# Gemmini ng45 integration model; not a signoff SRAM model
VERSION 5.7 ;
BUSBITCHARS "[]" ;
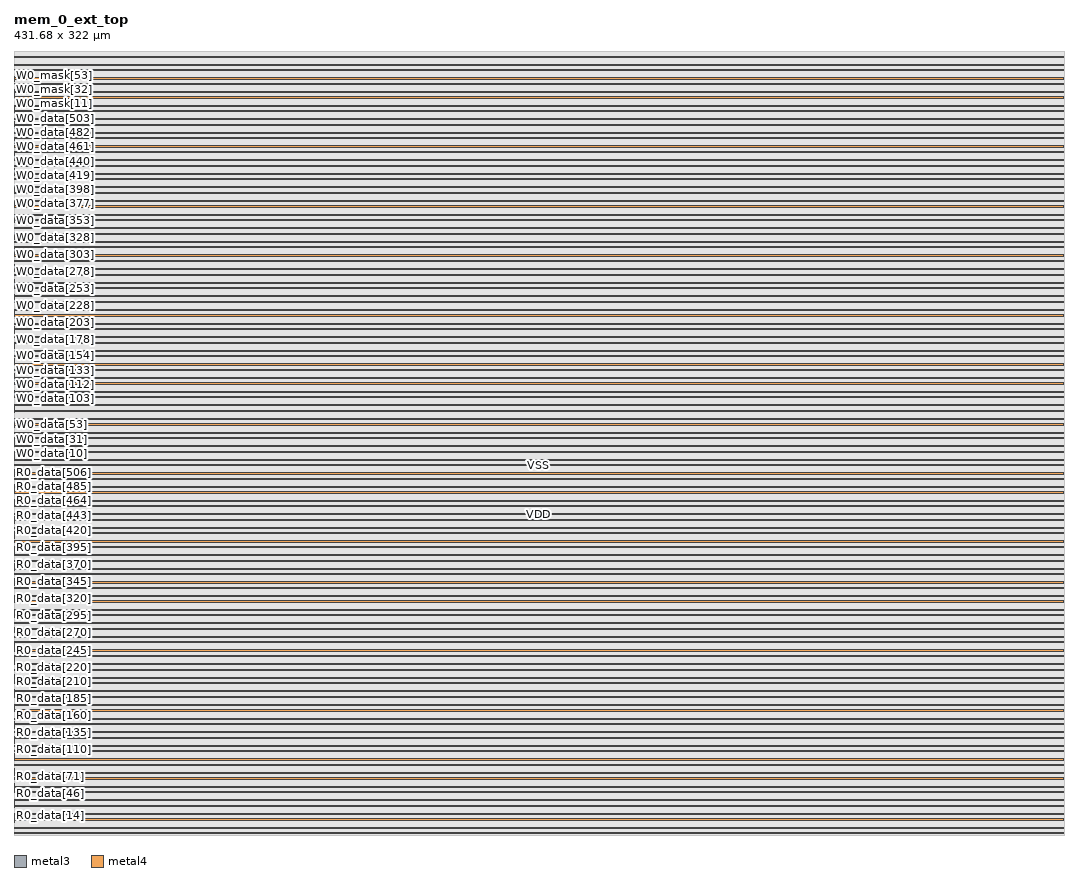
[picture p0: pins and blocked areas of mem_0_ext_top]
MACRO mem_0_ext_top
  FOREIGN mem_0_ext_top 0 0 ;
  SYMMETRY X Y R90 ;
  SIZE 431.680 BY 322.000 ;
  CLASS BLOCK ;
  PIN R0_addr[0]
    DIRECTION INPUT ;
    USE SIGNAL ;
    SHAPE ABUTMENT ;
    PORT
      LAYER metal3 ;
      RECT 0.000 1.365 0.070 1.435 ;
    END
  END R0_addr[0]
  PIN R0_addr[1]
    DIRECTION INPUT ;
    USE SIGNAL ;
    SHAPE ABUTMENT ;
    PORT
      LAYER metal3 ;
      RECT 0.000 1.645 0.070 1.715 ;
    END
  END R0_addr[1]
  PIN R0_addr[2]
    DIRECTION INPUT ;
    USE SIGNAL ;
    SHAPE ABUTMENT ;
    PORT
      LAYER metal3 ;
      RECT 0.000 1.925 0.070 1.995 ;
    END
  END R0_addr[2]
  PIN R0_addr[3]
    DIRECTION INPUT ;
    USE SIGNAL ;
    SHAPE ABUTMENT ;
    PORT
      LAYER metal3 ;
      RECT 0.000 2.205 0.070 2.275 ;
    END
  END R0_addr[3]
  PIN R0_addr[4]
    DIRECTION INPUT ;
    USE SIGNAL ;
    SHAPE ABUTMENT ;
    PORT
      LAYER metal3 ;
      RECT 0.000 2.485 0.070 2.555 ;
    END
  END R0_addr[4]
  PIN R0_addr[5]
    DIRECTION INPUT ;
    USE SIGNAL ;
    SHAPE ABUTMENT ;
    PORT
      LAYER metal3 ;
      RECT 0.000 2.765 0.070 2.835 ;
    END
  END R0_addr[5]
  PIN R0_addr[6]
    DIRECTION INPUT ;
    USE SIGNAL ;
    SHAPE ABUTMENT ;
    PORT
      LAYER metal3 ;
      RECT 0.000 3.045 0.070 3.115 ;
    END
  END R0_addr[6]
  PIN R0_addr[7]
    DIRECTION INPUT ;
    USE SIGNAL ;
    SHAPE ABUTMENT ;
    PORT
      LAYER metal3 ;
      RECT 0.000 3.325 0.070 3.395 ;
    END
  END R0_addr[7]
  PIN R0_addr[8]
    DIRECTION INPUT ;
    USE SIGNAL ;
    SHAPE ABUTMENT ;
    PORT
      LAYER metal3 ;
      RECT 0.000 3.605 0.070 3.675 ;
    END
  END R0_addr[8]
  PIN R0_clk
    DIRECTION INPUT ;
    USE SIGNAL ;
    SHAPE ABUTMENT ;
    PORT
      LAYER metal3 ;
      RECT 0.000 3.885 0.070 3.955 ;
    END
  END R0_clk
  PIN R0_data[0]
    DIRECTION OUTPUT ;
    USE SIGNAL ;
    SHAPE ABUTMENT ;
    PORT
      LAYER metal3 ;
      RECT 0.000 4.165 0.070 4.235 ;
    END
  END R0_data[0]
  PIN R0_data[1]
    DIRECTION OUTPUT ;
    USE SIGNAL ;
    SHAPE ABUTMENT ;
    PORT
      LAYER metal3 ;
      RECT 0.000 4.445 0.070 4.515 ;
    END
  END R0_data[1]
  PIN R0_data[2]
    DIRECTION OUTPUT ;
    USE SIGNAL ;
    SHAPE ABUTMENT ;
    PORT
      LAYER metal3 ;
      RECT 0.000 4.725 0.070 4.795 ;
    END
  END R0_data[2]
  PIN R0_data[3]
    DIRECTION OUTPUT ;
    USE SIGNAL ;
    SHAPE ABUTMENT ;
    PORT
      LAYER metal3 ;
      RECT 0.000 5.005 0.070 5.075 ;
    END
  END R0_data[3]
  PIN R0_data[4]
    DIRECTION OUTPUT ;
    USE SIGNAL ;
    SHAPE ABUTMENT ;
    PORT
      LAYER metal3 ;
      RECT 0.000 5.285 0.070 5.355 ;
    END
  END R0_data[4]
  PIN R0_data[5]
    DIRECTION OUTPUT ;
    USE SIGNAL ;
    SHAPE ABUTMENT ;
    PORT
      LAYER metal3 ;
      RECT 0.000 5.565 0.070 5.635 ;
    END
  END R0_data[5]
  PIN R0_data[6]
    DIRECTION OUTPUT ;
    USE SIGNAL ;
    SHAPE ABUTMENT ;
    PORT
      LAYER metal3 ;
      RECT 0.000 5.845 0.070 5.915 ;
    END
  END R0_data[6]
  PIN R0_data[7]
    DIRECTION OUTPUT ;
    USE SIGNAL ;
    SHAPE ABUTMENT ;
    PORT
      LAYER metal3 ;
      RECT 0.000 6.125 0.070 6.195 ;
    END
  END R0_data[7]
  PIN R0_data[8]
    DIRECTION OUTPUT ;
    USE SIGNAL ;
    SHAPE ABUTMENT ;
    PORT
      LAYER metal3 ;
      RECT 0.000 6.405 0.070 6.475 ;
    END
  END R0_data[8]
  PIN R0_data[9]
    DIRECTION OUTPUT ;
    USE SIGNAL ;
    SHAPE ABUTMENT ;
    PORT
      LAYER metal3 ;
      RECT 0.000 6.685 0.070 6.755 ;
    END
  END R0_data[9]
  PIN R0_data[10]
    DIRECTION OUTPUT ;
    USE SIGNAL ;
    SHAPE ABUTMENT ;
    PORT
      LAYER metal3 ;
      RECT 0.000 6.965 0.070 7.035 ;
    END
  END R0_data[10]
  PIN R0_data[11]
    DIRECTION OUTPUT ;
    USE SIGNAL ;
    SHAPE ABUTMENT ;
    PORT
      LAYER metal3 ;
      RECT 0.000 7.245 0.070 7.315 ;
    END
  END R0_data[11]
  PIN R0_data[12]
    DIRECTION OUTPUT ;
    USE SIGNAL ;
    SHAPE ABUTMENT ;
    PORT
      LAYER metal3 ;
      RECT 0.000 7.525 0.070 7.595 ;
    END
  END R0_data[12]
  PIN R0_data[13]
    DIRECTION OUTPUT ;
    USE SIGNAL ;
    SHAPE ABUTMENT ;
    PORT
      LAYER metal3 ;
      RECT 0.000 7.805 0.070 7.875 ;
    END
  END R0_data[13]
  PIN R0_data[14]
    DIRECTION OUTPUT ;
    USE SIGNAL ;
    SHAPE ABUTMENT ;
    PORT
      LAYER metal3 ;
      RECT 0.000 8.085 0.070 8.155 ;
    END
  END R0_data[14]
  PIN R0_data[15]
    DIRECTION OUTPUT ;
    USE SIGNAL ;
    SHAPE ABUTMENT ;
    PORT
      LAYER metal3 ;
      RECT 0.000 8.365 0.070 8.435 ;
    END
  END R0_data[15]
  PIN R0_data[16]
    DIRECTION OUTPUT ;
    USE SIGNAL ;
    SHAPE ABUTMENT ;
    PORT
      LAYER metal3 ;
      RECT 0.000 8.645 0.070 8.715 ;
    END
  END R0_data[16]
  PIN R0_data[17]
    DIRECTION OUTPUT ;
    USE SIGNAL ;
    SHAPE ABUTMENT ;
    PORT
      LAYER metal3 ;
      RECT 0.000 8.925 0.070 8.995 ;
    END
  END R0_data[17]
  PIN R0_data[18]
    DIRECTION OUTPUT ;
    USE SIGNAL ;
    SHAPE ABUTMENT ;
    PORT
      LAYER metal3 ;
      RECT 0.000 9.205 0.070 9.275 ;
    END
  END R0_data[18]
  PIN R0_data[19]
    DIRECTION OUTPUT ;
    USE SIGNAL ;
    SHAPE ABUTMENT ;
    PORT
      LAYER metal3 ;
      RECT 0.000 9.485 0.070 9.555 ;
    END
  END R0_data[19]
  PIN R0_data[20]
    DIRECTION OUTPUT ;
    USE SIGNAL ;
    SHAPE ABUTMENT ;
    PORT
      LAYER metal3 ;
      RECT 0.000 9.765 0.070 9.835 ;
    END
  END R0_data[20]
  PIN R0_data[21]
    DIRECTION OUTPUT ;
    USE SIGNAL ;
    SHAPE ABUTMENT ;
    PORT
      LAYER metal3 ;
      RECT 0.000 10.045 0.070 10.115 ;
    END
  END R0_data[21]
  PIN R0_data[22]
    DIRECTION OUTPUT ;
    USE SIGNAL ;
    SHAPE ABUTMENT ;
    PORT
      LAYER metal3 ;
      RECT 0.000 10.325 0.070 10.395 ;
    END
  END R0_data[22]
  PIN R0_data[23]
    DIRECTION OUTPUT ;
    USE SIGNAL ;
    SHAPE ABUTMENT ;
    PORT
      LAYER metal3 ;
      RECT 0.000 10.605 0.070 10.675 ;
    END
  END R0_data[23]
  PIN R0_data[24]
    DIRECTION OUTPUT ;
    USE SIGNAL ;
    SHAPE ABUTMENT ;
    PORT
      LAYER metal3 ;
      RECT 0.000 10.885 0.070 10.955 ;
    END
  END R0_data[24]
  PIN R0_data[25]
    DIRECTION OUTPUT ;
    USE SIGNAL ;
    SHAPE ABUTMENT ;
    PORT
      LAYER metal3 ;
      RECT 0.000 11.165 0.070 11.235 ;
    END
  END R0_data[25]
  PIN R0_data[26]
    DIRECTION OUTPUT ;
    USE SIGNAL ;
    SHAPE ABUTMENT ;
    PORT
      LAYER metal3 ;
      RECT 0.000 11.445 0.070 11.515 ;
    END
  END R0_data[26]
  PIN R0_data[27]
    DIRECTION OUTPUT ;
    USE SIGNAL ;
    SHAPE ABUTMENT ;
    PORT
      LAYER metal3 ;
      RECT 0.000 11.725 0.070 11.795 ;
    END
  END R0_data[27]
  PIN R0_data[28]
    DIRECTION OUTPUT ;
    USE SIGNAL ;
    SHAPE ABUTMENT ;
    PORT
      LAYER metal3 ;
      RECT 0.000 12.005 0.070 12.075 ;
    END
  END R0_data[28]
  PIN R0_data[29]
    DIRECTION OUTPUT ;
    USE SIGNAL ;
    SHAPE ABUTMENT ;
    PORT
      LAYER metal3 ;
      RECT 0.000 12.285 0.070 12.355 ;
    END
  END R0_data[29]
  PIN R0_data[30]
    DIRECTION OUTPUT ;
    USE SIGNAL ;
    SHAPE ABUTMENT ;
    PORT
      LAYER metal3 ;
      RECT 0.000 12.565 0.070 12.635 ;
    END
  END R0_data[30]
  PIN R0_data[31]
    DIRECTION OUTPUT ;
    USE SIGNAL ;
    SHAPE ABUTMENT ;
    PORT
      LAYER metal3 ;
      RECT 0.000 12.845 0.070 12.915 ;
    END
  END R0_data[31]
  PIN R0_data[32]
    DIRECTION OUTPUT ;
    USE SIGNAL ;
    SHAPE ABUTMENT ;
    PORT
      LAYER metal3 ;
      RECT 0.000 13.125 0.070 13.195 ;
    END
  END R0_data[32]
  PIN R0_data[33]
    DIRECTION OUTPUT ;
    USE SIGNAL ;
    SHAPE ABUTMENT ;
    PORT
      LAYER metal3 ;
      RECT 0.000 13.405 0.070 13.475 ;
    END
  END R0_data[33]
  PIN R0_data[34]
    DIRECTION OUTPUT ;
    USE SIGNAL ;
    SHAPE ABUTMENT ;
    PORT
      LAYER metal3 ;
      RECT 0.000 13.685 0.070 13.755 ;
    END
  END R0_data[34]
  PIN R0_data[35]
    DIRECTION OUTPUT ;
    USE SIGNAL ;
    SHAPE ABUTMENT ;
    PORT
      LAYER metal3 ;
      RECT 0.000 13.965 0.070 14.035 ;
    END
  END R0_data[35]
  PIN R0_data[36]
    DIRECTION OUTPUT ;
    USE SIGNAL ;
    SHAPE ABUTMENT ;
    PORT
      LAYER metal3 ;
      RECT 0.000 14.245 0.070 14.315 ;
    END
  END R0_data[36]
  PIN R0_data[37]
    DIRECTION OUTPUT ;
    USE SIGNAL ;
    SHAPE ABUTMENT ;
    PORT
      LAYER metal3 ;
      RECT 0.000 14.525 0.070 14.595 ;
    END
  END R0_data[37]
  PIN R0_data[38]
    DIRECTION OUTPUT ;
    USE SIGNAL ;
    SHAPE ABUTMENT ;
    PORT
      LAYER metal3 ;
      RECT 0.000 14.805 0.070 14.875 ;
    END
  END R0_data[38]
  PIN R0_data[39]
    DIRECTION OUTPUT ;
    USE SIGNAL ;
    SHAPE ABUTMENT ;
    PORT
      LAYER metal3 ;
      RECT 0.000 15.085 0.070 15.155 ;
    END
  END R0_data[39]
  PIN R0_data[40]
    DIRECTION OUTPUT ;
    USE SIGNAL ;
    SHAPE ABUTMENT ;
    PORT
      LAYER metal3 ;
      RECT 0.000 15.365 0.070 15.435 ;
    END
  END R0_data[40]
  PIN R0_data[41]
    DIRECTION OUTPUT ;
    USE SIGNAL ;
    SHAPE ABUTMENT ;
    PORT
      LAYER metal3 ;
      RECT 0.000 15.645 0.070 15.715 ;
    END
  END R0_data[41]
  PIN R0_data[42]
    DIRECTION OUTPUT ;
    USE SIGNAL ;
    SHAPE ABUTMENT ;
    PORT
      LAYER metal3 ;
      RECT 0.000 15.925 0.070 15.995 ;
    END
  END R0_data[42]
  PIN R0_data[43]
    DIRECTION OUTPUT ;
    USE SIGNAL ;
    SHAPE ABUTMENT ;
    PORT
      LAYER metal3 ;
      RECT 0.000 16.205 0.070 16.275 ;
    END
  END R0_data[43]
  PIN R0_data[44]
    DIRECTION OUTPUT ;
    USE SIGNAL ;
    SHAPE ABUTMENT ;
    PORT
      LAYER metal3 ;
      RECT 0.000 16.485 0.070 16.555 ;
    END
  END R0_data[44]
  PIN R0_data[45]
    DIRECTION OUTPUT ;
    USE SIGNAL ;
    SHAPE ABUTMENT ;
    PORT
      LAYER metal3 ;
      RECT 0.000 16.765 0.070 16.835 ;
    END
  END R0_data[45]
  PIN R0_data[46]
    DIRECTION OUTPUT ;
    USE SIGNAL ;
    SHAPE ABUTMENT ;
    PORT
      LAYER metal3 ;
      RECT 0.000 17.045 0.070 17.115 ;
    END
  END R0_data[46]
  PIN R0_data[47]
    DIRECTION OUTPUT ;
    USE SIGNAL ;
    SHAPE ABUTMENT ;
    PORT
      LAYER metal3 ;
      RECT 0.000 17.325 0.070 17.395 ;
    END
  END R0_data[47]
  PIN R0_data[48]
    DIRECTION OUTPUT ;
    USE SIGNAL ;
    SHAPE ABUTMENT ;
    PORT
      LAYER metal3 ;
      RECT 0.000 17.605 0.070 17.675 ;
    END
  END R0_data[48]
  PIN R0_data[49]
    DIRECTION OUTPUT ;
    USE SIGNAL ;
    SHAPE ABUTMENT ;
    PORT
      LAYER metal3 ;
      RECT 0.000 17.885 0.070 17.955 ;
    END
  END R0_data[49]
  PIN R0_data[50]
    DIRECTION OUTPUT ;
    USE SIGNAL ;
    SHAPE ABUTMENT ;
    PORT
      LAYER metal3 ;
      RECT 0.000 18.165 0.070 18.235 ;
    END
  END R0_data[50]
  PIN R0_data[51]
    DIRECTION OUTPUT ;
    USE SIGNAL ;
    SHAPE ABUTMENT ;
    PORT
      LAYER metal3 ;
      RECT 0.000 18.445 0.070 18.515 ;
    END
  END R0_data[51]
  PIN R0_data[52]
    DIRECTION OUTPUT ;
    USE SIGNAL ;
    SHAPE ABUTMENT ;
    PORT
      LAYER metal3 ;
      RECT 0.000 18.725 0.070 18.795 ;
    END
  END R0_data[52]
  PIN R0_data[53]
    DIRECTION OUTPUT ;
    USE SIGNAL ;
    SHAPE ABUTMENT ;
    PORT
      LAYER metal3 ;
      RECT 0.000 19.005 0.070 19.075 ;
    END
  END R0_data[53]
  PIN R0_data[54]
    DIRECTION OUTPUT ;
    USE SIGNAL ;
    SHAPE ABUTMENT ;
    PORT
      LAYER metal3 ;
      RECT 0.000 19.285 0.070 19.355 ;
    END
  END R0_data[54]
  PIN R0_data[55]
    DIRECTION OUTPUT ;
    USE SIGNAL ;
    SHAPE ABUTMENT ;
    PORT
      LAYER metal3 ;
      RECT 0.000 19.565 0.070 19.635 ;
    END
  END R0_data[55]
  PIN R0_data[56]
    DIRECTION OUTPUT ;
    USE SIGNAL ;
    SHAPE ABUTMENT ;
    PORT
      LAYER metal3 ;
      RECT 0.000 19.845 0.070 19.915 ;
    END
  END R0_data[56]
  PIN R0_data[57]
    DIRECTION OUTPUT ;
    USE SIGNAL ;
    SHAPE ABUTMENT ;
    PORT
      LAYER metal3 ;
      RECT 0.000 20.125 0.070 20.195 ;
    END
  END R0_data[57]
  PIN R0_data[58]
    DIRECTION OUTPUT ;
    USE SIGNAL ;
    SHAPE ABUTMENT ;
    PORT
      LAYER metal3 ;
      RECT 0.000 20.405 0.070 20.475 ;
    END
  END R0_data[58]
  PIN R0_data[59]
    DIRECTION OUTPUT ;
    USE SIGNAL ;
    SHAPE ABUTMENT ;
    PORT
      LAYER metal3 ;
      RECT 0.000 20.685 0.070 20.755 ;
    END
  END R0_data[59]
  PIN R0_data[60]
    DIRECTION OUTPUT ;
    USE SIGNAL ;
    SHAPE ABUTMENT ;
    PORT
      LAYER metal3 ;
      RECT 0.000 20.965 0.070 21.035 ;
    END
  END R0_data[60]
  PIN R0_data[61]
    DIRECTION OUTPUT ;
    USE SIGNAL ;
    SHAPE ABUTMENT ;
    PORT
      LAYER metal3 ;
      RECT 0.000 21.245 0.070 21.315 ;
    END
  END R0_data[61]
  PIN R0_data[62]
    DIRECTION OUTPUT ;
    USE SIGNAL ;
    SHAPE ABUTMENT ;
    PORT
      LAYER metal3 ;
      RECT 0.000 21.525 0.070 21.595 ;
    END
  END R0_data[62]
  PIN R0_data[63]
    DIRECTION OUTPUT ;
    USE SIGNAL ;
    SHAPE ABUTMENT ;
    PORT
      LAYER metal3 ;
      RECT 0.000 21.805 0.070 21.875 ;
    END
  END R0_data[63]
  PIN R0_data[64]
    DIRECTION OUTPUT ;
    USE SIGNAL ;
    SHAPE ABUTMENT ;
    PORT
      LAYER metal3 ;
      RECT 0.000 22.085 0.070 22.155 ;
    END
  END R0_data[64]
  PIN R0_data[65]
    DIRECTION OUTPUT ;
    USE SIGNAL ;
    SHAPE ABUTMENT ;
    PORT
      LAYER metal3 ;
      RECT 0.000 22.365 0.070 22.435 ;
    END
  END R0_data[65]
  PIN R0_data[66]
    DIRECTION OUTPUT ;
    USE SIGNAL ;
    SHAPE ABUTMENT ;
    PORT
      LAYER metal3 ;
      RECT 0.000 22.645 0.070 22.715 ;
    END
  END R0_data[66]
  PIN R0_data[67]
    DIRECTION OUTPUT ;
    USE SIGNAL ;
    SHAPE ABUTMENT ;
    PORT
      LAYER metal3 ;
      RECT 0.000 22.925 0.070 22.995 ;
    END
  END R0_data[67]
  PIN R0_data[68]
    DIRECTION OUTPUT ;
    USE SIGNAL ;
    SHAPE ABUTMENT ;
    PORT
      LAYER metal3 ;
      RECT 0.000 23.205 0.070 23.275 ;
    END
  END R0_data[68]
  PIN R0_data[69]
    DIRECTION OUTPUT ;
    USE SIGNAL ;
    SHAPE ABUTMENT ;
    PORT
      LAYER metal3 ;
      RECT 0.000 23.485 0.070 23.555 ;
    END
  END R0_data[69]
  PIN R0_data[70]
    DIRECTION OUTPUT ;
    USE SIGNAL ;
    SHAPE ABUTMENT ;
    PORT
      LAYER metal3 ;
      RECT 0.000 23.765 0.070 23.835 ;
    END
  END R0_data[70]
  PIN R0_data[71]
    DIRECTION OUTPUT ;
    USE SIGNAL ;
    SHAPE ABUTMENT ;
    PORT
      LAYER metal3 ;
      RECT 0.000 24.045 0.070 24.115 ;
    END
  END R0_data[71]
  PIN R0_data[72]
    DIRECTION OUTPUT ;
    USE SIGNAL ;
    SHAPE ABUTMENT ;
    PORT
      LAYER metal3 ;
      RECT 0.000 24.325 0.070 24.395 ;
    END
  END R0_data[72]
  PIN R0_data[73]
    DIRECTION OUTPUT ;
    USE SIGNAL ;
    SHAPE ABUTMENT ;
    PORT
      LAYER metal3 ;
      RECT 0.000 24.605 0.070 24.675 ;
    END
  END R0_data[73]
  PIN R0_data[74]
    DIRECTION OUTPUT ;
    USE SIGNAL ;
    SHAPE ABUTMENT ;
    PORT
      LAYER metal3 ;
      RECT 0.000 24.885 0.070 24.955 ;
    END
  END R0_data[74]
  PIN R0_data[75]
    DIRECTION OUTPUT ;
    USE SIGNAL ;
    SHAPE ABUTMENT ;
    PORT
      LAYER metal3 ;
      RECT 0.000 25.165 0.070 25.235 ;
    END
  END R0_data[75]
  PIN R0_data[76]
    DIRECTION OUTPUT ;
    USE SIGNAL ;
    SHAPE ABUTMENT ;
    PORT
      LAYER metal3 ;
      RECT 0.000 25.445 0.070 25.515 ;
    END
  END R0_data[76]
  PIN R0_data[77]
    DIRECTION OUTPUT ;
    USE SIGNAL ;
    SHAPE ABUTMENT ;
    PORT
      LAYER metal3 ;
      RECT 0.000 25.725 0.070 25.795 ;
    END
  END R0_data[77]
  PIN R0_data[78]
    DIRECTION OUTPUT ;
    USE SIGNAL ;
    SHAPE ABUTMENT ;
    PORT
      LAYER metal3 ;
      RECT 0.000 26.005 0.070 26.075 ;
    END
  END R0_data[78]
  PIN R0_data[79]
    DIRECTION OUTPUT ;
    USE SIGNAL ;
    SHAPE ABUTMENT ;
    PORT
      LAYER metal3 ;
      RECT 0.000 26.285 0.070 26.355 ;
    END
  END R0_data[79]
  PIN R0_data[80]
    DIRECTION OUTPUT ;
    USE SIGNAL ;
    SHAPE ABUTMENT ;
    PORT
      LAYER metal3 ;
      RECT 0.000 26.565 0.070 26.635 ;
    END
  END R0_data[80]
  PIN R0_data[81]
    DIRECTION OUTPUT ;
    USE SIGNAL ;
    SHAPE ABUTMENT ;
    PORT
      LAYER metal3 ;
      RECT 0.000 26.845 0.070 26.915 ;
    END
  END R0_data[81]
  PIN R0_data[82]
    DIRECTION OUTPUT ;
    USE SIGNAL ;
    SHAPE ABUTMENT ;
    PORT
      LAYER metal3 ;
      RECT 0.000 27.125 0.070 27.195 ;
    END
  END R0_data[82]
  PIN R0_data[83]
    DIRECTION OUTPUT ;
    USE SIGNAL ;
    SHAPE ABUTMENT ;
    PORT
      LAYER metal3 ;
      RECT 0.000 27.405 0.070 27.475 ;
    END
  END R0_data[83]
  PIN R0_data[84]
    DIRECTION OUTPUT ;
    USE SIGNAL ;
    SHAPE ABUTMENT ;
    PORT
      LAYER metal3 ;
      RECT 0.000 27.685 0.070 27.755 ;
    END
  END R0_data[84]
  PIN R0_data[85]
    DIRECTION OUTPUT ;
    USE SIGNAL ;
    SHAPE ABUTMENT ;
    PORT
      LAYER metal3 ;
      RECT 0.000 27.965 0.070 28.035 ;
    END
  END R0_data[85]
  PIN R0_data[86]
    DIRECTION OUTPUT ;
    USE SIGNAL ;
    SHAPE ABUTMENT ;
    PORT
      LAYER metal3 ;
      RECT 0.000 28.245 0.070 28.315 ;
    END
  END R0_data[86]
  PIN R0_data[87]
    DIRECTION OUTPUT ;
    USE SIGNAL ;
    SHAPE ABUTMENT ;
    PORT
      LAYER metal3 ;
      RECT 0.000 28.525 0.070 28.595 ;
    END
  END R0_data[87]
  PIN R0_data[88]
    DIRECTION OUTPUT ;
    USE SIGNAL ;
    SHAPE ABUTMENT ;
    PORT
      LAYER metal3 ;
      RECT 0.000 28.805 0.070 28.875 ;
    END
  END R0_data[88]
  PIN R0_data[89]
    DIRECTION OUTPUT ;
    USE SIGNAL ;
    SHAPE ABUTMENT ;
    PORT
      LAYER metal3 ;
      RECT 0.000 29.085 0.070 29.155 ;
    END
  END R0_data[89]
  PIN R0_data[90]
    DIRECTION OUTPUT ;
    USE SIGNAL ;
    SHAPE ABUTMENT ;
    PORT
      LAYER metal3 ;
      RECT 0.000 29.365 0.070 29.435 ;
    END
  END R0_data[90]
  PIN R0_data[91]
    DIRECTION OUTPUT ;
    USE SIGNAL ;
    SHAPE ABUTMENT ;
    PORT
      LAYER metal3 ;
      RECT 0.000 29.645 0.070 29.715 ;
    END
  END R0_data[91]
  PIN R0_data[92]
    DIRECTION OUTPUT ;
    USE SIGNAL ;
    SHAPE ABUTMENT ;
    PORT
      LAYER metal3 ;
      RECT 0.000 29.925 0.070 29.995 ;
    END
  END R0_data[92]
  PIN R0_data[93]
    DIRECTION OUTPUT ;
    USE SIGNAL ;
    SHAPE ABUTMENT ;
    PORT
      LAYER metal3 ;
      RECT 0.000 30.205 0.070 30.275 ;
    END
  END R0_data[93]
  PIN R0_data[94]
    DIRECTION OUTPUT ;
    USE SIGNAL ;
    SHAPE ABUTMENT ;
    PORT
      LAYER metal3 ;
      RECT 0.000 30.485 0.070 30.555 ;
    END
  END R0_data[94]
  PIN R0_data[95]
    DIRECTION OUTPUT ;
    USE SIGNAL ;
    SHAPE ABUTMENT ;
    PORT
      LAYER metal3 ;
      RECT 0.000 30.765 0.070 30.835 ;
    END
  END R0_data[95]
  PIN R0_data[96]
    DIRECTION OUTPUT ;
    USE SIGNAL ;
    SHAPE ABUTMENT ;
    PORT
      LAYER metal3 ;
      RECT 0.000 31.045 0.070 31.115 ;
    END
  END R0_data[96]
  PIN R0_data[97]
    DIRECTION OUTPUT ;
    USE SIGNAL ;
    SHAPE ABUTMENT ;
    PORT
      LAYER metal3 ;
      RECT 0.000 31.325 0.070 31.395 ;
    END
  END R0_data[97]
  PIN R0_data[98]
    DIRECTION OUTPUT ;
    USE SIGNAL ;
    SHAPE ABUTMENT ;
    PORT
      LAYER metal3 ;
      RECT 0.000 31.605 0.070 31.675 ;
    END
  END R0_data[98]
  PIN R0_data[99]
    DIRECTION OUTPUT ;
    USE SIGNAL ;
    SHAPE ABUTMENT ;
    PORT
      LAYER metal3 ;
      RECT 0.000 31.885 0.070 31.955 ;
    END
  END R0_data[99]
  PIN R0_data[100]
    DIRECTION OUTPUT ;
    USE SIGNAL ;
    SHAPE ABUTMENT ;
    PORT
      LAYER metal3 ;
      RECT 0.000 32.165 0.070 32.235 ;
    END
  END R0_data[100]
  PIN R0_data[101]
    DIRECTION OUTPUT ;
    USE SIGNAL ;
    SHAPE ABUTMENT ;
    PORT
      LAYER metal3 ;
      RECT 0.000 32.445 0.070 32.515 ;
    END
  END R0_data[101]
  PIN R0_data[102]
    DIRECTION OUTPUT ;
    USE SIGNAL ;
    SHAPE ABUTMENT ;
    PORT
      LAYER metal3 ;
      RECT 0.000 32.725 0.070 32.795 ;
    END
  END R0_data[102]
  PIN R0_data[103]
    DIRECTION OUTPUT ;
    USE SIGNAL ;
    SHAPE ABUTMENT ;
    PORT
      LAYER metal3 ;
      RECT 0.000 33.005 0.070 33.075 ;
    END
  END R0_data[103]
  PIN R0_data[104]
    DIRECTION OUTPUT ;
    USE SIGNAL ;
    SHAPE ABUTMENT ;
    PORT
      LAYER metal3 ;
      RECT 0.000 33.285 0.070 33.355 ;
    END
  END R0_data[104]
  PIN R0_data[105]
    DIRECTION OUTPUT ;
    USE SIGNAL ;
    SHAPE ABUTMENT ;
    PORT
      LAYER metal3 ;
      RECT 0.000 33.565 0.070 33.635 ;
    END
  END R0_data[105]
  PIN R0_data[106]
    DIRECTION OUTPUT ;
    USE SIGNAL ;
    SHAPE ABUTMENT ;
    PORT
      LAYER metal3 ;
      RECT 0.000 33.845 0.070 33.915 ;
    END
  END R0_data[106]
  PIN R0_data[107]
    DIRECTION OUTPUT ;
    USE SIGNAL ;
    SHAPE ABUTMENT ;
    PORT
      LAYER metal3 ;
      RECT 0.000 34.125 0.070 34.195 ;
    END
  END R0_data[107]
  PIN R0_data[108]
    DIRECTION OUTPUT ;
    USE SIGNAL ;
    SHAPE ABUTMENT ;
    PORT
      LAYER metal3 ;
      RECT 0.000 34.405 0.070 34.475 ;
    END
  END R0_data[108]
  PIN R0_data[109]
    DIRECTION OUTPUT ;
    USE SIGNAL ;
    SHAPE ABUTMENT ;
    PORT
      LAYER metal3 ;
      RECT 0.000 34.685 0.070 34.755 ;
    END
  END R0_data[109]
  PIN R0_data[110]
    DIRECTION OUTPUT ;
    USE SIGNAL ;
    SHAPE ABUTMENT ;
    PORT
      LAYER metal3 ;
      RECT 0.000 34.965 0.070 35.035 ;
    END
  END R0_data[110]
  PIN R0_data[111]
    DIRECTION OUTPUT ;
    USE SIGNAL ;
    SHAPE ABUTMENT ;
    PORT
      LAYER metal3 ;
      RECT 0.000 35.245 0.070 35.315 ;
    END
  END R0_data[111]
  PIN R0_data[112]
    DIRECTION OUTPUT ;
    USE SIGNAL ;
    SHAPE ABUTMENT ;
    PORT
      LAYER metal3 ;
      RECT 0.000 35.525 0.070 35.595 ;
    END
  END R0_data[112]
  PIN R0_data[113]
    DIRECTION OUTPUT ;
    USE SIGNAL ;
    SHAPE ABUTMENT ;
    PORT
      LAYER metal3 ;
      RECT 0.000 35.805 0.070 35.875 ;
    END
  END R0_data[113]
  PIN R0_data[114]
    DIRECTION OUTPUT ;
    USE SIGNAL ;
    SHAPE ABUTMENT ;
    PORT
      LAYER metal3 ;
      RECT 0.000 36.085 0.070 36.155 ;
    END
  END R0_data[114]
  PIN R0_data[115]
    DIRECTION OUTPUT ;
    USE SIGNAL ;
    SHAPE ABUTMENT ;
    PORT
      LAYER metal3 ;
      RECT 0.000 36.365 0.070 36.435 ;
    END
  END R0_data[115]
  PIN R0_data[116]
    DIRECTION OUTPUT ;
    USE SIGNAL ;
    SHAPE ABUTMENT ;
    PORT
      LAYER metal3 ;
      RECT 0.000 36.645 0.070 36.715 ;
    END
  END R0_data[116]
  PIN R0_data[117]
    DIRECTION OUTPUT ;
    USE SIGNAL ;
    SHAPE ABUTMENT ;
    PORT
      LAYER metal3 ;
      RECT 0.000 36.925 0.070 36.995 ;
    END
  END R0_data[117]
  PIN R0_data[118]
    DIRECTION OUTPUT ;
    USE SIGNAL ;
    SHAPE ABUTMENT ;
    PORT
      LAYER metal3 ;
      RECT 0.000 37.205 0.070 37.275 ;
    END
  END R0_data[118]
  PIN R0_data[119]
    DIRECTION OUTPUT ;
    USE SIGNAL ;
    SHAPE ABUTMENT ;
    PORT
      LAYER metal3 ;
      RECT 0.000 37.485 0.070 37.555 ;
    END
  END R0_data[119]
  PIN R0_data[120]
    DIRECTION OUTPUT ;
    USE SIGNAL ;
    SHAPE ABUTMENT ;
    PORT
      LAYER metal3 ;
      RECT 0.000 37.765 0.070 37.835 ;
    END
  END R0_data[120]
  PIN R0_data[121]
    DIRECTION OUTPUT ;
    USE SIGNAL ;
    SHAPE ABUTMENT ;
    PORT
      LAYER metal3 ;
      RECT 0.000 38.045 0.070 38.115 ;
    END
  END R0_data[121]
  PIN R0_data[122]
    DIRECTION OUTPUT ;
    USE SIGNAL ;
    SHAPE ABUTMENT ;
    PORT
      LAYER metal3 ;
      RECT 0.000 38.325 0.070 38.395 ;
    END
  END R0_data[122]
  PIN R0_data[123]
    DIRECTION OUTPUT ;
    USE SIGNAL ;
    SHAPE ABUTMENT ;
    PORT
      LAYER metal3 ;
      RECT 0.000 38.605 0.070 38.675 ;
    END
  END R0_data[123]
  PIN R0_data[124]
    DIRECTION OUTPUT ;
    USE SIGNAL ;
    SHAPE ABUTMENT ;
    PORT
      LAYER metal3 ;
      RECT 0.000 38.885 0.070 38.955 ;
    END
  END R0_data[124]
  PIN R0_data[125]
    DIRECTION OUTPUT ;
    USE SIGNAL ;
    SHAPE ABUTMENT ;
    PORT
      LAYER metal3 ;
      RECT 0.000 39.165 0.070 39.235 ;
    END
  END R0_data[125]
  PIN R0_data[126]
    DIRECTION OUTPUT ;
    USE SIGNAL ;
    SHAPE ABUTMENT ;
    PORT
      LAYER metal3 ;
      RECT 0.000 39.445 0.070 39.515 ;
    END
  END R0_data[126]
  PIN R0_data[127]
    DIRECTION OUTPUT ;
    USE SIGNAL ;
    SHAPE ABUTMENT ;
    PORT
      LAYER metal3 ;
      RECT 0.000 39.725 0.070 39.795 ;
    END
  END R0_data[127]
  PIN R0_data[128]
    DIRECTION OUTPUT ;
    USE SIGNAL ;
    SHAPE ABUTMENT ;
    PORT
      LAYER metal3 ;
      RECT 0.000 40.005 0.070 40.075 ;
    END
  END R0_data[128]
  PIN R0_data[129]
    DIRECTION OUTPUT ;
    USE SIGNAL ;
    SHAPE ABUTMENT ;
    PORT
      LAYER metal3 ;
      RECT 0.000 40.285 0.070 40.355 ;
    END
  END R0_data[129]
  PIN R0_data[130]
    DIRECTION OUTPUT ;
    USE SIGNAL ;
    SHAPE ABUTMENT ;
    PORT
      LAYER metal3 ;
      RECT 0.000 40.565 0.070 40.635 ;
    END
  END R0_data[130]
  PIN R0_data[131]
    DIRECTION OUTPUT ;
    USE SIGNAL ;
    SHAPE ABUTMENT ;
    PORT
      LAYER metal3 ;
      RECT 0.000 40.845 0.070 40.915 ;
    END
  END R0_data[131]
  PIN R0_data[132]
    DIRECTION OUTPUT ;
    USE SIGNAL ;
    SHAPE ABUTMENT ;
    PORT
      LAYER metal3 ;
      RECT 0.000 41.125 0.070 41.195 ;
    END
  END R0_data[132]
  PIN R0_data[133]
    DIRECTION OUTPUT ;
    USE SIGNAL ;
    SHAPE ABUTMENT ;
    PORT
      LAYER metal3 ;
      RECT 0.000 41.405 0.070 41.475 ;
    END
  END R0_data[133]
  PIN R0_data[134]
    DIRECTION OUTPUT ;
    USE SIGNAL ;
    SHAPE ABUTMENT ;
    PORT
      LAYER metal3 ;
      RECT 0.000 41.685 0.070 41.755 ;
    END
  END R0_data[134]
  PIN R0_data[135]
    DIRECTION OUTPUT ;
    USE SIGNAL ;
    SHAPE ABUTMENT ;
    PORT
      LAYER metal3 ;
      RECT 0.000 41.965 0.070 42.035 ;
    END
  END R0_data[135]
  PIN R0_data[136]
    DIRECTION OUTPUT ;
    USE SIGNAL ;
    SHAPE ABUTMENT ;
    PORT
      LAYER metal3 ;
      RECT 0.000 42.245 0.070 42.315 ;
    END
  END R0_data[136]
  PIN R0_data[137]
    DIRECTION OUTPUT ;
    USE SIGNAL ;
    SHAPE ABUTMENT ;
    PORT
      LAYER metal3 ;
      RECT 0.000 42.525 0.070 42.595 ;
    END
  END R0_data[137]
  PIN R0_data[138]
    DIRECTION OUTPUT ;
    USE SIGNAL ;
    SHAPE ABUTMENT ;
    PORT
      LAYER metal3 ;
      RECT 0.000 42.805 0.070 42.875 ;
    END
  END R0_data[138]
  PIN R0_data[139]
    DIRECTION OUTPUT ;
    USE SIGNAL ;
    SHAPE ABUTMENT ;
    PORT
      LAYER metal3 ;
      RECT 0.000 43.085 0.070 43.155 ;
    END
  END R0_data[139]
  PIN R0_data[140]
    DIRECTION OUTPUT ;
    USE SIGNAL ;
    SHAPE ABUTMENT ;
    PORT
      LAYER metal3 ;
      RECT 0.000 43.365 0.070 43.435 ;
    END
  END R0_data[140]
  PIN R0_data[141]
    DIRECTION OUTPUT ;
    USE SIGNAL ;
    SHAPE ABUTMENT ;
    PORT
      LAYER metal3 ;
      RECT 0.000 43.645 0.070 43.715 ;
    END
  END R0_data[141]
  PIN R0_data[142]
    DIRECTION OUTPUT ;
    USE SIGNAL ;
    SHAPE ABUTMENT ;
    PORT
      LAYER metal3 ;
      RECT 0.000 43.925 0.070 43.995 ;
    END
  END R0_data[142]
  PIN R0_data[143]
    DIRECTION OUTPUT ;
    USE SIGNAL ;
    SHAPE ABUTMENT ;
    PORT
      LAYER metal3 ;
      RECT 0.000 44.205 0.070 44.275 ;
    END
  END R0_data[143]
  PIN R0_data[144]
    DIRECTION OUTPUT ;
    USE SIGNAL ;
    SHAPE ABUTMENT ;
    PORT
      LAYER metal3 ;
      RECT 0.000 44.485 0.070 44.555 ;
    END
  END R0_data[144]
  PIN R0_data[145]
    DIRECTION OUTPUT ;
    USE SIGNAL ;
    SHAPE ABUTMENT ;
    PORT
      LAYER metal3 ;
      RECT 0.000 44.765 0.070 44.835 ;
    END
  END R0_data[145]
  PIN R0_data[146]
    DIRECTION OUTPUT ;
    USE SIGNAL ;
    SHAPE ABUTMENT ;
    PORT
      LAYER metal3 ;
      RECT 0.000 45.045 0.070 45.115 ;
    END
  END R0_data[146]
  PIN R0_data[147]
    DIRECTION OUTPUT ;
    USE SIGNAL ;
    SHAPE ABUTMENT ;
    PORT
      LAYER metal3 ;
      RECT 0.000 45.325 0.070 45.395 ;
    END
  END R0_data[147]
  PIN R0_data[148]
    DIRECTION OUTPUT ;
    USE SIGNAL ;
    SHAPE ABUTMENT ;
    PORT
      LAYER metal3 ;
      RECT 0.000 45.605 0.070 45.675 ;
    END
  END R0_data[148]
  PIN R0_data[149]
    DIRECTION OUTPUT ;
    USE SIGNAL ;
    SHAPE ABUTMENT ;
    PORT
      LAYER metal3 ;
      RECT 0.000 45.885 0.070 45.955 ;
    END
  END R0_data[149]
  PIN R0_data[150]
    DIRECTION OUTPUT ;
    USE SIGNAL ;
    SHAPE ABUTMENT ;
    PORT
      LAYER metal3 ;
      RECT 0.000 46.165 0.070 46.235 ;
    END
  END R0_data[150]
  PIN R0_data[151]
    DIRECTION OUTPUT ;
    USE SIGNAL ;
    SHAPE ABUTMENT ;
    PORT
      LAYER metal3 ;
      RECT 0.000 46.445 0.070 46.515 ;
    END
  END R0_data[151]
  PIN R0_data[152]
    DIRECTION OUTPUT ;
    USE SIGNAL ;
    SHAPE ABUTMENT ;
    PORT
      LAYER metal3 ;
      RECT 0.000 46.725 0.070 46.795 ;
    END
  END R0_data[152]
  PIN R0_data[153]
    DIRECTION OUTPUT ;
    USE SIGNAL ;
    SHAPE ABUTMENT ;
    PORT
      LAYER metal3 ;
      RECT 0.000 47.005 0.070 47.075 ;
    END
  END R0_data[153]
  PIN R0_data[154]
    DIRECTION OUTPUT ;
    USE SIGNAL ;
    SHAPE ABUTMENT ;
    PORT
      LAYER metal3 ;
      RECT 0.000 47.285 0.070 47.355 ;
    END
  END R0_data[154]
  PIN R0_data[155]
    DIRECTION OUTPUT ;
    USE SIGNAL ;
    SHAPE ABUTMENT ;
    PORT
      LAYER metal3 ;
      RECT 0.000 47.565 0.070 47.635 ;
    END
  END R0_data[155]
  PIN R0_data[156]
    DIRECTION OUTPUT ;
    USE SIGNAL ;
    SHAPE ABUTMENT ;
    PORT
      LAYER metal3 ;
      RECT 0.000 47.845 0.070 47.915 ;
    END
  END R0_data[156]
  PIN R0_data[157]
    DIRECTION OUTPUT ;
    USE SIGNAL ;
    SHAPE ABUTMENT ;
    PORT
      LAYER metal3 ;
      RECT 0.000 48.125 0.070 48.195 ;
    END
  END R0_data[157]
  PIN R0_data[158]
    DIRECTION OUTPUT ;
    USE SIGNAL ;
    SHAPE ABUTMENT ;
    PORT
      LAYER metal3 ;
      RECT 0.000 48.405 0.070 48.475 ;
    END
  END R0_data[158]
  PIN R0_data[159]
    DIRECTION OUTPUT ;
    USE SIGNAL ;
    SHAPE ABUTMENT ;
    PORT
      LAYER metal3 ;
      RECT 0.000 48.685 0.070 48.755 ;
    END
  END R0_data[159]
  PIN R0_data[160]
    DIRECTION OUTPUT ;
    USE SIGNAL ;
    SHAPE ABUTMENT ;
    PORT
      LAYER metal3 ;
      RECT 0.000 48.965 0.070 49.035 ;
    END
  END R0_data[160]
  PIN R0_data[161]
    DIRECTION OUTPUT ;
    USE SIGNAL ;
    SHAPE ABUTMENT ;
    PORT
      LAYER metal3 ;
      RECT 0.000 49.245 0.070 49.315 ;
    END
  END R0_data[161]
  PIN R0_data[162]
    DIRECTION OUTPUT ;
    USE SIGNAL ;
    SHAPE ABUTMENT ;
    PORT
      LAYER metal3 ;
      RECT 0.000 49.525 0.070 49.595 ;
    END
  END R0_data[162]
  PIN R0_data[163]
    DIRECTION OUTPUT ;
    USE SIGNAL ;
    SHAPE ABUTMENT ;
    PORT
      LAYER metal3 ;
      RECT 0.000 49.805 0.070 49.875 ;
    END
  END R0_data[163]
  PIN R0_data[164]
    DIRECTION OUTPUT ;
    USE SIGNAL ;
    SHAPE ABUTMENT ;
    PORT
      LAYER metal3 ;
      RECT 0.000 50.085 0.070 50.155 ;
    END
  END R0_data[164]
  PIN R0_data[165]
    DIRECTION OUTPUT ;
    USE SIGNAL ;
    SHAPE ABUTMENT ;
    PORT
      LAYER metal3 ;
      RECT 0.000 50.365 0.070 50.435 ;
    END
  END R0_data[165]
  PIN R0_data[166]
    DIRECTION OUTPUT ;
    USE SIGNAL ;
    SHAPE ABUTMENT ;
    PORT
      LAYER metal3 ;
      RECT 0.000 50.645 0.070 50.715 ;
    END
  END R0_data[166]
  PIN R0_data[167]
    DIRECTION OUTPUT ;
    USE SIGNAL ;
    SHAPE ABUTMENT ;
    PORT
      LAYER metal3 ;
      RECT 0.000 50.925 0.070 50.995 ;
    END
  END R0_data[167]
  PIN R0_data[168]
    DIRECTION OUTPUT ;
    USE SIGNAL ;
    SHAPE ABUTMENT ;
    PORT
      LAYER metal3 ;
      RECT 0.000 51.205 0.070 51.275 ;
    END
  END R0_data[168]
  PIN R0_data[169]
    DIRECTION OUTPUT ;
    USE SIGNAL ;
    SHAPE ABUTMENT ;
    PORT
      LAYER metal3 ;
      RECT 0.000 51.485 0.070 51.555 ;
    END
  END R0_data[169]
  PIN R0_data[170]
    DIRECTION OUTPUT ;
    USE SIGNAL ;
    SHAPE ABUTMENT ;
    PORT
      LAYER metal3 ;
      RECT 0.000 51.765 0.070 51.835 ;
    END
  END R0_data[170]
  PIN R0_data[171]
    DIRECTION OUTPUT ;
    USE SIGNAL ;
    SHAPE ABUTMENT ;
    PORT
      LAYER metal3 ;
      RECT 0.000 52.045 0.070 52.115 ;
    END
  END R0_data[171]
  PIN R0_data[172]
    DIRECTION OUTPUT ;
    USE SIGNAL ;
    SHAPE ABUTMENT ;
    PORT
      LAYER metal3 ;
      RECT 0.000 52.325 0.070 52.395 ;
    END
  END R0_data[172]
  PIN R0_data[173]
    DIRECTION OUTPUT ;
    USE SIGNAL ;
    SHAPE ABUTMENT ;
    PORT
      LAYER metal3 ;
      RECT 0.000 52.605 0.070 52.675 ;
    END
  END R0_data[173]
  PIN R0_data[174]
    DIRECTION OUTPUT ;
    USE SIGNAL ;
    SHAPE ABUTMENT ;
    PORT
      LAYER metal3 ;
      RECT 0.000 52.885 0.070 52.955 ;
    END
  END R0_data[174]
  PIN R0_data[175]
    DIRECTION OUTPUT ;
    USE SIGNAL ;
    SHAPE ABUTMENT ;
    PORT
      LAYER metal3 ;
      RECT 0.000 53.165 0.070 53.235 ;
    END
  END R0_data[175]
  PIN R0_data[176]
    DIRECTION OUTPUT ;
    USE SIGNAL ;
    SHAPE ABUTMENT ;
    PORT
      LAYER metal3 ;
      RECT 0.000 53.445 0.070 53.515 ;
    END
  END R0_data[176]
  PIN R0_data[177]
    DIRECTION OUTPUT ;
    USE SIGNAL ;
    SHAPE ABUTMENT ;
    PORT
      LAYER metal3 ;
      RECT 0.000 53.725 0.070 53.795 ;
    END
  END R0_data[177]
  PIN R0_data[178]
    DIRECTION OUTPUT ;
    USE SIGNAL ;
    SHAPE ABUTMENT ;
    PORT
      LAYER metal3 ;
      RECT 0.000 54.005 0.070 54.075 ;
    END
  END R0_data[178]
  PIN R0_data[179]
    DIRECTION OUTPUT ;
    USE SIGNAL ;
    SHAPE ABUTMENT ;
    PORT
      LAYER metal3 ;
      RECT 0.000 54.285 0.070 54.355 ;
    END
  END R0_data[179]
  PIN R0_data[180]
    DIRECTION OUTPUT ;
    USE SIGNAL ;
    SHAPE ABUTMENT ;
    PORT
      LAYER metal3 ;
      RECT 0.000 54.565 0.070 54.635 ;
    END
  END R0_data[180]
  PIN R0_data[181]
    DIRECTION OUTPUT ;
    USE SIGNAL ;
    SHAPE ABUTMENT ;
    PORT
      LAYER metal3 ;
      RECT 0.000 54.845 0.070 54.915 ;
    END
  END R0_data[181]
  PIN R0_data[182]
    DIRECTION OUTPUT ;
    USE SIGNAL ;
    SHAPE ABUTMENT ;
    PORT
      LAYER metal3 ;
      RECT 0.000 55.125 0.070 55.195 ;
    END
  END R0_data[182]
  PIN R0_data[183]
    DIRECTION OUTPUT ;
    USE SIGNAL ;
    SHAPE ABUTMENT ;
    PORT
      LAYER metal3 ;
      RECT 0.000 55.405 0.070 55.475 ;
    END
  END R0_data[183]
  PIN R0_data[184]
    DIRECTION OUTPUT ;
    USE SIGNAL ;
    SHAPE ABUTMENT ;
    PORT
      LAYER metal3 ;
      RECT 0.000 55.685 0.070 55.755 ;
    END
  END R0_data[184]
  PIN R0_data[185]
    DIRECTION OUTPUT ;
    USE SIGNAL ;
    SHAPE ABUTMENT ;
    PORT
      LAYER metal3 ;
      RECT 0.000 55.965 0.070 56.035 ;
    END
  END R0_data[185]
  PIN R0_data[186]
    DIRECTION OUTPUT ;
    USE SIGNAL ;
    SHAPE ABUTMENT ;
    PORT
      LAYER metal3 ;
      RECT 0.000 56.245 0.070 56.315 ;
    END
  END R0_data[186]
  PIN R0_data[187]
    DIRECTION OUTPUT ;
    USE SIGNAL ;
    SHAPE ABUTMENT ;
    PORT
      LAYER metal3 ;
      RECT 0.000 56.525 0.070 56.595 ;
    END
  END R0_data[187]
  PIN R0_data[188]
    DIRECTION OUTPUT ;
    USE SIGNAL ;
    SHAPE ABUTMENT ;
    PORT
      LAYER metal3 ;
      RECT 0.000 56.805 0.070 56.875 ;
    END
  END R0_data[188]
  PIN R0_data[189]
    DIRECTION OUTPUT ;
    USE SIGNAL ;
    SHAPE ABUTMENT ;
    PORT
      LAYER metal3 ;
      RECT 0.000 57.085 0.070 57.155 ;
    END
  END R0_data[189]
  PIN R0_data[190]
    DIRECTION OUTPUT ;
    USE SIGNAL ;
    SHAPE ABUTMENT ;
    PORT
      LAYER metal3 ;
      RECT 0.000 57.365 0.070 57.435 ;
    END
  END R0_data[190]
  PIN R0_data[191]
    DIRECTION OUTPUT ;
    USE SIGNAL ;
    SHAPE ABUTMENT ;
    PORT
      LAYER metal3 ;
      RECT 0.000 57.645 0.070 57.715 ;
    END
  END R0_data[191]
  PIN R0_data[192]
    DIRECTION OUTPUT ;
    USE SIGNAL ;
    SHAPE ABUTMENT ;
    PORT
      LAYER metal3 ;
      RECT 0.000 57.925 0.070 57.995 ;
    END
  END R0_data[192]
  PIN R0_data[193]
    DIRECTION OUTPUT ;
    USE SIGNAL ;
    SHAPE ABUTMENT ;
    PORT
      LAYER metal3 ;
      RECT 0.000 58.205 0.070 58.275 ;
    END
  END R0_data[193]
  PIN R0_data[194]
    DIRECTION OUTPUT ;
    USE SIGNAL ;
    SHAPE ABUTMENT ;
    PORT
      LAYER metal3 ;
      RECT 0.000 58.485 0.070 58.555 ;
    END
  END R0_data[194]
  PIN R0_data[195]
    DIRECTION OUTPUT ;
    USE SIGNAL ;
    SHAPE ABUTMENT ;
    PORT
      LAYER metal3 ;
      RECT 0.000 58.765 0.070 58.835 ;
    END
  END R0_data[195]
  PIN R0_data[196]
    DIRECTION OUTPUT ;
    USE SIGNAL ;
    SHAPE ABUTMENT ;
    PORT
      LAYER metal3 ;
      RECT 0.000 59.045 0.070 59.115 ;
    END
  END R0_data[196]
  PIN R0_data[197]
    DIRECTION OUTPUT ;
    USE SIGNAL ;
    SHAPE ABUTMENT ;
    PORT
      LAYER metal3 ;
      RECT 0.000 59.325 0.070 59.395 ;
    END
  END R0_data[197]
  PIN R0_data[198]
    DIRECTION OUTPUT ;
    USE SIGNAL ;
    SHAPE ABUTMENT ;
    PORT
      LAYER metal3 ;
      RECT 0.000 59.605 0.070 59.675 ;
    END
  END R0_data[198]
  PIN R0_data[199]
    DIRECTION OUTPUT ;
    USE SIGNAL ;
    SHAPE ABUTMENT ;
    PORT
      LAYER metal3 ;
      RECT 0.000 59.885 0.070 59.955 ;
    END
  END R0_data[199]
  PIN R0_data[200]
    DIRECTION OUTPUT ;
    USE SIGNAL ;
    SHAPE ABUTMENT ;
    PORT
      LAYER metal3 ;
      RECT 0.000 60.165 0.070 60.235 ;
    END
  END R0_data[200]
  PIN R0_data[201]
    DIRECTION OUTPUT ;
    USE SIGNAL ;
    SHAPE ABUTMENT ;
    PORT
      LAYER metal3 ;
      RECT 0.000 60.445 0.070 60.515 ;
    END
  END R0_data[201]
  PIN R0_data[202]
    DIRECTION OUTPUT ;
    USE SIGNAL ;
    SHAPE ABUTMENT ;
    PORT
      LAYER metal3 ;
      RECT 0.000 60.725 0.070 60.795 ;
    END
  END R0_data[202]
  PIN R0_data[203]
    DIRECTION OUTPUT ;
    USE SIGNAL ;
    SHAPE ABUTMENT ;
    PORT
      LAYER metal3 ;
      RECT 0.000 61.005 0.070 61.075 ;
    END
  END R0_data[203]
  PIN R0_data[204]
    DIRECTION OUTPUT ;
    USE SIGNAL ;
    SHAPE ABUTMENT ;
    PORT
      LAYER metal3 ;
      RECT 0.000 61.285 0.070 61.355 ;
    END
  END R0_data[204]
  PIN R0_data[205]
    DIRECTION OUTPUT ;
    USE SIGNAL ;
    SHAPE ABUTMENT ;
    PORT
      LAYER metal3 ;
      RECT 0.000 61.565 0.070 61.635 ;
    END
  END R0_data[205]
  PIN R0_data[206]
    DIRECTION OUTPUT ;
    USE SIGNAL ;
    SHAPE ABUTMENT ;
    PORT
      LAYER metal3 ;
      RECT 0.000 61.845 0.070 61.915 ;
    END
  END R0_data[206]
  PIN R0_data[207]
    DIRECTION OUTPUT ;
    USE SIGNAL ;
    SHAPE ABUTMENT ;
    PORT
      LAYER metal3 ;
      RECT 0.000 62.125 0.070 62.195 ;
    END
  END R0_data[207]
  PIN R0_data[208]
    DIRECTION OUTPUT ;
    USE SIGNAL ;
    SHAPE ABUTMENT ;
    PORT
      LAYER metal3 ;
      RECT 0.000 62.405 0.070 62.475 ;
    END
  END R0_data[208]
  PIN R0_data[209]
    DIRECTION OUTPUT ;
    USE SIGNAL ;
    SHAPE ABUTMENT ;
    PORT
      LAYER metal3 ;
      RECT 0.000 62.685 0.070 62.755 ;
    END
  END R0_data[209]
  PIN R0_data[210]
    DIRECTION OUTPUT ;
    USE SIGNAL ;
    SHAPE ABUTMENT ;
    PORT
      LAYER metal3 ;
      RECT 0.000 62.965 0.070 63.035 ;
    END
  END R0_data[210]
  PIN R0_data[211]
    DIRECTION OUTPUT ;
    USE SIGNAL ;
    SHAPE ABUTMENT ;
    PORT
      LAYER metal3 ;
      RECT 0.000 63.245 0.070 63.315 ;
    END
  END R0_data[211]
  PIN R0_data[212]
    DIRECTION OUTPUT ;
    USE SIGNAL ;
    SHAPE ABUTMENT ;
    PORT
      LAYER metal3 ;
      RECT 0.000 63.525 0.070 63.595 ;
    END
  END R0_data[212]
  PIN R0_data[213]
    DIRECTION OUTPUT ;
    USE SIGNAL ;
    SHAPE ABUTMENT ;
    PORT
      LAYER metal3 ;
      RECT 0.000 63.805 0.070 63.875 ;
    END
  END R0_data[213]
  PIN R0_data[214]
    DIRECTION OUTPUT ;
    USE SIGNAL ;
    SHAPE ABUTMENT ;
    PORT
      LAYER metal3 ;
      RECT 0.000 64.085 0.070 64.155 ;
    END
  END R0_data[214]
  PIN R0_data[215]
    DIRECTION OUTPUT ;
    USE SIGNAL ;
    SHAPE ABUTMENT ;
    PORT
      LAYER metal3 ;
      RECT 0.000 64.365 0.070 64.435 ;
    END
  END R0_data[215]
  PIN R0_data[216]
    DIRECTION OUTPUT ;
    USE SIGNAL ;
    SHAPE ABUTMENT ;
    PORT
      LAYER metal3 ;
      RECT 0.000 64.645 0.070 64.715 ;
    END
  END R0_data[216]
  PIN R0_data[217]
    DIRECTION OUTPUT ;
    USE SIGNAL ;
    SHAPE ABUTMENT ;
    PORT
      LAYER metal3 ;
      RECT 0.000 64.925 0.070 64.995 ;
    END
  END R0_data[217]
  PIN R0_data[218]
    DIRECTION OUTPUT ;
    USE SIGNAL ;
    SHAPE ABUTMENT ;
    PORT
      LAYER metal3 ;
      RECT 0.000 65.205 0.070 65.275 ;
    END
  END R0_data[218]
  PIN R0_data[219]
    DIRECTION OUTPUT ;
    USE SIGNAL ;
    SHAPE ABUTMENT ;
    PORT
      LAYER metal3 ;
      RECT 0.000 65.485 0.070 65.555 ;
    END
  END R0_data[219]
  PIN R0_data[220]
    DIRECTION OUTPUT ;
    USE SIGNAL ;
    SHAPE ABUTMENT ;
    PORT
      LAYER metal3 ;
      RECT 0.000 65.765 0.070 65.835 ;
    END
  END R0_data[220]
  PIN R0_data[221]
    DIRECTION OUTPUT ;
    USE SIGNAL ;
    SHAPE ABUTMENT ;
    PORT
      LAYER metal3 ;
      RECT 0.000 66.045 0.070 66.115 ;
    END
  END R0_data[221]
  PIN R0_data[222]
    DIRECTION OUTPUT ;
    USE SIGNAL ;
    SHAPE ABUTMENT ;
    PORT
      LAYER metal3 ;
      RECT 0.000 66.325 0.070 66.395 ;
    END
  END R0_data[222]
  PIN R0_data[223]
    DIRECTION OUTPUT ;
    USE SIGNAL ;
    SHAPE ABUTMENT ;
    PORT
      LAYER metal3 ;
      RECT 0.000 66.605 0.070 66.675 ;
    END
  END R0_data[223]
  PIN R0_data[224]
    DIRECTION OUTPUT ;
    USE SIGNAL ;
    SHAPE ABUTMENT ;
    PORT
      LAYER metal3 ;
      RECT 0.000 66.885 0.070 66.955 ;
    END
  END R0_data[224]
  PIN R0_data[225]
    DIRECTION OUTPUT ;
    USE SIGNAL ;
    SHAPE ABUTMENT ;
    PORT
      LAYER metal3 ;
      RECT 0.000 67.165 0.070 67.235 ;
    END
  END R0_data[225]
  PIN R0_data[226]
    DIRECTION OUTPUT ;
    USE SIGNAL ;
    SHAPE ABUTMENT ;
    PORT
      LAYER metal3 ;
      RECT 0.000 67.445 0.070 67.515 ;
    END
  END R0_data[226]
  PIN R0_data[227]
    DIRECTION OUTPUT ;
    USE SIGNAL ;
    SHAPE ABUTMENT ;
    PORT
      LAYER metal3 ;
      RECT 0.000 67.725 0.070 67.795 ;
    END
  END R0_data[227]
  PIN R0_data[228]
    DIRECTION OUTPUT ;
    USE SIGNAL ;
    SHAPE ABUTMENT ;
    PORT
      LAYER metal3 ;
      RECT 0.000 68.005 0.070 68.075 ;
    END
  END R0_data[228]
  PIN R0_data[229]
    DIRECTION OUTPUT ;
    USE SIGNAL ;
    SHAPE ABUTMENT ;
    PORT
      LAYER metal3 ;
      RECT 0.000 68.285 0.070 68.355 ;
    END
  END R0_data[229]
  PIN R0_data[230]
    DIRECTION OUTPUT ;
    USE SIGNAL ;
    SHAPE ABUTMENT ;
    PORT
      LAYER metal3 ;
      RECT 0.000 68.565 0.070 68.635 ;
    END
  END R0_data[230]
  PIN R0_data[231]
    DIRECTION OUTPUT ;
    USE SIGNAL ;
    SHAPE ABUTMENT ;
    PORT
      LAYER metal3 ;
      RECT 0.000 68.845 0.070 68.915 ;
    END
  END R0_data[231]
  PIN R0_data[232]
    DIRECTION OUTPUT ;
    USE SIGNAL ;
    SHAPE ABUTMENT ;
    PORT
      LAYER metal3 ;
      RECT 0.000 69.125 0.070 69.195 ;
    END
  END R0_data[232]
  PIN R0_data[233]
    DIRECTION OUTPUT ;
    USE SIGNAL ;
    SHAPE ABUTMENT ;
    PORT
      LAYER metal3 ;
      RECT 0.000 69.405 0.070 69.475 ;
    END
  END R0_data[233]
  PIN R0_data[234]
    DIRECTION OUTPUT ;
    USE SIGNAL ;
    SHAPE ABUTMENT ;
    PORT
      LAYER metal3 ;
      RECT 0.000 69.685 0.070 69.755 ;
    END
  END R0_data[234]
  PIN R0_data[235]
    DIRECTION OUTPUT ;
    USE SIGNAL ;
    SHAPE ABUTMENT ;
    PORT
      LAYER metal3 ;
      RECT 0.000 69.965 0.070 70.035 ;
    END
  END R0_data[235]
  PIN R0_data[236]
    DIRECTION OUTPUT ;
    USE SIGNAL ;
    SHAPE ABUTMENT ;
    PORT
      LAYER metal3 ;
      RECT 0.000 70.245 0.070 70.315 ;
    END
  END R0_data[236]
  PIN R0_data[237]
    DIRECTION OUTPUT ;
    USE SIGNAL ;
    SHAPE ABUTMENT ;
    PORT
      LAYER metal3 ;
      RECT 0.000 70.525 0.070 70.595 ;
    END
  END R0_data[237]
  PIN R0_data[238]
    DIRECTION OUTPUT ;
    USE SIGNAL ;
    SHAPE ABUTMENT ;
    PORT
      LAYER metal3 ;
      RECT 0.000 70.805 0.070 70.875 ;
    END
  END R0_data[238]
  PIN R0_data[239]
    DIRECTION OUTPUT ;
    USE SIGNAL ;
    SHAPE ABUTMENT ;
    PORT
      LAYER metal3 ;
      RECT 0.000 71.085 0.070 71.155 ;
    END
  END R0_data[239]
  PIN R0_data[240]
    DIRECTION OUTPUT ;
    USE SIGNAL ;
    SHAPE ABUTMENT ;
    PORT
      LAYER metal3 ;
      RECT 0.000 71.365 0.070 71.435 ;
    END
  END R0_data[240]
  PIN R0_data[241]
    DIRECTION OUTPUT ;
    USE SIGNAL ;
    SHAPE ABUTMENT ;
    PORT
      LAYER metal3 ;
      RECT 0.000 71.645 0.070 71.715 ;
    END
  END R0_data[241]
  PIN R0_data[242]
    DIRECTION OUTPUT ;
    USE SIGNAL ;
    SHAPE ABUTMENT ;
    PORT
      LAYER metal3 ;
      RECT 0.000 71.925 0.070 71.995 ;
    END
  END R0_data[242]
  PIN R0_data[243]
    DIRECTION OUTPUT ;
    USE SIGNAL ;
    SHAPE ABUTMENT ;
    PORT
      LAYER metal3 ;
      RECT 0.000 72.205 0.070 72.275 ;
    END
  END R0_data[243]
  PIN R0_data[244]
    DIRECTION OUTPUT ;
    USE SIGNAL ;
    SHAPE ABUTMENT ;
    PORT
      LAYER metal3 ;
      RECT 0.000 72.485 0.070 72.555 ;
    END
  END R0_data[244]
  PIN R0_data[245]
    DIRECTION OUTPUT ;
    USE SIGNAL ;
    SHAPE ABUTMENT ;
    PORT
      LAYER metal3 ;
      RECT 0.000 72.765 0.070 72.835 ;
    END
  END R0_data[245]
  PIN R0_data[246]
    DIRECTION OUTPUT ;
    USE SIGNAL ;
    SHAPE ABUTMENT ;
    PORT
      LAYER metal3 ;
      RECT 0.000 73.045 0.070 73.115 ;
    END
  END R0_data[246]
  PIN R0_data[247]
    DIRECTION OUTPUT ;
    USE SIGNAL ;
    SHAPE ABUTMENT ;
    PORT
      LAYER metal3 ;
      RECT 0.000 73.325 0.070 73.395 ;
    END
  END R0_data[247]
  PIN R0_data[248]
    DIRECTION OUTPUT ;
    USE SIGNAL ;
    SHAPE ABUTMENT ;
    PORT
      LAYER metal3 ;
      RECT 0.000 73.605 0.070 73.675 ;
    END
  END R0_data[248]
  PIN R0_data[249]
    DIRECTION OUTPUT ;
    USE SIGNAL ;
    SHAPE ABUTMENT ;
    PORT
      LAYER metal3 ;
      RECT 0.000 73.885 0.070 73.955 ;
    END
  END R0_data[249]
  PIN R0_data[250]
    DIRECTION OUTPUT ;
    USE SIGNAL ;
    SHAPE ABUTMENT ;
    PORT
      LAYER metal3 ;
      RECT 0.000 74.165 0.070 74.235 ;
    END
  END R0_data[250]
  PIN R0_data[251]
    DIRECTION OUTPUT ;
    USE SIGNAL ;
    SHAPE ABUTMENT ;
    PORT
      LAYER metal3 ;
      RECT 0.000 74.445 0.070 74.515 ;
    END
  END R0_data[251]
  PIN R0_data[252]
    DIRECTION OUTPUT ;
    USE SIGNAL ;
    SHAPE ABUTMENT ;
    PORT
      LAYER metal3 ;
      RECT 0.000 74.725 0.070 74.795 ;
    END
  END R0_data[252]
  PIN R0_data[253]
    DIRECTION OUTPUT ;
    USE SIGNAL ;
    SHAPE ABUTMENT ;
    PORT
      LAYER metal3 ;
      RECT 0.000 75.005 0.070 75.075 ;
    END
  END R0_data[253]
  PIN R0_data[254]
    DIRECTION OUTPUT ;
    USE SIGNAL ;
    SHAPE ABUTMENT ;
    PORT
      LAYER metal3 ;
      RECT 0.000 75.285 0.070 75.355 ;
    END
  END R0_data[254]
  PIN R0_data[255]
    DIRECTION OUTPUT ;
    USE SIGNAL ;
    SHAPE ABUTMENT ;
    PORT
      LAYER metal3 ;
      RECT 0.000 75.565 0.070 75.635 ;
    END
  END R0_data[255]
  PIN R0_data[256]
    DIRECTION OUTPUT ;
    USE SIGNAL ;
    SHAPE ABUTMENT ;
    PORT
      LAYER metal3 ;
      RECT 0.000 75.845 0.070 75.915 ;
    END
  END R0_data[256]
  PIN R0_data[257]
    DIRECTION OUTPUT ;
    USE SIGNAL ;
    SHAPE ABUTMENT ;
    PORT
      LAYER metal3 ;
      RECT 0.000 76.125 0.070 76.195 ;
    END
  END R0_data[257]
  PIN R0_data[258]
    DIRECTION OUTPUT ;
    USE SIGNAL ;
    SHAPE ABUTMENT ;
    PORT
      LAYER metal3 ;
      RECT 0.000 76.405 0.070 76.475 ;
    END
  END R0_data[258]
  PIN R0_data[259]
    DIRECTION OUTPUT ;
    USE SIGNAL ;
    SHAPE ABUTMENT ;
    PORT
      LAYER metal3 ;
      RECT 0.000 76.685 0.070 76.755 ;
    END
  END R0_data[259]
  PIN R0_data[260]
    DIRECTION OUTPUT ;
    USE SIGNAL ;
    SHAPE ABUTMENT ;
    PORT
      LAYER metal3 ;
      RECT 0.000 76.965 0.070 77.035 ;
    END
  END R0_data[260]
  PIN R0_data[261]
    DIRECTION OUTPUT ;
    USE SIGNAL ;
    SHAPE ABUTMENT ;
    PORT
      LAYER metal3 ;
      RECT 0.000 77.245 0.070 77.315 ;
    END
  END R0_data[261]
  PIN R0_data[262]
    DIRECTION OUTPUT ;
    USE SIGNAL ;
    SHAPE ABUTMENT ;
    PORT
      LAYER metal3 ;
      RECT 0.000 77.525 0.070 77.595 ;
    END
  END R0_data[262]
  PIN R0_data[263]
    DIRECTION OUTPUT ;
    USE SIGNAL ;
    SHAPE ABUTMENT ;
    PORT
      LAYER metal3 ;
      RECT 0.000 77.805 0.070 77.875 ;
    END
  END R0_data[263]
  PIN R0_data[264]
    DIRECTION OUTPUT ;
    USE SIGNAL ;
    SHAPE ABUTMENT ;
    PORT
      LAYER metal3 ;
      RECT 0.000 78.085 0.070 78.155 ;
    END
  END R0_data[264]
  PIN R0_data[265]
    DIRECTION OUTPUT ;
    USE SIGNAL ;
    SHAPE ABUTMENT ;
    PORT
      LAYER metal3 ;
      RECT 0.000 78.365 0.070 78.435 ;
    END
  END R0_data[265]
  PIN R0_data[266]
    DIRECTION OUTPUT ;
    USE SIGNAL ;
    SHAPE ABUTMENT ;
    PORT
      LAYER metal3 ;
      RECT 0.000 78.645 0.070 78.715 ;
    END
  END R0_data[266]
  PIN R0_data[267]
    DIRECTION OUTPUT ;
    USE SIGNAL ;
    SHAPE ABUTMENT ;
    PORT
      LAYER metal3 ;
      RECT 0.000 78.925 0.070 78.995 ;
    END
  END R0_data[267]
  PIN R0_data[268]
    DIRECTION OUTPUT ;
    USE SIGNAL ;
    SHAPE ABUTMENT ;
    PORT
      LAYER metal3 ;
      RECT 0.000 79.205 0.070 79.275 ;
    END
  END R0_data[268]
  PIN R0_data[269]
    DIRECTION OUTPUT ;
    USE SIGNAL ;
    SHAPE ABUTMENT ;
    PORT
      LAYER metal3 ;
      RECT 0.000 79.485 0.070 79.555 ;
    END
  END R0_data[269]
  PIN R0_data[270]
    DIRECTION OUTPUT ;
    USE SIGNAL ;
    SHAPE ABUTMENT ;
    PORT
      LAYER metal3 ;
      RECT 0.000 79.765 0.070 79.835 ;
    END
  END R0_data[270]
  PIN R0_data[271]
    DIRECTION OUTPUT ;
    USE SIGNAL ;
    SHAPE ABUTMENT ;
    PORT
      LAYER metal3 ;
      RECT 0.000 80.045 0.070 80.115 ;
    END
  END R0_data[271]
  PIN R0_data[272]
    DIRECTION OUTPUT ;
    USE SIGNAL ;
    SHAPE ABUTMENT ;
    PORT
      LAYER metal3 ;
      RECT 0.000 80.325 0.070 80.395 ;
    END
  END R0_data[272]
  PIN R0_data[273]
    DIRECTION OUTPUT ;
    USE SIGNAL ;
    SHAPE ABUTMENT ;
    PORT
      LAYER metal3 ;
      RECT 0.000 80.605 0.070 80.675 ;
    END
  END R0_data[273]
  PIN R0_data[274]
    DIRECTION OUTPUT ;
    USE SIGNAL ;
    SHAPE ABUTMENT ;
    PORT
      LAYER metal3 ;
      RECT 0.000 80.885 0.070 80.955 ;
    END
  END R0_data[274]
  PIN R0_data[275]
    DIRECTION OUTPUT ;
    USE SIGNAL ;
    SHAPE ABUTMENT ;
    PORT
      LAYER metal3 ;
      RECT 0.000 81.165 0.070 81.235 ;
    END
  END R0_data[275]
  PIN R0_data[276]
    DIRECTION OUTPUT ;
    USE SIGNAL ;
    SHAPE ABUTMENT ;
    PORT
      LAYER metal3 ;
      RECT 0.000 81.445 0.070 81.515 ;
    END
  END R0_data[276]
  PIN R0_data[277]
    DIRECTION OUTPUT ;
    USE SIGNAL ;
    SHAPE ABUTMENT ;
    PORT
      LAYER metal3 ;
      RECT 0.000 81.725 0.070 81.795 ;
    END
  END R0_data[277]
  PIN R0_data[278]
    DIRECTION OUTPUT ;
    USE SIGNAL ;
    SHAPE ABUTMENT ;
    PORT
      LAYER metal3 ;
      RECT 0.000 82.005 0.070 82.075 ;
    END
  END R0_data[278]
  PIN R0_data[279]
    DIRECTION OUTPUT ;
    USE SIGNAL ;
    SHAPE ABUTMENT ;
    PORT
      LAYER metal3 ;
      RECT 0.000 82.285 0.070 82.355 ;
    END
  END R0_data[279]
  PIN R0_data[280]
    DIRECTION OUTPUT ;
    USE SIGNAL ;
    SHAPE ABUTMENT ;
    PORT
      LAYER metal3 ;
      RECT 0.000 82.565 0.070 82.635 ;
    END
  END R0_data[280]
  PIN R0_data[281]
    DIRECTION OUTPUT ;
    USE SIGNAL ;
    SHAPE ABUTMENT ;
    PORT
      LAYER metal3 ;
      RECT 0.000 82.845 0.070 82.915 ;
    END
  END R0_data[281]
  PIN R0_data[282]
    DIRECTION OUTPUT ;
    USE SIGNAL ;
    SHAPE ABUTMENT ;
    PORT
      LAYER metal3 ;
      RECT 0.000 83.125 0.070 83.195 ;
    END
  END R0_data[282]
  PIN R0_data[283]
    DIRECTION OUTPUT ;
    USE SIGNAL ;
    SHAPE ABUTMENT ;
    PORT
      LAYER metal3 ;
      RECT 0.000 83.405 0.070 83.475 ;
    END
  END R0_data[283]
  PIN R0_data[284]
    DIRECTION OUTPUT ;
    USE SIGNAL ;
    SHAPE ABUTMENT ;
    PORT
      LAYER metal3 ;
      RECT 0.000 83.685 0.070 83.755 ;
    END
  END R0_data[284]
  PIN R0_data[285]
    DIRECTION OUTPUT ;
    USE SIGNAL ;
    SHAPE ABUTMENT ;
    PORT
      LAYER metal3 ;
      RECT 0.000 83.965 0.070 84.035 ;
    END
  END R0_data[285]
  PIN R0_data[286]
    DIRECTION OUTPUT ;
    USE SIGNAL ;
    SHAPE ABUTMENT ;
    PORT
      LAYER metal3 ;
      RECT 0.000 84.245 0.070 84.315 ;
    END
  END R0_data[286]
  PIN R0_data[287]
    DIRECTION OUTPUT ;
    USE SIGNAL ;
    SHAPE ABUTMENT ;
    PORT
      LAYER metal3 ;
      RECT 0.000 84.525 0.070 84.595 ;
    END
  END R0_data[287]
  PIN R0_data[288]
    DIRECTION OUTPUT ;
    USE SIGNAL ;
    SHAPE ABUTMENT ;
    PORT
      LAYER metal3 ;
      RECT 0.000 84.805 0.070 84.875 ;
    END
  END R0_data[288]
  PIN R0_data[289]
    DIRECTION OUTPUT ;
    USE SIGNAL ;
    SHAPE ABUTMENT ;
    PORT
      LAYER metal3 ;
      RECT 0.000 85.085 0.070 85.155 ;
    END
  END R0_data[289]
  PIN R0_data[290]
    DIRECTION OUTPUT ;
    USE SIGNAL ;
    SHAPE ABUTMENT ;
    PORT
      LAYER metal3 ;
      RECT 0.000 85.365 0.070 85.435 ;
    END
  END R0_data[290]
  PIN R0_data[291]
    DIRECTION OUTPUT ;
    USE SIGNAL ;
    SHAPE ABUTMENT ;
    PORT
      LAYER metal3 ;
      RECT 0.000 85.645 0.070 85.715 ;
    END
  END R0_data[291]
  PIN R0_data[292]
    DIRECTION OUTPUT ;
    USE SIGNAL ;
    SHAPE ABUTMENT ;
    PORT
      LAYER metal3 ;
      RECT 0.000 85.925 0.070 85.995 ;
    END
  END R0_data[292]
  PIN R0_data[293]
    DIRECTION OUTPUT ;
    USE SIGNAL ;
    SHAPE ABUTMENT ;
    PORT
      LAYER metal3 ;
      RECT 0.000 86.205 0.070 86.275 ;
    END
  END R0_data[293]
  PIN R0_data[294]
    DIRECTION OUTPUT ;
    USE SIGNAL ;
    SHAPE ABUTMENT ;
    PORT
      LAYER metal3 ;
      RECT 0.000 86.485 0.070 86.555 ;
    END
  END R0_data[294]
  PIN R0_data[295]
    DIRECTION OUTPUT ;
    USE SIGNAL ;
    SHAPE ABUTMENT ;
    PORT
      LAYER metal3 ;
      RECT 0.000 86.765 0.070 86.835 ;
    END
  END R0_data[295]
  PIN R0_data[296]
    DIRECTION OUTPUT ;
    USE SIGNAL ;
    SHAPE ABUTMENT ;
    PORT
      LAYER metal3 ;
      RECT 0.000 87.045 0.070 87.115 ;
    END
  END R0_data[296]
  PIN R0_data[297]
    DIRECTION OUTPUT ;
    USE SIGNAL ;
    SHAPE ABUTMENT ;
    PORT
      LAYER metal3 ;
      RECT 0.000 87.325 0.070 87.395 ;
    END
  END R0_data[297]
  PIN R0_data[298]
    DIRECTION OUTPUT ;
    USE SIGNAL ;
    SHAPE ABUTMENT ;
    PORT
      LAYER metal3 ;
      RECT 0.000 87.605 0.070 87.675 ;
    END
  END R0_data[298]
  PIN R0_data[299]
    DIRECTION OUTPUT ;
    USE SIGNAL ;
    SHAPE ABUTMENT ;
    PORT
      LAYER metal3 ;
      RECT 0.000 87.885 0.070 87.955 ;
    END
  END R0_data[299]
  PIN R0_data[300]
    DIRECTION OUTPUT ;
    USE SIGNAL ;
    SHAPE ABUTMENT ;
    PORT
      LAYER metal3 ;
      RECT 0.000 88.165 0.070 88.235 ;
    END
  END R0_data[300]
  PIN R0_data[301]
    DIRECTION OUTPUT ;
    USE SIGNAL ;
    SHAPE ABUTMENT ;
    PORT
      LAYER metal3 ;
      RECT 0.000 88.445 0.070 88.515 ;
    END
  END R0_data[301]
  PIN R0_data[302]
    DIRECTION OUTPUT ;
    USE SIGNAL ;
    SHAPE ABUTMENT ;
    PORT
      LAYER metal3 ;
      RECT 0.000 88.725 0.070 88.795 ;
    END
  END R0_data[302]
  PIN R0_data[303]
    DIRECTION OUTPUT ;
    USE SIGNAL ;
    SHAPE ABUTMENT ;
    PORT
      LAYER metal3 ;
      RECT 0.000 89.005 0.070 89.075 ;
    END
  END R0_data[303]
  PIN R0_data[304]
    DIRECTION OUTPUT ;
    USE SIGNAL ;
    SHAPE ABUTMENT ;
    PORT
      LAYER metal3 ;
      RECT 0.000 89.285 0.070 89.355 ;
    END
  END R0_data[304]
  PIN R0_data[305]
    DIRECTION OUTPUT ;
    USE SIGNAL ;
    SHAPE ABUTMENT ;
    PORT
      LAYER metal3 ;
      RECT 0.000 89.565 0.070 89.635 ;
    END
  END R0_data[305]
  PIN R0_data[306]
    DIRECTION OUTPUT ;
    USE SIGNAL ;
    SHAPE ABUTMENT ;
    PORT
      LAYER metal3 ;
      RECT 0.000 89.845 0.070 89.915 ;
    END
  END R0_data[306]
  PIN R0_data[307]
    DIRECTION OUTPUT ;
    USE SIGNAL ;
    SHAPE ABUTMENT ;
    PORT
      LAYER metal3 ;
      RECT 0.000 90.125 0.070 90.195 ;
    END
  END R0_data[307]
  PIN R0_data[308]
    DIRECTION OUTPUT ;
    USE SIGNAL ;
    SHAPE ABUTMENT ;
    PORT
      LAYER metal3 ;
      RECT 0.000 90.405 0.070 90.475 ;
    END
  END R0_data[308]
  PIN R0_data[309]
    DIRECTION OUTPUT ;
    USE SIGNAL ;
    SHAPE ABUTMENT ;
    PORT
      LAYER metal3 ;
      RECT 0.000 90.685 0.070 90.755 ;
    END
  END R0_data[309]
  PIN R0_data[310]
    DIRECTION OUTPUT ;
    USE SIGNAL ;
    SHAPE ABUTMENT ;
    PORT
      LAYER metal3 ;
      RECT 0.000 90.965 0.070 91.035 ;
    END
  END R0_data[310]
  PIN R0_data[311]
    DIRECTION OUTPUT ;
    USE SIGNAL ;
    SHAPE ABUTMENT ;
    PORT
      LAYER metal3 ;
      RECT 0.000 91.245 0.070 91.315 ;
    END
  END R0_data[311]
  PIN R0_data[312]
    DIRECTION OUTPUT ;
    USE SIGNAL ;
    SHAPE ABUTMENT ;
    PORT
      LAYER metal3 ;
      RECT 0.000 91.525 0.070 91.595 ;
    END
  END R0_data[312]
  PIN R0_data[313]
    DIRECTION OUTPUT ;
    USE SIGNAL ;
    SHAPE ABUTMENT ;
    PORT
      LAYER metal3 ;
      RECT 0.000 91.805 0.070 91.875 ;
    END
  END R0_data[313]
  PIN R0_data[314]
    DIRECTION OUTPUT ;
    USE SIGNAL ;
    SHAPE ABUTMENT ;
    PORT
      LAYER metal3 ;
      RECT 0.000 92.085 0.070 92.155 ;
    END
  END R0_data[314]
  PIN R0_data[315]
    DIRECTION OUTPUT ;
    USE SIGNAL ;
    SHAPE ABUTMENT ;
    PORT
      LAYER metal3 ;
      RECT 0.000 92.365 0.070 92.435 ;
    END
  END R0_data[315]
  PIN R0_data[316]
    DIRECTION OUTPUT ;
    USE SIGNAL ;
    SHAPE ABUTMENT ;
    PORT
      LAYER metal3 ;
      RECT 0.000 92.645 0.070 92.715 ;
    END
  END R0_data[316]
  PIN R0_data[317]
    DIRECTION OUTPUT ;
    USE SIGNAL ;
    SHAPE ABUTMENT ;
    PORT
      LAYER metal3 ;
      RECT 0.000 92.925 0.070 92.995 ;
    END
  END R0_data[317]
  PIN R0_data[318]
    DIRECTION OUTPUT ;
    USE SIGNAL ;
    SHAPE ABUTMENT ;
    PORT
      LAYER metal3 ;
      RECT 0.000 93.205 0.070 93.275 ;
    END
  END R0_data[318]
  PIN R0_data[319]
    DIRECTION OUTPUT ;
    USE SIGNAL ;
    SHAPE ABUTMENT ;
    PORT
      LAYER metal3 ;
      RECT 0.000 93.485 0.070 93.555 ;
    END
  END R0_data[319]
  PIN R0_data[320]
    DIRECTION OUTPUT ;
    USE SIGNAL ;
    SHAPE ABUTMENT ;
    PORT
      LAYER metal3 ;
      RECT 0.000 93.765 0.070 93.835 ;
    END
  END R0_data[320]
  PIN R0_data[321]
    DIRECTION OUTPUT ;
    USE SIGNAL ;
    SHAPE ABUTMENT ;
    PORT
      LAYER metal3 ;
      RECT 0.000 94.045 0.070 94.115 ;
    END
  END R0_data[321]
  PIN R0_data[322]
    DIRECTION OUTPUT ;
    USE SIGNAL ;
    SHAPE ABUTMENT ;
    PORT
      LAYER metal3 ;
      RECT 0.000 94.325 0.070 94.395 ;
    END
  END R0_data[322]
  PIN R0_data[323]
    DIRECTION OUTPUT ;
    USE SIGNAL ;
    SHAPE ABUTMENT ;
    PORT
      LAYER metal3 ;
      RECT 0.000 94.605 0.070 94.675 ;
    END
  END R0_data[323]
  PIN R0_data[324]
    DIRECTION OUTPUT ;
    USE SIGNAL ;
    SHAPE ABUTMENT ;
    PORT
      LAYER metal3 ;
      RECT 0.000 94.885 0.070 94.955 ;
    END
  END R0_data[324]
  PIN R0_data[325]
    DIRECTION OUTPUT ;
    USE SIGNAL ;
    SHAPE ABUTMENT ;
    PORT
      LAYER metal3 ;
      RECT 0.000 95.165 0.070 95.235 ;
    END
  END R0_data[325]
  PIN R0_data[326]
    DIRECTION OUTPUT ;
    USE SIGNAL ;
    SHAPE ABUTMENT ;
    PORT
      LAYER metal3 ;
      RECT 0.000 95.445 0.070 95.515 ;
    END
  END R0_data[326]
  PIN R0_data[327]
    DIRECTION OUTPUT ;
    USE SIGNAL ;
    SHAPE ABUTMENT ;
    PORT
      LAYER metal3 ;
      RECT 0.000 95.725 0.070 95.795 ;
    END
  END R0_data[327]
  PIN R0_data[328]
    DIRECTION OUTPUT ;
    USE SIGNAL ;
    SHAPE ABUTMENT ;
    PORT
      LAYER metal3 ;
      RECT 0.000 96.005 0.070 96.075 ;
    END
  END R0_data[328]
  PIN R0_data[329]
    DIRECTION OUTPUT ;
    USE SIGNAL ;
    SHAPE ABUTMENT ;
    PORT
      LAYER metal3 ;
      RECT 0.000 96.285 0.070 96.355 ;
    END
  END R0_data[329]
  PIN R0_data[330]
    DIRECTION OUTPUT ;
    USE SIGNAL ;
    SHAPE ABUTMENT ;
    PORT
      LAYER metal3 ;
      RECT 0.000 96.565 0.070 96.635 ;
    END
  END R0_data[330]
  PIN R0_data[331]
    DIRECTION OUTPUT ;
    USE SIGNAL ;
    SHAPE ABUTMENT ;
    PORT
      LAYER metal3 ;
      RECT 0.000 96.845 0.070 96.915 ;
    END
  END R0_data[331]
  PIN R0_data[332]
    DIRECTION OUTPUT ;
    USE SIGNAL ;
    SHAPE ABUTMENT ;
    PORT
      LAYER metal3 ;
      RECT 0.000 97.125 0.070 97.195 ;
    END
  END R0_data[332]
  PIN R0_data[333]
    DIRECTION OUTPUT ;
    USE SIGNAL ;
    SHAPE ABUTMENT ;
    PORT
      LAYER metal3 ;
      RECT 0.000 97.405 0.070 97.475 ;
    END
  END R0_data[333]
  PIN R0_data[334]
    DIRECTION OUTPUT ;
    USE SIGNAL ;
    SHAPE ABUTMENT ;
    PORT
      LAYER metal3 ;
      RECT 0.000 97.685 0.070 97.755 ;
    END
  END R0_data[334]
  PIN R0_data[335]
    DIRECTION OUTPUT ;
    USE SIGNAL ;
    SHAPE ABUTMENT ;
    PORT
      LAYER metal3 ;
      RECT 0.000 97.965 0.070 98.035 ;
    END
  END R0_data[335]
  PIN R0_data[336]
    DIRECTION OUTPUT ;
    USE SIGNAL ;
    SHAPE ABUTMENT ;
    PORT
      LAYER metal3 ;
      RECT 0.000 98.245 0.070 98.315 ;
    END
  END R0_data[336]
  PIN R0_data[337]
    DIRECTION OUTPUT ;
    USE SIGNAL ;
    SHAPE ABUTMENT ;
    PORT
      LAYER metal3 ;
      RECT 0.000 98.525 0.070 98.595 ;
    END
  END R0_data[337]
  PIN R0_data[338]
    DIRECTION OUTPUT ;
    USE SIGNAL ;
    SHAPE ABUTMENT ;
    PORT
      LAYER metal3 ;
      RECT 0.000 98.805 0.070 98.875 ;
    END
  END R0_data[338]
  PIN R0_data[339]
    DIRECTION OUTPUT ;
    USE SIGNAL ;
    SHAPE ABUTMENT ;
    PORT
      LAYER metal3 ;
      RECT 0.000 99.085 0.070 99.155 ;
    END
  END R0_data[339]
  PIN R0_data[340]
    DIRECTION OUTPUT ;
    USE SIGNAL ;
    SHAPE ABUTMENT ;
    PORT
      LAYER metal3 ;
      RECT 0.000 99.365 0.070 99.435 ;
    END
  END R0_data[340]
  PIN R0_data[341]
    DIRECTION OUTPUT ;
    USE SIGNAL ;
    SHAPE ABUTMENT ;
    PORT
      LAYER metal3 ;
      RECT 0.000 99.645 0.070 99.715 ;
    END
  END R0_data[341]
  PIN R0_data[342]
    DIRECTION OUTPUT ;
    USE SIGNAL ;
    SHAPE ABUTMENT ;
    PORT
      LAYER metal3 ;
      RECT 0.000 99.925 0.070 99.995 ;
    END
  END R0_data[342]
  PIN R0_data[343]
    DIRECTION OUTPUT ;
    USE SIGNAL ;
    SHAPE ABUTMENT ;
    PORT
      LAYER metal3 ;
      RECT 0.000 100.205 0.070 100.275 ;
    END
  END R0_data[343]
  PIN R0_data[344]
    DIRECTION OUTPUT ;
    USE SIGNAL ;
    SHAPE ABUTMENT ;
    PORT
      LAYER metal3 ;
      RECT 0.000 100.485 0.070 100.555 ;
    END
  END R0_data[344]
  PIN R0_data[345]
    DIRECTION OUTPUT ;
    USE SIGNAL ;
    SHAPE ABUTMENT ;
    PORT
      LAYER metal3 ;
      RECT 0.000 100.765 0.070 100.835 ;
    END
  END R0_data[345]
  PIN R0_data[346]
    DIRECTION OUTPUT ;
    USE SIGNAL ;
    SHAPE ABUTMENT ;
    PORT
      LAYER metal3 ;
      RECT 0.000 101.045 0.070 101.115 ;
    END
  END R0_data[346]
  PIN R0_data[347]
    DIRECTION OUTPUT ;
    USE SIGNAL ;
    SHAPE ABUTMENT ;
    PORT
      LAYER metal3 ;
      RECT 0.000 101.325 0.070 101.395 ;
    END
  END R0_data[347]
  PIN R0_data[348]
    DIRECTION OUTPUT ;
    USE SIGNAL ;
    SHAPE ABUTMENT ;
    PORT
      LAYER metal3 ;
      RECT 0.000 101.605 0.070 101.675 ;
    END
  END R0_data[348]
  PIN R0_data[349]
    DIRECTION OUTPUT ;
    USE SIGNAL ;
    SHAPE ABUTMENT ;
    PORT
      LAYER metal3 ;
      RECT 0.000 101.885 0.070 101.955 ;
    END
  END R0_data[349]
  PIN R0_data[350]
    DIRECTION OUTPUT ;
    USE SIGNAL ;
    SHAPE ABUTMENT ;
    PORT
      LAYER metal3 ;
      RECT 0.000 102.165 0.070 102.235 ;
    END
  END R0_data[350]
  PIN R0_data[351]
    DIRECTION OUTPUT ;
    USE SIGNAL ;
    SHAPE ABUTMENT ;
    PORT
      LAYER metal3 ;
      RECT 0.000 102.445 0.070 102.515 ;
    END
  END R0_data[351]
  PIN R0_data[352]
    DIRECTION OUTPUT ;
    USE SIGNAL ;
    SHAPE ABUTMENT ;
    PORT
      LAYER metal3 ;
      RECT 0.000 102.725 0.070 102.795 ;
    END
  END R0_data[352]
  PIN R0_data[353]
    DIRECTION OUTPUT ;
    USE SIGNAL ;
    SHAPE ABUTMENT ;
    PORT
      LAYER metal3 ;
      RECT 0.000 103.005 0.070 103.075 ;
    END
  END R0_data[353]
  PIN R0_data[354]
    DIRECTION OUTPUT ;
    USE SIGNAL ;
    SHAPE ABUTMENT ;
    PORT
      LAYER metal3 ;
      RECT 0.000 103.285 0.070 103.355 ;
    END
  END R0_data[354]
  PIN R0_data[355]
    DIRECTION OUTPUT ;
    USE SIGNAL ;
    SHAPE ABUTMENT ;
    PORT
      LAYER metal3 ;
      RECT 0.000 103.565 0.070 103.635 ;
    END
  END R0_data[355]
  PIN R0_data[356]
    DIRECTION OUTPUT ;
    USE SIGNAL ;
    SHAPE ABUTMENT ;
    PORT
      LAYER metal3 ;
      RECT 0.000 103.845 0.070 103.915 ;
    END
  END R0_data[356]
  PIN R0_data[357]
    DIRECTION OUTPUT ;
    USE SIGNAL ;
    SHAPE ABUTMENT ;
    PORT
      LAYER metal3 ;
      RECT 0.000 104.125 0.070 104.195 ;
    END
  END R0_data[357]
  PIN R0_data[358]
    DIRECTION OUTPUT ;
    USE SIGNAL ;
    SHAPE ABUTMENT ;
    PORT
      LAYER metal3 ;
      RECT 0.000 104.405 0.070 104.475 ;
    END
  END R0_data[358]
  PIN R0_data[359]
    DIRECTION OUTPUT ;
    USE SIGNAL ;
    SHAPE ABUTMENT ;
    PORT
      LAYER metal3 ;
      RECT 0.000 104.685 0.070 104.755 ;
    END
  END R0_data[359]
  PIN R0_data[360]
    DIRECTION OUTPUT ;
    USE SIGNAL ;
    SHAPE ABUTMENT ;
    PORT
      LAYER metal3 ;
      RECT 0.000 104.965 0.070 105.035 ;
    END
  END R0_data[360]
  PIN R0_data[361]
    DIRECTION OUTPUT ;
    USE SIGNAL ;
    SHAPE ABUTMENT ;
    PORT
      LAYER metal3 ;
      RECT 0.000 105.245 0.070 105.315 ;
    END
  END R0_data[361]
  PIN R0_data[362]
    DIRECTION OUTPUT ;
    USE SIGNAL ;
    SHAPE ABUTMENT ;
    PORT
      LAYER metal3 ;
      RECT 0.000 105.525 0.070 105.595 ;
    END
  END R0_data[362]
  PIN R0_data[363]
    DIRECTION OUTPUT ;
    USE SIGNAL ;
    SHAPE ABUTMENT ;
    PORT
      LAYER metal3 ;
      RECT 0.000 105.805 0.070 105.875 ;
    END
  END R0_data[363]
  PIN R0_data[364]
    DIRECTION OUTPUT ;
    USE SIGNAL ;
    SHAPE ABUTMENT ;
    PORT
      LAYER metal3 ;
      RECT 0.000 106.085 0.070 106.155 ;
    END
  END R0_data[364]
  PIN R0_data[365]
    DIRECTION OUTPUT ;
    USE SIGNAL ;
    SHAPE ABUTMENT ;
    PORT
      LAYER metal3 ;
      RECT 0.000 106.365 0.070 106.435 ;
    END
  END R0_data[365]
  PIN R0_data[366]
    DIRECTION OUTPUT ;
    USE SIGNAL ;
    SHAPE ABUTMENT ;
    PORT
      LAYER metal3 ;
      RECT 0.000 106.645 0.070 106.715 ;
    END
  END R0_data[366]
  PIN R0_data[367]
    DIRECTION OUTPUT ;
    USE SIGNAL ;
    SHAPE ABUTMENT ;
    PORT
      LAYER metal3 ;
      RECT 0.000 106.925 0.070 106.995 ;
    END
  END R0_data[367]
  PIN R0_data[368]
    DIRECTION OUTPUT ;
    USE SIGNAL ;
    SHAPE ABUTMENT ;
    PORT
      LAYER metal3 ;
      RECT 0.000 107.205 0.070 107.275 ;
    END
  END R0_data[368]
  PIN R0_data[369]
    DIRECTION OUTPUT ;
    USE SIGNAL ;
    SHAPE ABUTMENT ;
    PORT
      LAYER metal3 ;
      RECT 0.000 107.485 0.070 107.555 ;
    END
  END R0_data[369]
  PIN R0_data[370]
    DIRECTION OUTPUT ;
    USE SIGNAL ;
    SHAPE ABUTMENT ;
    PORT
      LAYER metal3 ;
      RECT 0.000 107.765 0.070 107.835 ;
    END
  END R0_data[370]
  PIN R0_data[371]
    DIRECTION OUTPUT ;
    USE SIGNAL ;
    SHAPE ABUTMENT ;
    PORT
      LAYER metal3 ;
      RECT 0.000 108.045 0.070 108.115 ;
    END
  END R0_data[371]
  PIN R0_data[372]
    DIRECTION OUTPUT ;
    USE SIGNAL ;
    SHAPE ABUTMENT ;
    PORT
      LAYER metal3 ;
      RECT 0.000 108.325 0.070 108.395 ;
    END
  END R0_data[372]
  PIN R0_data[373]
    DIRECTION OUTPUT ;
    USE SIGNAL ;
    SHAPE ABUTMENT ;
    PORT
      LAYER metal3 ;
      RECT 0.000 108.605 0.070 108.675 ;
    END
  END R0_data[373]
  PIN R0_data[374]
    DIRECTION OUTPUT ;
    USE SIGNAL ;
    SHAPE ABUTMENT ;
    PORT
      LAYER metal3 ;
      RECT 0.000 108.885 0.070 108.955 ;
    END
  END R0_data[374]
  PIN R0_data[375]
    DIRECTION OUTPUT ;
    USE SIGNAL ;
    SHAPE ABUTMENT ;
    PORT
      LAYER metal3 ;
      RECT 0.000 109.165 0.070 109.235 ;
    END
  END R0_data[375]
  PIN R0_data[376]
    DIRECTION OUTPUT ;
    USE SIGNAL ;
    SHAPE ABUTMENT ;
    PORT
      LAYER metal3 ;
      RECT 0.000 109.445 0.070 109.515 ;
    END
  END R0_data[376]
  PIN R0_data[377]
    DIRECTION OUTPUT ;
    USE SIGNAL ;
    SHAPE ABUTMENT ;
    PORT
      LAYER metal3 ;
      RECT 0.000 109.725 0.070 109.795 ;
    END
  END R0_data[377]
  PIN R0_data[378]
    DIRECTION OUTPUT ;
    USE SIGNAL ;
    SHAPE ABUTMENT ;
    PORT
      LAYER metal3 ;
      RECT 0.000 110.005 0.070 110.075 ;
    END
  END R0_data[378]
  PIN R0_data[379]
    DIRECTION OUTPUT ;
    USE SIGNAL ;
    SHAPE ABUTMENT ;
    PORT
      LAYER metal3 ;
      RECT 0.000 110.285 0.070 110.355 ;
    END
  END R0_data[379]
  PIN R0_data[380]
    DIRECTION OUTPUT ;
    USE SIGNAL ;
    SHAPE ABUTMENT ;
    PORT
      LAYER metal3 ;
      RECT 0.000 110.565 0.070 110.635 ;
    END
  END R0_data[380]
  PIN R0_data[381]
    DIRECTION OUTPUT ;
    USE SIGNAL ;
    SHAPE ABUTMENT ;
    PORT
      LAYER metal3 ;
      RECT 0.000 110.845 0.070 110.915 ;
    END
  END R0_data[381]
  PIN R0_data[382]
    DIRECTION OUTPUT ;
    USE SIGNAL ;
    SHAPE ABUTMENT ;
    PORT
      LAYER metal3 ;
      RECT 0.000 111.125 0.070 111.195 ;
    END
  END R0_data[382]
  PIN R0_data[383]
    DIRECTION OUTPUT ;
    USE SIGNAL ;
    SHAPE ABUTMENT ;
    PORT
      LAYER metal3 ;
      RECT 0.000 111.405 0.070 111.475 ;
    END
  END R0_data[383]
  PIN R0_data[384]
    DIRECTION OUTPUT ;
    USE SIGNAL ;
    SHAPE ABUTMENT ;
    PORT
      LAYER metal3 ;
      RECT 0.000 111.685 0.070 111.755 ;
    END
  END R0_data[384]
  PIN R0_data[385]
    DIRECTION OUTPUT ;
    USE SIGNAL ;
    SHAPE ABUTMENT ;
    PORT
      LAYER metal3 ;
      RECT 0.000 111.965 0.070 112.035 ;
    END
  END R0_data[385]
  PIN R0_data[386]
    DIRECTION OUTPUT ;
    USE SIGNAL ;
    SHAPE ABUTMENT ;
    PORT
      LAYER metal3 ;
      RECT 0.000 112.245 0.070 112.315 ;
    END
  END R0_data[386]
  PIN R0_data[387]
    DIRECTION OUTPUT ;
    USE SIGNAL ;
    SHAPE ABUTMENT ;
    PORT
      LAYER metal3 ;
      RECT 0.000 112.525 0.070 112.595 ;
    END
  END R0_data[387]
  PIN R0_data[388]
    DIRECTION OUTPUT ;
    USE SIGNAL ;
    SHAPE ABUTMENT ;
    PORT
      LAYER metal3 ;
      RECT 0.000 112.805 0.070 112.875 ;
    END
  END R0_data[388]
  PIN R0_data[389]
    DIRECTION OUTPUT ;
    USE SIGNAL ;
    SHAPE ABUTMENT ;
    PORT
      LAYER metal3 ;
      RECT 0.000 113.085 0.070 113.155 ;
    END
  END R0_data[389]
  PIN R0_data[390]
    DIRECTION OUTPUT ;
    USE SIGNAL ;
    SHAPE ABUTMENT ;
    PORT
      LAYER metal3 ;
      RECT 0.000 113.365 0.070 113.435 ;
    END
  END R0_data[390]
  PIN R0_data[391]
    DIRECTION OUTPUT ;
    USE SIGNAL ;
    SHAPE ABUTMENT ;
    PORT
      LAYER metal3 ;
      RECT 0.000 113.645 0.070 113.715 ;
    END
  END R0_data[391]
  PIN R0_data[392]
    DIRECTION OUTPUT ;
    USE SIGNAL ;
    SHAPE ABUTMENT ;
    PORT
      LAYER metal3 ;
      RECT 0.000 113.925 0.070 113.995 ;
    END
  END R0_data[392]
  PIN R0_data[393]
    DIRECTION OUTPUT ;
    USE SIGNAL ;
    SHAPE ABUTMENT ;
    PORT
      LAYER metal3 ;
      RECT 0.000 114.205 0.070 114.275 ;
    END
  END R0_data[393]
  PIN R0_data[394]
    DIRECTION OUTPUT ;
    USE SIGNAL ;
    SHAPE ABUTMENT ;
    PORT
      LAYER metal3 ;
      RECT 0.000 114.485 0.070 114.555 ;
    END
  END R0_data[394]
  PIN R0_data[395]
    DIRECTION OUTPUT ;
    USE SIGNAL ;
    SHAPE ABUTMENT ;
    PORT
      LAYER metal3 ;
      RECT 0.000 114.765 0.070 114.835 ;
    END
  END R0_data[395]
  PIN R0_data[396]
    DIRECTION OUTPUT ;
    USE SIGNAL ;
    SHAPE ABUTMENT ;
    PORT
      LAYER metal3 ;
      RECT 0.000 115.045 0.070 115.115 ;
    END
  END R0_data[396]
  PIN R0_data[397]
    DIRECTION OUTPUT ;
    USE SIGNAL ;
    SHAPE ABUTMENT ;
    PORT
      LAYER metal3 ;
      RECT 0.000 115.325 0.070 115.395 ;
    END
  END R0_data[397]
  PIN R0_data[398]
    DIRECTION OUTPUT ;
    USE SIGNAL ;
    SHAPE ABUTMENT ;
    PORT
      LAYER metal3 ;
      RECT 0.000 115.605 0.070 115.675 ;
    END
  END R0_data[398]
  PIN R0_data[399]
    DIRECTION OUTPUT ;
    USE SIGNAL ;
    SHAPE ABUTMENT ;
    PORT
      LAYER metal3 ;
      RECT 0.000 115.885 0.070 115.955 ;
    END
  END R0_data[399]
  PIN R0_data[400]
    DIRECTION OUTPUT ;
    USE SIGNAL ;
    SHAPE ABUTMENT ;
    PORT
      LAYER metal3 ;
      RECT 0.000 116.165 0.070 116.235 ;
    END
  END R0_data[400]
  PIN R0_data[401]
    DIRECTION OUTPUT ;
    USE SIGNAL ;
    SHAPE ABUTMENT ;
    PORT
      LAYER metal3 ;
      RECT 0.000 116.445 0.070 116.515 ;
    END
  END R0_data[401]
  PIN R0_data[402]
    DIRECTION OUTPUT ;
    USE SIGNAL ;
    SHAPE ABUTMENT ;
    PORT
      LAYER metal3 ;
      RECT 0.000 116.725 0.070 116.795 ;
    END
  END R0_data[402]
  PIN R0_data[403]
    DIRECTION OUTPUT ;
    USE SIGNAL ;
    SHAPE ABUTMENT ;
    PORT
      LAYER metal3 ;
      RECT 0.000 117.005 0.070 117.075 ;
    END
  END R0_data[403]
  PIN R0_data[404]
    DIRECTION OUTPUT ;
    USE SIGNAL ;
    SHAPE ABUTMENT ;
    PORT
      LAYER metal3 ;
      RECT 0.000 117.285 0.070 117.355 ;
    END
  END R0_data[404]
  PIN R0_data[405]
    DIRECTION OUTPUT ;
    USE SIGNAL ;
    SHAPE ABUTMENT ;
    PORT
      LAYER metal3 ;
      RECT 0.000 117.565 0.070 117.635 ;
    END
  END R0_data[405]
  PIN R0_data[406]
    DIRECTION OUTPUT ;
    USE SIGNAL ;
    SHAPE ABUTMENT ;
    PORT
      LAYER metal3 ;
      RECT 0.000 117.845 0.070 117.915 ;
    END
  END R0_data[406]
  PIN R0_data[407]
    DIRECTION OUTPUT ;
    USE SIGNAL ;
    SHAPE ABUTMENT ;
    PORT
      LAYER metal3 ;
      RECT 0.000 118.125 0.070 118.195 ;
    END
  END R0_data[407]
  PIN R0_data[408]
    DIRECTION OUTPUT ;
    USE SIGNAL ;
    SHAPE ABUTMENT ;
    PORT
      LAYER metal3 ;
      RECT 0.000 118.405 0.070 118.475 ;
    END
  END R0_data[408]
  PIN R0_data[409]
    DIRECTION OUTPUT ;
    USE SIGNAL ;
    SHAPE ABUTMENT ;
    PORT
      LAYER metal3 ;
      RECT 0.000 118.685 0.070 118.755 ;
    END
  END R0_data[409]
  PIN R0_data[410]
    DIRECTION OUTPUT ;
    USE SIGNAL ;
    SHAPE ABUTMENT ;
    PORT
      LAYER metal3 ;
      RECT 0.000 118.965 0.070 119.035 ;
    END
  END R0_data[410]
  PIN R0_data[411]
    DIRECTION OUTPUT ;
    USE SIGNAL ;
    SHAPE ABUTMENT ;
    PORT
      LAYER metal3 ;
      RECT 0.000 119.245 0.070 119.315 ;
    END
  END R0_data[411]
  PIN R0_data[412]
    DIRECTION OUTPUT ;
    USE SIGNAL ;
    SHAPE ABUTMENT ;
    PORT
      LAYER metal3 ;
      RECT 0.000 119.525 0.070 119.595 ;
    END
  END R0_data[412]
  PIN R0_data[413]
    DIRECTION OUTPUT ;
    USE SIGNAL ;
    SHAPE ABUTMENT ;
    PORT
      LAYER metal3 ;
      RECT 0.000 119.805 0.070 119.875 ;
    END
  END R0_data[413]
  PIN R0_data[414]
    DIRECTION OUTPUT ;
    USE SIGNAL ;
    SHAPE ABUTMENT ;
    PORT
      LAYER metal3 ;
      RECT 0.000 120.085 0.070 120.155 ;
    END
  END R0_data[414]
  PIN R0_data[415]
    DIRECTION OUTPUT ;
    USE SIGNAL ;
    SHAPE ABUTMENT ;
    PORT
      LAYER metal3 ;
      RECT 0.000 120.365 0.070 120.435 ;
    END
  END R0_data[415]
  PIN R0_data[416]
    DIRECTION OUTPUT ;
    USE SIGNAL ;
    SHAPE ABUTMENT ;
    PORT
      LAYER metal3 ;
      RECT 0.000 120.645 0.070 120.715 ;
    END
  END R0_data[416]
  PIN R0_data[417]
    DIRECTION OUTPUT ;
    USE SIGNAL ;
    SHAPE ABUTMENT ;
    PORT
      LAYER metal3 ;
      RECT 0.000 120.925 0.070 120.995 ;
    END
  END R0_data[417]
  PIN R0_data[418]
    DIRECTION OUTPUT ;
    USE SIGNAL ;
    SHAPE ABUTMENT ;
    PORT
      LAYER metal3 ;
      RECT 0.000 121.205 0.070 121.275 ;
    END
  END R0_data[418]
  PIN R0_data[419]
    DIRECTION OUTPUT ;
    USE SIGNAL ;
    SHAPE ABUTMENT ;
    PORT
      LAYER metal3 ;
      RECT 0.000 121.485 0.070 121.555 ;
    END
  END R0_data[419]
  PIN R0_data[420]
    DIRECTION OUTPUT ;
    USE SIGNAL ;
    SHAPE ABUTMENT ;
    PORT
      LAYER metal3 ;
      RECT 0.000 121.765 0.070 121.835 ;
    END
  END R0_data[420]
  PIN R0_data[421]
    DIRECTION OUTPUT ;
    USE SIGNAL ;
    SHAPE ABUTMENT ;
    PORT
      LAYER metal3 ;
      RECT 0.000 122.045 0.070 122.115 ;
    END
  END R0_data[421]
  PIN R0_data[422]
    DIRECTION OUTPUT ;
    USE SIGNAL ;
    SHAPE ABUTMENT ;
    PORT
      LAYER metal3 ;
      RECT 0.000 122.325 0.070 122.395 ;
    END
  END R0_data[422]
  PIN R0_data[423]
    DIRECTION OUTPUT ;
    USE SIGNAL ;
    SHAPE ABUTMENT ;
    PORT
      LAYER metal3 ;
      RECT 0.000 122.605 0.070 122.675 ;
    END
  END R0_data[423]
  PIN R0_data[424]
    DIRECTION OUTPUT ;
    USE SIGNAL ;
    SHAPE ABUTMENT ;
    PORT
      LAYER metal3 ;
      RECT 0.000 122.885 0.070 122.955 ;
    END
  END R0_data[424]
  PIN R0_data[425]
    DIRECTION OUTPUT ;
    USE SIGNAL ;
    SHAPE ABUTMENT ;
    PORT
      LAYER metal3 ;
      RECT 0.000 123.165 0.070 123.235 ;
    END
  END R0_data[425]
  PIN R0_data[426]
    DIRECTION OUTPUT ;
    USE SIGNAL ;
    SHAPE ABUTMENT ;
    PORT
      LAYER metal3 ;
      RECT 0.000 123.445 0.070 123.515 ;
    END
  END R0_data[426]
  PIN R0_data[427]
    DIRECTION OUTPUT ;
    USE SIGNAL ;
    SHAPE ABUTMENT ;
    PORT
      LAYER metal3 ;
      RECT 0.000 123.725 0.070 123.795 ;
    END
  END R0_data[427]
  PIN R0_data[428]
    DIRECTION OUTPUT ;
    USE SIGNAL ;
    SHAPE ABUTMENT ;
    PORT
      LAYER metal3 ;
      RECT 0.000 124.005 0.070 124.075 ;
    END
  END R0_data[428]
  PIN R0_data[429]
    DIRECTION OUTPUT ;
    USE SIGNAL ;
    SHAPE ABUTMENT ;
    PORT
      LAYER metal3 ;
      RECT 0.000 124.285 0.070 124.355 ;
    END
  END R0_data[429]
  PIN R0_data[430]
    DIRECTION OUTPUT ;
    USE SIGNAL ;
    SHAPE ABUTMENT ;
    PORT
      LAYER metal3 ;
      RECT 0.000 124.565 0.070 124.635 ;
    END
  END R0_data[430]
  PIN R0_data[431]
    DIRECTION OUTPUT ;
    USE SIGNAL ;
    SHAPE ABUTMENT ;
    PORT
      LAYER metal3 ;
      RECT 0.000 124.845 0.070 124.915 ;
    END
  END R0_data[431]
  PIN R0_data[432]
    DIRECTION OUTPUT ;
    USE SIGNAL ;
    SHAPE ABUTMENT ;
    PORT
      LAYER metal3 ;
      RECT 0.000 125.125 0.070 125.195 ;
    END
  END R0_data[432]
  PIN R0_data[433]
    DIRECTION OUTPUT ;
    USE SIGNAL ;
    SHAPE ABUTMENT ;
    PORT
      LAYER metal3 ;
      RECT 0.000 125.405 0.070 125.475 ;
    END
  END R0_data[433]
  PIN R0_data[434]
    DIRECTION OUTPUT ;
    USE SIGNAL ;
    SHAPE ABUTMENT ;
    PORT
      LAYER metal3 ;
      RECT 0.000 125.685 0.070 125.755 ;
    END
  END R0_data[434]
  PIN R0_data[435]
    DIRECTION OUTPUT ;
    USE SIGNAL ;
    SHAPE ABUTMENT ;
    PORT
      LAYER metal3 ;
      RECT 0.000 125.965 0.070 126.035 ;
    END
  END R0_data[435]
  PIN R0_data[436]
    DIRECTION OUTPUT ;
    USE SIGNAL ;
    SHAPE ABUTMENT ;
    PORT
      LAYER metal3 ;
      RECT 0.000 126.245 0.070 126.315 ;
    END
  END R0_data[436]
  PIN R0_data[437]
    DIRECTION OUTPUT ;
    USE SIGNAL ;
    SHAPE ABUTMENT ;
    PORT
      LAYER metal3 ;
      RECT 0.000 126.525 0.070 126.595 ;
    END
  END R0_data[437]
  PIN R0_data[438]
    DIRECTION OUTPUT ;
    USE SIGNAL ;
    SHAPE ABUTMENT ;
    PORT
      LAYER metal3 ;
      RECT 0.000 126.805 0.070 126.875 ;
    END
  END R0_data[438]
  PIN R0_data[439]
    DIRECTION OUTPUT ;
    USE SIGNAL ;
    SHAPE ABUTMENT ;
    PORT
      LAYER metal3 ;
      RECT 0.000 127.085 0.070 127.155 ;
    END
  END R0_data[439]
  PIN R0_data[440]
    DIRECTION OUTPUT ;
    USE SIGNAL ;
    SHAPE ABUTMENT ;
    PORT
      LAYER metal3 ;
      RECT 0.000 127.365 0.070 127.435 ;
    END
  END R0_data[440]
  PIN R0_data[441]
    DIRECTION OUTPUT ;
    USE SIGNAL ;
    SHAPE ABUTMENT ;
    PORT
      LAYER metal3 ;
      RECT 0.000 127.645 0.070 127.715 ;
    END
  END R0_data[441]
  PIN R0_data[442]
    DIRECTION OUTPUT ;
    USE SIGNAL ;
    SHAPE ABUTMENT ;
    PORT
      LAYER metal3 ;
      RECT 0.000 127.925 0.070 127.995 ;
    END
  END R0_data[442]
  PIN R0_data[443]
    DIRECTION OUTPUT ;
    USE SIGNAL ;
    SHAPE ABUTMENT ;
    PORT
      LAYER metal3 ;
      RECT 0.000 128.205 0.070 128.275 ;
    END
  END R0_data[443]
  PIN R0_data[444]
    DIRECTION OUTPUT ;
    USE SIGNAL ;
    SHAPE ABUTMENT ;
    PORT
      LAYER metal3 ;
      RECT 0.000 128.485 0.070 128.555 ;
    END
  END R0_data[444]
  PIN R0_data[445]
    DIRECTION OUTPUT ;
    USE SIGNAL ;
    SHAPE ABUTMENT ;
    PORT
      LAYER metal3 ;
      RECT 0.000 128.765 0.070 128.835 ;
    END
  END R0_data[445]
  PIN R0_data[446]
    DIRECTION OUTPUT ;
    USE SIGNAL ;
    SHAPE ABUTMENT ;
    PORT
      LAYER metal3 ;
      RECT 0.000 129.045 0.070 129.115 ;
    END
  END R0_data[446]
  PIN R0_data[447]
    DIRECTION OUTPUT ;
    USE SIGNAL ;
    SHAPE ABUTMENT ;
    PORT
      LAYER metal3 ;
      RECT 0.000 129.325 0.070 129.395 ;
    END
  END R0_data[447]
  PIN R0_data[448]
    DIRECTION OUTPUT ;
    USE SIGNAL ;
    SHAPE ABUTMENT ;
    PORT
      LAYER metal3 ;
      RECT 0.000 129.605 0.070 129.675 ;
    END
  END R0_data[448]
  PIN R0_data[449]
    DIRECTION OUTPUT ;
    USE SIGNAL ;
    SHAPE ABUTMENT ;
    PORT
      LAYER metal3 ;
      RECT 0.000 129.885 0.070 129.955 ;
    END
  END R0_data[449]
  PIN R0_data[450]
    DIRECTION OUTPUT ;
    USE SIGNAL ;
    SHAPE ABUTMENT ;
    PORT
      LAYER metal3 ;
      RECT 0.000 130.165 0.070 130.235 ;
    END
  END R0_data[450]
  PIN R0_data[451]
    DIRECTION OUTPUT ;
    USE SIGNAL ;
    SHAPE ABUTMENT ;
    PORT
      LAYER metal3 ;
      RECT 0.000 130.445 0.070 130.515 ;
    END
  END R0_data[451]
  PIN R0_data[452]
    DIRECTION OUTPUT ;
    USE SIGNAL ;
    SHAPE ABUTMENT ;
    PORT
      LAYER metal3 ;
      RECT 0.000 130.725 0.070 130.795 ;
    END
  END R0_data[452]
  PIN R0_data[453]
    DIRECTION OUTPUT ;
    USE SIGNAL ;
    SHAPE ABUTMENT ;
    PORT
      LAYER metal3 ;
      RECT 0.000 131.005 0.070 131.075 ;
    END
  END R0_data[453]
  PIN R0_data[454]
    DIRECTION OUTPUT ;
    USE SIGNAL ;
    SHAPE ABUTMENT ;
    PORT
      LAYER metal3 ;
      RECT 0.000 131.285 0.070 131.355 ;
    END
  END R0_data[454]
  PIN R0_data[455]
    DIRECTION OUTPUT ;
    USE SIGNAL ;
    SHAPE ABUTMENT ;
    PORT
      LAYER metal3 ;
      RECT 0.000 131.565 0.070 131.635 ;
    END
  END R0_data[455]
  PIN R0_data[456]
    DIRECTION OUTPUT ;
    USE SIGNAL ;
    SHAPE ABUTMENT ;
    PORT
      LAYER metal3 ;
      RECT 0.000 131.845 0.070 131.915 ;
    END
  END R0_data[456]
  PIN R0_data[457]
    DIRECTION OUTPUT ;
    USE SIGNAL ;
    SHAPE ABUTMENT ;
    PORT
      LAYER metal3 ;
      RECT 0.000 132.125 0.070 132.195 ;
    END
  END R0_data[457]
  PIN R0_data[458]
    DIRECTION OUTPUT ;
    USE SIGNAL ;
    SHAPE ABUTMENT ;
    PORT
      LAYER metal3 ;
      RECT 0.000 132.405 0.070 132.475 ;
    END
  END R0_data[458]
  PIN R0_data[459]
    DIRECTION OUTPUT ;
    USE SIGNAL ;
    SHAPE ABUTMENT ;
    PORT
      LAYER metal3 ;
      RECT 0.000 132.685 0.070 132.755 ;
    END
  END R0_data[459]
  PIN R0_data[460]
    DIRECTION OUTPUT ;
    USE SIGNAL ;
    SHAPE ABUTMENT ;
    PORT
      LAYER metal3 ;
      RECT 0.000 132.965 0.070 133.035 ;
    END
  END R0_data[460]
  PIN R0_data[461]
    DIRECTION OUTPUT ;
    USE SIGNAL ;
    SHAPE ABUTMENT ;
    PORT
      LAYER metal3 ;
      RECT 0.000 133.245 0.070 133.315 ;
    END
  END R0_data[461]
  PIN R0_data[462]
    DIRECTION OUTPUT ;
    USE SIGNAL ;
    SHAPE ABUTMENT ;
    PORT
      LAYER metal3 ;
      RECT 0.000 133.525 0.070 133.595 ;
    END
  END R0_data[462]
  PIN R0_data[463]
    DIRECTION OUTPUT ;
    USE SIGNAL ;
    SHAPE ABUTMENT ;
    PORT
      LAYER metal3 ;
      RECT 0.000 133.805 0.070 133.875 ;
    END
  END R0_data[463]
  PIN R0_data[464]
    DIRECTION OUTPUT ;
    USE SIGNAL ;
    SHAPE ABUTMENT ;
    PORT
      LAYER metal3 ;
      RECT 0.000 134.085 0.070 134.155 ;
    END
  END R0_data[464]
  PIN R0_data[465]
    DIRECTION OUTPUT ;
    USE SIGNAL ;
    SHAPE ABUTMENT ;
    PORT
      LAYER metal3 ;
      RECT 0.000 134.365 0.070 134.435 ;
    END
  END R0_data[465]
  PIN R0_data[466]
    DIRECTION OUTPUT ;
    USE SIGNAL ;
    SHAPE ABUTMENT ;
    PORT
      LAYER metal3 ;
      RECT 0.000 134.645 0.070 134.715 ;
    END
  END R0_data[466]
  PIN R0_data[467]
    DIRECTION OUTPUT ;
    USE SIGNAL ;
    SHAPE ABUTMENT ;
    PORT
      LAYER metal3 ;
      RECT 0.000 134.925 0.070 134.995 ;
    END
  END R0_data[467]
  PIN R0_data[468]
    DIRECTION OUTPUT ;
    USE SIGNAL ;
    SHAPE ABUTMENT ;
    PORT
      LAYER metal3 ;
      RECT 0.000 135.205 0.070 135.275 ;
    END
  END R0_data[468]
  PIN R0_data[469]
    DIRECTION OUTPUT ;
    USE SIGNAL ;
    SHAPE ABUTMENT ;
    PORT
      LAYER metal3 ;
      RECT 0.000 135.485 0.070 135.555 ;
    END
  END R0_data[469]
  PIN R0_data[470]
    DIRECTION OUTPUT ;
    USE SIGNAL ;
    SHAPE ABUTMENT ;
    PORT
      LAYER metal3 ;
      RECT 0.000 135.765 0.070 135.835 ;
    END
  END R0_data[470]
  PIN R0_data[471]
    DIRECTION OUTPUT ;
    USE SIGNAL ;
    SHAPE ABUTMENT ;
    PORT
      LAYER metal3 ;
      RECT 0.000 136.045 0.070 136.115 ;
    END
  END R0_data[471]
  PIN R0_data[472]
    DIRECTION OUTPUT ;
    USE SIGNAL ;
    SHAPE ABUTMENT ;
    PORT
      LAYER metal3 ;
      RECT 0.000 136.325 0.070 136.395 ;
    END
  END R0_data[472]
  PIN R0_data[473]
    DIRECTION OUTPUT ;
    USE SIGNAL ;
    SHAPE ABUTMENT ;
    PORT
      LAYER metal3 ;
      RECT 0.000 136.605 0.070 136.675 ;
    END
  END R0_data[473]
  PIN R0_data[474]
    DIRECTION OUTPUT ;
    USE SIGNAL ;
    SHAPE ABUTMENT ;
    PORT
      LAYER metal3 ;
      RECT 0.000 136.885 0.070 136.955 ;
    END
  END R0_data[474]
  PIN R0_data[475]
    DIRECTION OUTPUT ;
    USE SIGNAL ;
    SHAPE ABUTMENT ;
    PORT
      LAYER metal3 ;
      RECT 0.000 137.165 0.070 137.235 ;
    END
  END R0_data[475]
  PIN R0_data[476]
    DIRECTION OUTPUT ;
    USE SIGNAL ;
    SHAPE ABUTMENT ;
    PORT
      LAYER metal3 ;
      RECT 0.000 137.445 0.070 137.515 ;
    END
  END R0_data[476]
  PIN R0_data[477]
    DIRECTION OUTPUT ;
    USE SIGNAL ;
    SHAPE ABUTMENT ;
    PORT
      LAYER metal3 ;
      RECT 0.000 137.725 0.070 137.795 ;
    END
  END R0_data[477]
  PIN R0_data[478]
    DIRECTION OUTPUT ;
    USE SIGNAL ;
    SHAPE ABUTMENT ;
    PORT
      LAYER metal3 ;
      RECT 0.000 138.005 0.070 138.075 ;
    END
  END R0_data[478]
  PIN R0_data[479]
    DIRECTION OUTPUT ;
    USE SIGNAL ;
    SHAPE ABUTMENT ;
    PORT
      LAYER metal3 ;
      RECT 0.000 138.285 0.070 138.355 ;
    END
  END R0_data[479]
  PIN R0_data[480]
    DIRECTION OUTPUT ;
    USE SIGNAL ;
    SHAPE ABUTMENT ;
    PORT
      LAYER metal3 ;
      RECT 0.000 138.565 0.070 138.635 ;
    END
  END R0_data[480]
  PIN R0_data[481]
    DIRECTION OUTPUT ;
    USE SIGNAL ;
    SHAPE ABUTMENT ;
    PORT
      LAYER metal3 ;
      RECT 0.000 138.845 0.070 138.915 ;
    END
  END R0_data[481]
  PIN R0_data[482]
    DIRECTION OUTPUT ;
    USE SIGNAL ;
    SHAPE ABUTMENT ;
    PORT
      LAYER metal3 ;
      RECT 0.000 139.125 0.070 139.195 ;
    END
  END R0_data[482]
  PIN R0_data[483]
    DIRECTION OUTPUT ;
    USE SIGNAL ;
    SHAPE ABUTMENT ;
    PORT
      LAYER metal3 ;
      RECT 0.000 139.405 0.070 139.475 ;
    END
  END R0_data[483]
  PIN R0_data[484]
    DIRECTION OUTPUT ;
    USE SIGNAL ;
    SHAPE ABUTMENT ;
    PORT
      LAYER metal3 ;
      RECT 0.000 139.685 0.070 139.755 ;
    END
  END R0_data[484]
  PIN R0_data[485]
    DIRECTION OUTPUT ;
    USE SIGNAL ;
    SHAPE ABUTMENT ;
    PORT
      LAYER metal3 ;
      RECT 0.000 139.965 0.070 140.035 ;
    END
  END R0_data[485]
  PIN R0_data[486]
    DIRECTION OUTPUT ;
    USE SIGNAL ;
    SHAPE ABUTMENT ;
    PORT
      LAYER metal3 ;
      RECT 0.000 140.245 0.070 140.315 ;
    END
  END R0_data[486]
  PIN R0_data[487]
    DIRECTION OUTPUT ;
    USE SIGNAL ;
    SHAPE ABUTMENT ;
    PORT
      LAYER metal3 ;
      RECT 0.000 140.525 0.070 140.595 ;
    END
  END R0_data[487]
  PIN R0_data[488]
    DIRECTION OUTPUT ;
    USE SIGNAL ;
    SHAPE ABUTMENT ;
    PORT
      LAYER metal3 ;
      RECT 0.000 140.805 0.070 140.875 ;
    END
  END R0_data[488]
  PIN R0_data[489]
    DIRECTION OUTPUT ;
    USE SIGNAL ;
    SHAPE ABUTMENT ;
    PORT
      LAYER metal3 ;
      RECT 0.000 141.085 0.070 141.155 ;
    END
  END R0_data[489]
  PIN R0_data[490]
    DIRECTION OUTPUT ;
    USE SIGNAL ;
    SHAPE ABUTMENT ;
    PORT
      LAYER metal3 ;
      RECT 0.000 141.365 0.070 141.435 ;
    END
  END R0_data[490]
  PIN R0_data[491]
    DIRECTION OUTPUT ;
    USE SIGNAL ;
    SHAPE ABUTMENT ;
    PORT
      LAYER metal3 ;
      RECT 0.000 141.645 0.070 141.715 ;
    END
  END R0_data[491]
  PIN R0_data[492]
    DIRECTION OUTPUT ;
    USE SIGNAL ;
    SHAPE ABUTMENT ;
    PORT
      LAYER metal3 ;
      RECT 0.000 141.925 0.070 141.995 ;
    END
  END R0_data[492]
  PIN R0_data[493]
    DIRECTION OUTPUT ;
    USE SIGNAL ;
    SHAPE ABUTMENT ;
    PORT
      LAYER metal3 ;
      RECT 0.000 142.205 0.070 142.275 ;
    END
  END R0_data[493]
  PIN R0_data[494]
    DIRECTION OUTPUT ;
    USE SIGNAL ;
    SHAPE ABUTMENT ;
    PORT
      LAYER metal3 ;
      RECT 0.000 142.485 0.070 142.555 ;
    END
  END R0_data[494]
  PIN R0_data[495]
    DIRECTION OUTPUT ;
    USE SIGNAL ;
    SHAPE ABUTMENT ;
    PORT
      LAYER metal3 ;
      RECT 0.000 142.765 0.070 142.835 ;
    END
  END R0_data[495]
  PIN R0_data[496]
    DIRECTION OUTPUT ;
    USE SIGNAL ;
    SHAPE ABUTMENT ;
    PORT
      LAYER metal3 ;
      RECT 0.000 143.045 0.070 143.115 ;
    END
  END R0_data[496]
  PIN R0_data[497]
    DIRECTION OUTPUT ;
    USE SIGNAL ;
    SHAPE ABUTMENT ;
    PORT
      LAYER metal3 ;
      RECT 0.000 143.325 0.070 143.395 ;
    END
  END R0_data[497]
  PIN R0_data[498]
    DIRECTION OUTPUT ;
    USE SIGNAL ;
    SHAPE ABUTMENT ;
    PORT
      LAYER metal3 ;
      RECT 0.000 143.605 0.070 143.675 ;
    END
  END R0_data[498]
  PIN R0_data[499]
    DIRECTION OUTPUT ;
    USE SIGNAL ;
    SHAPE ABUTMENT ;
    PORT
      LAYER metal3 ;
      RECT 0.000 143.885 0.070 143.955 ;
    END
  END R0_data[499]
  PIN R0_data[500]
    DIRECTION OUTPUT ;
    USE SIGNAL ;
    SHAPE ABUTMENT ;
    PORT
      LAYER metal3 ;
      RECT 0.000 144.165 0.070 144.235 ;
    END
  END R0_data[500]
  PIN R0_data[501]
    DIRECTION OUTPUT ;
    USE SIGNAL ;
    SHAPE ABUTMENT ;
    PORT
      LAYER metal3 ;
      RECT 0.000 144.445 0.070 144.515 ;
    END
  END R0_data[501]
  PIN R0_data[502]
    DIRECTION OUTPUT ;
    USE SIGNAL ;
    SHAPE ABUTMENT ;
    PORT
      LAYER metal3 ;
      RECT 0.000 144.725 0.070 144.795 ;
    END
  END R0_data[502]
  PIN R0_data[503]
    DIRECTION OUTPUT ;
    USE SIGNAL ;
    SHAPE ABUTMENT ;
    PORT
      LAYER metal3 ;
      RECT 0.000 145.005 0.070 145.075 ;
    END
  END R0_data[503]
  PIN R0_data[504]
    DIRECTION OUTPUT ;
    USE SIGNAL ;
    SHAPE ABUTMENT ;
    PORT
      LAYER metal3 ;
      RECT 0.000 145.285 0.070 145.355 ;
    END
  END R0_data[504]
  PIN R0_data[505]
    DIRECTION OUTPUT ;
    USE SIGNAL ;
    SHAPE ABUTMENT ;
    PORT
      LAYER metal3 ;
      RECT 0.000 145.565 0.070 145.635 ;
    END
  END R0_data[505]
  PIN R0_data[506]
    DIRECTION OUTPUT ;
    USE SIGNAL ;
    SHAPE ABUTMENT ;
    PORT
      LAYER metal3 ;
      RECT 0.000 145.845 0.070 145.915 ;
    END
  END R0_data[506]
  PIN R0_data[507]
    DIRECTION OUTPUT ;
    USE SIGNAL ;
    SHAPE ABUTMENT ;
    PORT
      LAYER metal3 ;
      RECT 0.000 146.125 0.070 146.195 ;
    END
  END R0_data[507]
  PIN R0_data[508]
    DIRECTION OUTPUT ;
    USE SIGNAL ;
    SHAPE ABUTMENT ;
    PORT
      LAYER metal3 ;
      RECT 0.000 146.405 0.070 146.475 ;
    END
  END R0_data[508]
  PIN R0_data[509]
    DIRECTION OUTPUT ;
    USE SIGNAL ;
    SHAPE ABUTMENT ;
    PORT
      LAYER metal3 ;
      RECT 0.000 146.685 0.070 146.755 ;
    END
  END R0_data[509]
  PIN R0_data[510]
    DIRECTION OUTPUT ;
    USE SIGNAL ;
    SHAPE ABUTMENT ;
    PORT
      LAYER metal3 ;
      RECT 0.000 146.965 0.070 147.035 ;
    END
  END R0_data[510]
  PIN R0_data[511]
    DIRECTION OUTPUT ;
    USE SIGNAL ;
    SHAPE ABUTMENT ;
    PORT
      LAYER metal3 ;
      RECT 0.000 147.245 0.070 147.315 ;
    END
  END R0_data[511]
  PIN R0_en
    DIRECTION INPUT ;
    USE SIGNAL ;
    SHAPE ABUTMENT ;
    PORT
      LAYER metal3 ;
      RECT 0.000 147.525 0.070 147.595 ;
    END
  END R0_en
  PIN W0_addr[0]
    DIRECTION INPUT ;
    USE SIGNAL ;
    SHAPE ABUTMENT ;
    PORT
      LAYER metal3 ;
      RECT 0.000 147.805 0.070 147.875 ;
    END
  END W0_addr[0]
  PIN W0_addr[1]
    DIRECTION INPUT ;
    USE SIGNAL ;
    SHAPE ABUTMENT ;
    PORT
      LAYER metal3 ;
      RECT 0.000 148.085 0.070 148.155 ;
    END
  END W0_addr[1]
  PIN W0_addr[2]
    DIRECTION INPUT ;
    USE SIGNAL ;
    SHAPE ABUTMENT ;
    PORT
      LAYER metal3 ;
      RECT 0.000 148.365 0.070 148.435 ;
    END
  END W0_addr[2]
  PIN W0_addr[3]
    DIRECTION INPUT ;
    USE SIGNAL ;
    SHAPE ABUTMENT ;
    PORT
      LAYER metal3 ;
      RECT 0.000 148.645 0.070 148.715 ;
    END
  END W0_addr[3]
  PIN W0_addr[4]
    DIRECTION INPUT ;
    USE SIGNAL ;
    SHAPE ABUTMENT ;
    PORT
      LAYER metal3 ;
      RECT 0.000 148.925 0.070 148.995 ;
    END
  END W0_addr[4]
  PIN W0_addr[5]
    DIRECTION INPUT ;
    USE SIGNAL ;
    SHAPE ABUTMENT ;
    PORT
      LAYER metal3 ;
      RECT 0.000 149.205 0.070 149.275 ;
    END
  END W0_addr[5]
  PIN W0_addr[6]
    DIRECTION INPUT ;
    USE SIGNAL ;
    SHAPE ABUTMENT ;
    PORT
      LAYER metal3 ;
      RECT 0.000 149.485 0.070 149.555 ;
    END
  END W0_addr[6]
  PIN W0_addr[7]
    DIRECTION INPUT ;
    USE SIGNAL ;
    SHAPE ABUTMENT ;
    PORT
      LAYER metal3 ;
      RECT 0.000 149.765 0.070 149.835 ;
    END
  END W0_addr[7]
  PIN W0_addr[8]
    DIRECTION INPUT ;
    USE SIGNAL ;
    SHAPE ABUTMENT ;
    PORT
      LAYER metal3 ;
      RECT 0.000 150.045 0.070 150.115 ;
    END
  END W0_addr[8]
  PIN W0_clk
    DIRECTION INPUT ;
    USE SIGNAL ;
    SHAPE ABUTMENT ;
    PORT
      LAYER metal3 ;
      RECT 0.000 150.325 0.070 150.395 ;
    END
  END W0_clk
  PIN W0_data[0]
    DIRECTION INPUT ;
    USE SIGNAL ;
    SHAPE ABUTMENT ;
    PORT
      LAYER metal3 ;
      RECT 0.000 150.605 0.070 150.675 ;
    END
  END W0_data[0]
  PIN W0_data[1]
    DIRECTION INPUT ;
    USE SIGNAL ;
    SHAPE ABUTMENT ;
    PORT
      LAYER metal3 ;
      RECT 0.000 150.885 0.070 150.955 ;
    END
  END W0_data[1]
  PIN W0_data[2]
    DIRECTION INPUT ;
    USE SIGNAL ;
    SHAPE ABUTMENT ;
    PORT
      LAYER metal3 ;
      RECT 0.000 151.165 0.070 151.235 ;
    END
  END W0_data[2]
  PIN W0_data[3]
    DIRECTION INPUT ;
    USE SIGNAL ;
    SHAPE ABUTMENT ;
    PORT
      LAYER metal3 ;
      RECT 0.000 151.445 0.070 151.515 ;
    END
  END W0_data[3]
  PIN W0_data[4]
    DIRECTION INPUT ;
    USE SIGNAL ;
    SHAPE ABUTMENT ;
    PORT
      LAYER metal3 ;
      RECT 0.000 151.725 0.070 151.795 ;
    END
  END W0_data[4]
  PIN W0_data[5]
    DIRECTION INPUT ;
    USE SIGNAL ;
    SHAPE ABUTMENT ;
    PORT
      LAYER metal3 ;
      RECT 0.000 152.005 0.070 152.075 ;
    END
  END W0_data[5]
  PIN W0_data[6]
    DIRECTION INPUT ;
    USE SIGNAL ;
    SHAPE ABUTMENT ;
    PORT
      LAYER metal3 ;
      RECT 0.000 152.285 0.070 152.355 ;
    END
  END W0_data[6]
  PIN W0_data[7]
    DIRECTION INPUT ;
    USE SIGNAL ;
    SHAPE ABUTMENT ;
    PORT
      LAYER metal3 ;
      RECT 0.000 152.565 0.070 152.635 ;
    END
  END W0_data[7]
  PIN W0_data[8]
    DIRECTION INPUT ;
    USE SIGNAL ;
    SHAPE ABUTMENT ;
    PORT
      LAYER metal3 ;
      RECT 0.000 152.845 0.070 152.915 ;
    END
  END W0_data[8]
  PIN W0_data[9]
    DIRECTION INPUT ;
    USE SIGNAL ;
    SHAPE ABUTMENT ;
    PORT
      LAYER metal3 ;
      RECT 0.000 153.125 0.070 153.195 ;
    END
  END W0_data[9]
  PIN W0_data[10]
    DIRECTION INPUT ;
    USE SIGNAL ;
    SHAPE ABUTMENT ;
    PORT
      LAYER metal3 ;
      RECT 0.000 153.405 0.070 153.475 ;
    END
  END W0_data[10]
  PIN W0_data[11]
    DIRECTION INPUT ;
    USE SIGNAL ;
    SHAPE ABUTMENT ;
    PORT
      LAYER metal3 ;
      RECT 0.000 153.685 0.070 153.755 ;
    END
  END W0_data[11]
  PIN W0_data[12]
    DIRECTION INPUT ;
    USE SIGNAL ;
    SHAPE ABUTMENT ;
    PORT
      LAYER metal3 ;
      RECT 0.000 153.965 0.070 154.035 ;
    END
  END W0_data[12]
  PIN W0_data[13]
    DIRECTION INPUT ;
    USE SIGNAL ;
    SHAPE ABUTMENT ;
    PORT
      LAYER metal3 ;
      RECT 0.000 154.245 0.070 154.315 ;
    END
  END W0_data[13]
  PIN W0_data[14]
    DIRECTION INPUT ;
    USE SIGNAL ;
    SHAPE ABUTMENT ;
    PORT
      LAYER metal3 ;
      RECT 0.000 154.525 0.070 154.595 ;
    END
  END W0_data[14]
  PIN W0_data[15]
    DIRECTION INPUT ;
    USE SIGNAL ;
    SHAPE ABUTMENT ;
    PORT
      LAYER metal3 ;
      RECT 0.000 154.805 0.070 154.875 ;
    END
  END W0_data[15]
  PIN W0_data[16]
    DIRECTION INPUT ;
    USE SIGNAL ;
    SHAPE ABUTMENT ;
    PORT
      LAYER metal3 ;
      RECT 0.000 155.085 0.070 155.155 ;
    END
  END W0_data[16]
  PIN W0_data[17]
    DIRECTION INPUT ;
    USE SIGNAL ;
    SHAPE ABUTMENT ;
    PORT
      LAYER metal3 ;
      RECT 0.000 155.365 0.070 155.435 ;
    END
  END W0_data[17]
  PIN W0_data[18]
    DIRECTION INPUT ;
    USE SIGNAL ;
    SHAPE ABUTMENT ;
    PORT
      LAYER metal3 ;
      RECT 0.000 155.645 0.070 155.715 ;
    END
  END W0_data[18]
  PIN W0_data[19]
    DIRECTION INPUT ;
    USE SIGNAL ;
    SHAPE ABUTMENT ;
    PORT
      LAYER metal3 ;
      RECT 0.000 155.925 0.070 155.995 ;
    END
  END W0_data[19]
  PIN W0_data[20]
    DIRECTION INPUT ;
    USE SIGNAL ;
    SHAPE ABUTMENT ;
    PORT
      LAYER metal3 ;
      RECT 0.000 156.205 0.070 156.275 ;
    END
  END W0_data[20]
  PIN W0_data[21]
    DIRECTION INPUT ;
    USE SIGNAL ;
    SHAPE ABUTMENT ;
    PORT
      LAYER metal3 ;
      RECT 0.000 156.485 0.070 156.555 ;
    END
  END W0_data[21]
  PIN W0_data[22]
    DIRECTION INPUT ;
    USE SIGNAL ;
    SHAPE ABUTMENT ;
    PORT
      LAYER metal3 ;
      RECT 0.000 156.765 0.070 156.835 ;
    END
  END W0_data[22]
  PIN W0_data[23]
    DIRECTION INPUT ;
    USE SIGNAL ;
    SHAPE ABUTMENT ;
    PORT
      LAYER metal3 ;
      RECT 0.000 157.045 0.070 157.115 ;
    END
  END W0_data[23]
  PIN W0_data[24]
    DIRECTION INPUT ;
    USE SIGNAL ;
    SHAPE ABUTMENT ;
    PORT
      LAYER metal3 ;
      RECT 0.000 157.325 0.070 157.395 ;
    END
  END W0_data[24]
  PIN W0_data[25]
    DIRECTION INPUT ;
    USE SIGNAL ;
    SHAPE ABUTMENT ;
    PORT
      LAYER metal3 ;
      RECT 0.000 157.605 0.070 157.675 ;
    END
  END W0_data[25]
  PIN W0_data[26]
    DIRECTION INPUT ;
    USE SIGNAL ;
    SHAPE ABUTMENT ;
    PORT
      LAYER metal3 ;
      RECT 0.000 157.885 0.070 157.955 ;
    END
  END W0_data[26]
  PIN W0_data[27]
    DIRECTION INPUT ;
    USE SIGNAL ;
    SHAPE ABUTMENT ;
    PORT
      LAYER metal3 ;
      RECT 0.000 158.165 0.070 158.235 ;
    END
  END W0_data[27]
  PIN W0_data[28]
    DIRECTION INPUT ;
    USE SIGNAL ;
    SHAPE ABUTMENT ;
    PORT
      LAYER metal3 ;
      RECT 0.000 158.445 0.070 158.515 ;
    END
  END W0_data[28]
  PIN W0_data[29]
    DIRECTION INPUT ;
    USE SIGNAL ;
    SHAPE ABUTMENT ;
    PORT
      LAYER metal3 ;
      RECT 0.000 158.725 0.070 158.795 ;
    END
  END W0_data[29]
  PIN W0_data[30]
    DIRECTION INPUT ;
    USE SIGNAL ;
    SHAPE ABUTMENT ;
    PORT
      LAYER metal3 ;
      RECT 0.000 159.005 0.070 159.075 ;
    END
  END W0_data[30]
  PIN W0_data[31]
    DIRECTION INPUT ;
    USE SIGNAL ;
    SHAPE ABUTMENT ;
    PORT
      LAYER metal3 ;
      RECT 0.000 159.285 0.070 159.355 ;
    END
  END W0_data[31]
  PIN W0_data[32]
    DIRECTION INPUT ;
    USE SIGNAL ;
    SHAPE ABUTMENT ;
    PORT
      LAYER metal3 ;
      RECT 0.000 159.565 0.070 159.635 ;
    END
  END W0_data[32]
  PIN W0_data[33]
    DIRECTION INPUT ;
    USE SIGNAL ;
    SHAPE ABUTMENT ;
    PORT
      LAYER metal3 ;
      RECT 0.000 159.845 0.070 159.915 ;
    END
  END W0_data[33]
  PIN W0_data[34]
    DIRECTION INPUT ;
    USE SIGNAL ;
    SHAPE ABUTMENT ;
    PORT
      LAYER metal3 ;
      RECT 0.000 160.125 0.070 160.195 ;
    END
  END W0_data[34]
  PIN W0_data[35]
    DIRECTION INPUT ;
    USE SIGNAL ;
    SHAPE ABUTMENT ;
    PORT
      LAYER metal3 ;
      RECT 0.000 160.405 0.070 160.475 ;
    END
  END W0_data[35]
  PIN W0_data[36]
    DIRECTION INPUT ;
    USE SIGNAL ;
    SHAPE ABUTMENT ;
    PORT
      LAYER metal3 ;
      RECT 0.000 160.685 0.070 160.755 ;
    END
  END W0_data[36]
  PIN W0_data[37]
    DIRECTION INPUT ;
    USE SIGNAL ;
    SHAPE ABUTMENT ;
    PORT
      LAYER metal3 ;
      RECT 0.000 160.965 0.070 161.035 ;
    END
  END W0_data[37]
  PIN W0_data[38]
    DIRECTION INPUT ;
    USE SIGNAL ;
    SHAPE ABUTMENT ;
    PORT
      LAYER metal3 ;
      RECT 0.000 161.245 0.070 161.315 ;
    END
  END W0_data[38]
  PIN W0_data[39]
    DIRECTION INPUT ;
    USE SIGNAL ;
    SHAPE ABUTMENT ;
    PORT
      LAYER metal3 ;
      RECT 0.000 161.525 0.070 161.595 ;
    END
  END W0_data[39]
  PIN W0_data[40]
    DIRECTION INPUT ;
    USE SIGNAL ;
    SHAPE ABUTMENT ;
    PORT
      LAYER metal3 ;
      RECT 0.000 161.805 0.070 161.875 ;
    END
  END W0_data[40]
  PIN W0_data[41]
    DIRECTION INPUT ;
    USE SIGNAL ;
    SHAPE ABUTMENT ;
    PORT
      LAYER metal3 ;
      RECT 0.000 162.085 0.070 162.155 ;
    END
  END W0_data[41]
  PIN W0_data[42]
    DIRECTION INPUT ;
    USE SIGNAL ;
    SHAPE ABUTMENT ;
    PORT
      LAYER metal3 ;
      RECT 0.000 162.365 0.070 162.435 ;
    END
  END W0_data[42]
  PIN W0_data[43]
    DIRECTION INPUT ;
    USE SIGNAL ;
    SHAPE ABUTMENT ;
    PORT
      LAYER metal3 ;
      RECT 0.000 162.645 0.070 162.715 ;
    END
  END W0_data[43]
  PIN W0_data[44]
    DIRECTION INPUT ;
    USE SIGNAL ;
    SHAPE ABUTMENT ;
    PORT
      LAYER metal3 ;
      RECT 0.000 162.925 0.070 162.995 ;
    END
  END W0_data[44]
  PIN W0_data[45]
    DIRECTION INPUT ;
    USE SIGNAL ;
    SHAPE ABUTMENT ;
    PORT
      LAYER metal3 ;
      RECT 0.000 163.205 0.070 163.275 ;
    END
  END W0_data[45]
  PIN W0_data[46]
    DIRECTION INPUT ;
    USE SIGNAL ;
    SHAPE ABUTMENT ;
    PORT
      LAYER metal3 ;
      RECT 0.000 163.485 0.070 163.555 ;
    END
  END W0_data[46]
  PIN W0_data[47]
    DIRECTION INPUT ;
    USE SIGNAL ;
    SHAPE ABUTMENT ;
    PORT
      LAYER metal3 ;
      RECT 0.000 163.765 0.070 163.835 ;
    END
  END W0_data[47]
  PIN W0_data[48]
    DIRECTION INPUT ;
    USE SIGNAL ;
    SHAPE ABUTMENT ;
    PORT
      LAYER metal3 ;
      RECT 0.000 164.045 0.070 164.115 ;
    END
  END W0_data[48]
  PIN W0_data[49]
    DIRECTION INPUT ;
    USE SIGNAL ;
    SHAPE ABUTMENT ;
    PORT
      LAYER metal3 ;
      RECT 0.000 164.325 0.070 164.395 ;
    END
  END W0_data[49]
  PIN W0_data[50]
    DIRECTION INPUT ;
    USE SIGNAL ;
    SHAPE ABUTMENT ;
    PORT
      LAYER metal3 ;
      RECT 0.000 164.605 0.070 164.675 ;
    END
  END W0_data[50]
  PIN W0_data[51]
    DIRECTION INPUT ;
    USE SIGNAL ;
    SHAPE ABUTMENT ;
    PORT
      LAYER metal3 ;
      RECT 0.000 164.885 0.070 164.955 ;
    END
  END W0_data[51]
  PIN W0_data[52]
    DIRECTION INPUT ;
    USE SIGNAL ;
    SHAPE ABUTMENT ;
    PORT
      LAYER metal3 ;
      RECT 0.000 165.165 0.070 165.235 ;
    END
  END W0_data[52]
  PIN W0_data[53]
    DIRECTION INPUT ;
    USE SIGNAL ;
    SHAPE ABUTMENT ;
    PORT
      LAYER metal3 ;
      RECT 0.000 165.445 0.070 165.515 ;
    END
  END W0_data[53]
  PIN W0_data[54]
    DIRECTION INPUT ;
    USE SIGNAL ;
    SHAPE ABUTMENT ;
    PORT
      LAYER metal3 ;
      RECT 0.000 165.725 0.070 165.795 ;
    END
  END W0_data[54]
  PIN W0_data[55]
    DIRECTION INPUT ;
    USE SIGNAL ;
    SHAPE ABUTMENT ;
    PORT
      LAYER metal3 ;
      RECT 0.000 166.005 0.070 166.075 ;
    END
  END W0_data[55]
  PIN W0_data[56]
    DIRECTION INPUT ;
    USE SIGNAL ;
    SHAPE ABUTMENT ;
    PORT
      LAYER metal3 ;
      RECT 0.000 166.285 0.070 166.355 ;
    END
  END W0_data[56]
  PIN W0_data[57]
    DIRECTION INPUT ;
    USE SIGNAL ;
    SHAPE ABUTMENT ;
    PORT
      LAYER metal3 ;
      RECT 0.000 166.565 0.070 166.635 ;
    END
  END W0_data[57]
  PIN W0_data[58]
    DIRECTION INPUT ;
    USE SIGNAL ;
    SHAPE ABUTMENT ;
    PORT
      LAYER metal3 ;
      RECT 0.000 166.845 0.070 166.915 ;
    END
  END W0_data[58]
  PIN W0_data[59]
    DIRECTION INPUT ;
    USE SIGNAL ;
    SHAPE ABUTMENT ;
    PORT
      LAYER metal3 ;
      RECT 0.000 167.125 0.070 167.195 ;
    END
  END W0_data[59]
  PIN W0_data[60]
    DIRECTION INPUT ;
    USE SIGNAL ;
    SHAPE ABUTMENT ;
    PORT
      LAYER metal3 ;
      RECT 0.000 167.405 0.070 167.475 ;
    END
  END W0_data[60]
  PIN W0_data[61]
    DIRECTION INPUT ;
    USE SIGNAL ;
    SHAPE ABUTMENT ;
    PORT
      LAYER metal3 ;
      RECT 0.000 167.685 0.070 167.755 ;
    END
  END W0_data[61]
  PIN W0_data[62]
    DIRECTION INPUT ;
    USE SIGNAL ;
    SHAPE ABUTMENT ;
    PORT
      LAYER metal3 ;
      RECT 0.000 167.965 0.070 168.035 ;
    END
  END W0_data[62]
  PIN W0_data[63]
    DIRECTION INPUT ;
    USE SIGNAL ;
    SHAPE ABUTMENT ;
    PORT
      LAYER metal3 ;
      RECT 0.000 168.245 0.070 168.315 ;
    END
  END W0_data[63]
  PIN W0_data[64]
    DIRECTION INPUT ;
    USE SIGNAL ;
    SHAPE ABUTMENT ;
    PORT
      LAYER metal3 ;
      RECT 0.000 168.525 0.070 168.595 ;
    END
  END W0_data[64]
  PIN W0_data[65]
    DIRECTION INPUT ;
    USE SIGNAL ;
    SHAPE ABUTMENT ;
    PORT
      LAYER metal3 ;
      RECT 0.000 168.805 0.070 168.875 ;
    END
  END W0_data[65]
  PIN W0_data[66]
    DIRECTION INPUT ;
    USE SIGNAL ;
    SHAPE ABUTMENT ;
    PORT
      LAYER metal3 ;
      RECT 0.000 169.085 0.070 169.155 ;
    END
  END W0_data[66]
  PIN W0_data[67]
    DIRECTION INPUT ;
    USE SIGNAL ;
    SHAPE ABUTMENT ;
    PORT
      LAYER metal3 ;
      RECT 0.000 169.365 0.070 169.435 ;
    END
  END W0_data[67]
  PIN W0_data[68]
    DIRECTION INPUT ;
    USE SIGNAL ;
    SHAPE ABUTMENT ;
    PORT
      LAYER metal3 ;
      RECT 0.000 169.645 0.070 169.715 ;
    END
  END W0_data[68]
  PIN W0_data[69]
    DIRECTION INPUT ;
    USE SIGNAL ;
    SHAPE ABUTMENT ;
    PORT
      LAYER metal3 ;
      RECT 0.000 169.925 0.070 169.995 ;
    END
  END W0_data[69]
  PIN W0_data[70]
    DIRECTION INPUT ;
    USE SIGNAL ;
    SHAPE ABUTMENT ;
    PORT
      LAYER metal3 ;
      RECT 0.000 170.205 0.070 170.275 ;
    END
  END W0_data[70]
  PIN W0_data[71]
    DIRECTION INPUT ;
    USE SIGNAL ;
    SHAPE ABUTMENT ;
    PORT
      LAYER metal3 ;
      RECT 0.000 170.485 0.070 170.555 ;
    END
  END W0_data[71]
  PIN W0_data[72]
    DIRECTION INPUT ;
    USE SIGNAL ;
    SHAPE ABUTMENT ;
    PORT
      LAYER metal3 ;
      RECT 0.000 170.765 0.070 170.835 ;
    END
  END W0_data[72]
  PIN W0_data[73]
    DIRECTION INPUT ;
    USE SIGNAL ;
    SHAPE ABUTMENT ;
    PORT
      LAYER metal3 ;
      RECT 0.000 171.045 0.070 171.115 ;
    END
  END W0_data[73]
  PIN W0_data[74]
    DIRECTION INPUT ;
    USE SIGNAL ;
    SHAPE ABUTMENT ;
    PORT
      LAYER metal3 ;
      RECT 0.000 171.325 0.070 171.395 ;
    END
  END W0_data[74]
  PIN W0_data[75]
    DIRECTION INPUT ;
    USE SIGNAL ;
    SHAPE ABUTMENT ;
    PORT
      LAYER metal3 ;
      RECT 0.000 171.605 0.070 171.675 ;
    END
  END W0_data[75]
  PIN W0_data[76]
    DIRECTION INPUT ;
    USE SIGNAL ;
    SHAPE ABUTMENT ;
    PORT
      LAYER metal3 ;
      RECT 0.000 171.885 0.070 171.955 ;
    END
  END W0_data[76]
  PIN W0_data[77]
    DIRECTION INPUT ;
    USE SIGNAL ;
    SHAPE ABUTMENT ;
    PORT
      LAYER metal3 ;
      RECT 0.000 172.165 0.070 172.235 ;
    END
  END W0_data[77]
  PIN W0_data[78]
    DIRECTION INPUT ;
    USE SIGNAL ;
    SHAPE ABUTMENT ;
    PORT
      LAYER metal3 ;
      RECT 0.000 172.445 0.070 172.515 ;
    END
  END W0_data[78]
  PIN W0_data[79]
    DIRECTION INPUT ;
    USE SIGNAL ;
    SHAPE ABUTMENT ;
    PORT
      LAYER metal3 ;
      RECT 0.000 172.725 0.070 172.795 ;
    END
  END W0_data[79]
  PIN W0_data[80]
    DIRECTION INPUT ;
    USE SIGNAL ;
    SHAPE ABUTMENT ;
    PORT
      LAYER metal3 ;
      RECT 0.000 173.005 0.070 173.075 ;
    END
  END W0_data[80]
  PIN W0_data[81]
    DIRECTION INPUT ;
    USE SIGNAL ;
    SHAPE ABUTMENT ;
    PORT
      LAYER metal3 ;
      RECT 0.000 173.285 0.070 173.355 ;
    END
  END W0_data[81]
  PIN W0_data[82]
    DIRECTION INPUT ;
    USE SIGNAL ;
    SHAPE ABUTMENT ;
    PORT
      LAYER metal3 ;
      RECT 0.000 173.565 0.070 173.635 ;
    END
  END W0_data[82]
  PIN W0_data[83]
    DIRECTION INPUT ;
    USE SIGNAL ;
    SHAPE ABUTMENT ;
    PORT
      LAYER metal3 ;
      RECT 0.000 173.845 0.070 173.915 ;
    END
  END W0_data[83]
  PIN W0_data[84]
    DIRECTION INPUT ;
    USE SIGNAL ;
    SHAPE ABUTMENT ;
    PORT
      LAYER metal3 ;
      RECT 0.000 174.125 0.070 174.195 ;
    END
  END W0_data[84]
  PIN W0_data[85]
    DIRECTION INPUT ;
    USE SIGNAL ;
    SHAPE ABUTMENT ;
    PORT
      LAYER metal3 ;
      RECT 0.000 174.405 0.070 174.475 ;
    END
  END W0_data[85]
  PIN W0_data[86]
    DIRECTION INPUT ;
    USE SIGNAL ;
    SHAPE ABUTMENT ;
    PORT
      LAYER metal3 ;
      RECT 0.000 174.685 0.070 174.755 ;
    END
  END W0_data[86]
  PIN W0_data[87]
    DIRECTION INPUT ;
    USE SIGNAL ;
    SHAPE ABUTMENT ;
    PORT
      LAYER metal3 ;
      RECT 0.000 174.965 0.070 175.035 ;
    END
  END W0_data[87]
  PIN W0_data[88]
    DIRECTION INPUT ;
    USE SIGNAL ;
    SHAPE ABUTMENT ;
    PORT
      LAYER metal3 ;
      RECT 0.000 175.245 0.070 175.315 ;
    END
  END W0_data[88]
  PIN W0_data[89]
    DIRECTION INPUT ;
    USE SIGNAL ;
    SHAPE ABUTMENT ;
    PORT
      LAYER metal3 ;
      RECT 0.000 175.525 0.070 175.595 ;
    END
  END W0_data[89]
  PIN W0_data[90]
    DIRECTION INPUT ;
    USE SIGNAL ;
    SHAPE ABUTMENT ;
    PORT
      LAYER metal3 ;
      RECT 0.000 175.805 0.070 175.875 ;
    END
  END W0_data[90]
  PIN W0_data[91]
    DIRECTION INPUT ;
    USE SIGNAL ;
    SHAPE ABUTMENT ;
    PORT
      LAYER metal3 ;
      RECT 0.000 176.085 0.070 176.155 ;
    END
  END W0_data[91]
  PIN W0_data[92]
    DIRECTION INPUT ;
    USE SIGNAL ;
    SHAPE ABUTMENT ;
    PORT
      LAYER metal3 ;
      RECT 0.000 176.365 0.070 176.435 ;
    END
  END W0_data[92]
  PIN W0_data[93]
    DIRECTION INPUT ;
    USE SIGNAL ;
    SHAPE ABUTMENT ;
    PORT
      LAYER metal3 ;
      RECT 0.000 176.645 0.070 176.715 ;
    END
  END W0_data[93]
  PIN W0_data[94]
    DIRECTION INPUT ;
    USE SIGNAL ;
    SHAPE ABUTMENT ;
    PORT
      LAYER metal3 ;
      RECT 0.000 176.925 0.070 176.995 ;
    END
  END W0_data[94]
  PIN W0_data[95]
    DIRECTION INPUT ;
    USE SIGNAL ;
    SHAPE ABUTMENT ;
    PORT
      LAYER metal3 ;
      RECT 0.000 177.205 0.070 177.275 ;
    END
  END W0_data[95]
  PIN W0_data[96]
    DIRECTION INPUT ;
    USE SIGNAL ;
    SHAPE ABUTMENT ;
    PORT
      LAYER metal3 ;
      RECT 0.000 177.485 0.070 177.555 ;
    END
  END W0_data[96]
  PIN W0_data[97]
    DIRECTION INPUT ;
    USE SIGNAL ;
    SHAPE ABUTMENT ;
    PORT
      LAYER metal3 ;
      RECT 0.000 177.765 0.070 177.835 ;
    END
  END W0_data[97]
  PIN W0_data[98]
    DIRECTION INPUT ;
    USE SIGNAL ;
    SHAPE ABUTMENT ;
    PORT
      LAYER metal3 ;
      RECT 0.000 178.045 0.070 178.115 ;
    END
  END W0_data[98]
  PIN W0_data[99]
    DIRECTION INPUT ;
    USE SIGNAL ;
    SHAPE ABUTMENT ;
    PORT
      LAYER metal3 ;
      RECT 0.000 178.325 0.070 178.395 ;
    END
  END W0_data[99]
  PIN W0_data[100]
    DIRECTION INPUT ;
    USE SIGNAL ;
    SHAPE ABUTMENT ;
    PORT
      LAYER metal3 ;
      RECT 0.000 178.605 0.070 178.675 ;
    END
  END W0_data[100]
  PIN W0_data[101]
    DIRECTION INPUT ;
    USE SIGNAL ;
    SHAPE ABUTMENT ;
    PORT
      LAYER metal3 ;
      RECT 0.000 178.885 0.070 178.955 ;
    END
  END W0_data[101]
  PIN W0_data[102]
    DIRECTION INPUT ;
    USE SIGNAL ;
    SHAPE ABUTMENT ;
    PORT
      LAYER metal3 ;
      RECT 0.000 179.165 0.070 179.235 ;
    END
  END W0_data[102]
  PIN W0_data[103]
    DIRECTION INPUT ;
    USE SIGNAL ;
    SHAPE ABUTMENT ;
    PORT
      LAYER metal3 ;
      RECT 0.000 179.445 0.070 179.515 ;
    END
  END W0_data[103]
  PIN W0_data[104]
    DIRECTION INPUT ;
    USE SIGNAL ;
    SHAPE ABUTMENT ;
    PORT
      LAYER metal3 ;
      RECT 0.000 179.725 0.070 179.795 ;
    END
  END W0_data[104]
  PIN W0_data[105]
    DIRECTION INPUT ;
    USE SIGNAL ;
    SHAPE ABUTMENT ;
    PORT
      LAYER metal3 ;
      RECT 0.000 180.005 0.070 180.075 ;
    END
  END W0_data[105]
  PIN W0_data[106]
    DIRECTION INPUT ;
    USE SIGNAL ;
    SHAPE ABUTMENT ;
    PORT
      LAYER metal3 ;
      RECT 0.000 180.285 0.070 180.355 ;
    END
  END W0_data[106]
  PIN W0_data[107]
    DIRECTION INPUT ;
    USE SIGNAL ;
    SHAPE ABUTMENT ;
    PORT
      LAYER metal3 ;
      RECT 0.000 180.565 0.070 180.635 ;
    END
  END W0_data[107]
  PIN W0_data[108]
    DIRECTION INPUT ;
    USE SIGNAL ;
    SHAPE ABUTMENT ;
    PORT
      LAYER metal3 ;
      RECT 0.000 180.845 0.070 180.915 ;
    END
  END W0_data[108]
  PIN W0_data[109]
    DIRECTION INPUT ;
    USE SIGNAL ;
    SHAPE ABUTMENT ;
    PORT
      LAYER metal3 ;
      RECT 0.000 181.125 0.070 181.195 ;
    END
  END W0_data[109]
  PIN W0_data[110]
    DIRECTION INPUT ;
    USE SIGNAL ;
    SHAPE ABUTMENT ;
    PORT
      LAYER metal3 ;
      RECT 0.000 181.405 0.070 181.475 ;
    END
  END W0_data[110]
  PIN W0_data[111]
    DIRECTION INPUT ;
    USE SIGNAL ;
    SHAPE ABUTMENT ;
    PORT
      LAYER metal3 ;
      RECT 0.000 181.685 0.070 181.755 ;
    END
  END W0_data[111]
  PIN W0_data[112]
    DIRECTION INPUT ;
    USE SIGNAL ;
    SHAPE ABUTMENT ;
    PORT
      LAYER metal3 ;
      RECT 0.000 181.965 0.070 182.035 ;
    END
  END W0_data[112]
  PIN W0_data[113]
    DIRECTION INPUT ;
    USE SIGNAL ;
    SHAPE ABUTMENT ;
    PORT
      LAYER metal3 ;
      RECT 0.000 182.245 0.070 182.315 ;
    END
  END W0_data[113]
  PIN W0_data[114]
    DIRECTION INPUT ;
    USE SIGNAL ;
    SHAPE ABUTMENT ;
    PORT
      LAYER metal3 ;
      RECT 0.000 182.525 0.070 182.595 ;
    END
  END W0_data[114]
  PIN W0_data[115]
    DIRECTION INPUT ;
    USE SIGNAL ;
    SHAPE ABUTMENT ;
    PORT
      LAYER metal3 ;
      RECT 0.000 182.805 0.070 182.875 ;
    END
  END W0_data[115]
  PIN W0_data[116]
    DIRECTION INPUT ;
    USE SIGNAL ;
    SHAPE ABUTMENT ;
    PORT
      LAYER metal3 ;
      RECT 0.000 183.085 0.070 183.155 ;
    END
  END W0_data[116]
  PIN W0_data[117]
    DIRECTION INPUT ;
    USE SIGNAL ;
    SHAPE ABUTMENT ;
    PORT
      LAYER metal3 ;
      RECT 0.000 183.365 0.070 183.435 ;
    END
  END W0_data[117]
  PIN W0_data[118]
    DIRECTION INPUT ;
    USE SIGNAL ;
    SHAPE ABUTMENT ;
    PORT
      LAYER metal3 ;
      RECT 0.000 183.645 0.070 183.715 ;
    END
  END W0_data[118]
  PIN W0_data[119]
    DIRECTION INPUT ;
    USE SIGNAL ;
    SHAPE ABUTMENT ;
    PORT
      LAYER metal3 ;
      RECT 0.000 183.925 0.070 183.995 ;
    END
  END W0_data[119]
  PIN W0_data[120]
    DIRECTION INPUT ;
    USE SIGNAL ;
    SHAPE ABUTMENT ;
    PORT
      LAYER metal3 ;
      RECT 0.000 184.205 0.070 184.275 ;
    END
  END W0_data[120]
  PIN W0_data[121]
    DIRECTION INPUT ;
    USE SIGNAL ;
    SHAPE ABUTMENT ;
    PORT
      LAYER metal3 ;
      RECT 0.000 184.485 0.070 184.555 ;
    END
  END W0_data[121]
  PIN W0_data[122]
    DIRECTION INPUT ;
    USE SIGNAL ;
    SHAPE ABUTMENT ;
    PORT
      LAYER metal3 ;
      RECT 0.000 184.765 0.070 184.835 ;
    END
  END W0_data[122]
  PIN W0_data[123]
    DIRECTION INPUT ;
    USE SIGNAL ;
    SHAPE ABUTMENT ;
    PORT
      LAYER metal3 ;
      RECT 0.000 185.045 0.070 185.115 ;
    END
  END W0_data[123]
  PIN W0_data[124]
    DIRECTION INPUT ;
    USE SIGNAL ;
    SHAPE ABUTMENT ;
    PORT
      LAYER metal3 ;
      RECT 0.000 185.325 0.070 185.395 ;
    END
  END W0_data[124]
  PIN W0_data[125]
    DIRECTION INPUT ;
    USE SIGNAL ;
    SHAPE ABUTMENT ;
    PORT
      LAYER metal3 ;
      RECT 0.000 185.605 0.070 185.675 ;
    END
  END W0_data[125]
  PIN W0_data[126]
    DIRECTION INPUT ;
    USE SIGNAL ;
    SHAPE ABUTMENT ;
    PORT
      LAYER metal3 ;
      RECT 0.000 185.885 0.070 185.955 ;
    END
  END W0_data[126]
  PIN W0_data[127]
    DIRECTION INPUT ;
    USE SIGNAL ;
    SHAPE ABUTMENT ;
    PORT
      LAYER metal3 ;
      RECT 0.000 186.165 0.070 186.235 ;
    END
  END W0_data[127]
  PIN W0_data[128]
    DIRECTION INPUT ;
    USE SIGNAL ;
    SHAPE ABUTMENT ;
    PORT
      LAYER metal3 ;
      RECT 0.000 186.445 0.070 186.515 ;
    END
  END W0_data[128]
  PIN W0_data[129]
    DIRECTION INPUT ;
    USE SIGNAL ;
    SHAPE ABUTMENT ;
    PORT
      LAYER metal3 ;
      RECT 0.000 186.725 0.070 186.795 ;
    END
  END W0_data[129]
  PIN W0_data[130]
    DIRECTION INPUT ;
    USE SIGNAL ;
    SHAPE ABUTMENT ;
    PORT
      LAYER metal3 ;
      RECT 0.000 187.005 0.070 187.075 ;
    END
  END W0_data[130]
  PIN W0_data[131]
    DIRECTION INPUT ;
    USE SIGNAL ;
    SHAPE ABUTMENT ;
    PORT
      LAYER metal3 ;
      RECT 0.000 187.285 0.070 187.355 ;
    END
  END W0_data[131]
  PIN W0_data[132]
    DIRECTION INPUT ;
    USE SIGNAL ;
    SHAPE ABUTMENT ;
    PORT
      LAYER metal3 ;
      RECT 0.000 187.565 0.070 187.635 ;
    END
  END W0_data[132]
  PIN W0_data[133]
    DIRECTION INPUT ;
    USE SIGNAL ;
    SHAPE ABUTMENT ;
    PORT
      LAYER metal3 ;
      RECT 0.000 187.845 0.070 187.915 ;
    END
  END W0_data[133]
  PIN W0_data[134]
    DIRECTION INPUT ;
    USE SIGNAL ;
    SHAPE ABUTMENT ;
    PORT
      LAYER metal3 ;
      RECT 0.000 188.125 0.070 188.195 ;
    END
  END W0_data[134]
  PIN W0_data[135]
    DIRECTION INPUT ;
    USE SIGNAL ;
    SHAPE ABUTMENT ;
    PORT
      LAYER metal3 ;
      RECT 0.000 188.405 0.070 188.475 ;
    END
  END W0_data[135]
  PIN W0_data[136]
    DIRECTION INPUT ;
    USE SIGNAL ;
    SHAPE ABUTMENT ;
    PORT
      LAYER metal3 ;
      RECT 0.000 188.685 0.070 188.755 ;
    END
  END W0_data[136]
  PIN W0_data[137]
    DIRECTION INPUT ;
    USE SIGNAL ;
    SHAPE ABUTMENT ;
    PORT
      LAYER metal3 ;
      RECT 0.000 188.965 0.070 189.035 ;
    END
  END W0_data[137]
  PIN W0_data[138]
    DIRECTION INPUT ;
    USE SIGNAL ;
    SHAPE ABUTMENT ;
    PORT
      LAYER metal3 ;
      RECT 0.000 189.245 0.070 189.315 ;
    END
  END W0_data[138]
  PIN W0_data[139]
    DIRECTION INPUT ;
    USE SIGNAL ;
    SHAPE ABUTMENT ;
    PORT
      LAYER metal3 ;
      RECT 0.000 189.525 0.070 189.595 ;
    END
  END W0_data[139]
  PIN W0_data[140]
    DIRECTION INPUT ;
    USE SIGNAL ;
    SHAPE ABUTMENT ;
    PORT
      LAYER metal3 ;
      RECT 0.000 189.805 0.070 189.875 ;
    END
  END W0_data[140]
  PIN W0_data[141]
    DIRECTION INPUT ;
    USE SIGNAL ;
    SHAPE ABUTMENT ;
    PORT
      LAYER metal3 ;
      RECT 0.000 190.085 0.070 190.155 ;
    END
  END W0_data[141]
  PIN W0_data[142]
    DIRECTION INPUT ;
    USE SIGNAL ;
    SHAPE ABUTMENT ;
    PORT
      LAYER metal3 ;
      RECT 0.000 190.365 0.070 190.435 ;
    END
  END W0_data[142]
  PIN W0_data[143]
    DIRECTION INPUT ;
    USE SIGNAL ;
    SHAPE ABUTMENT ;
    PORT
      LAYER metal3 ;
      RECT 0.000 190.645 0.070 190.715 ;
    END
  END W0_data[143]
  PIN W0_data[144]
    DIRECTION INPUT ;
    USE SIGNAL ;
    SHAPE ABUTMENT ;
    PORT
      LAYER metal3 ;
      RECT 0.000 190.925 0.070 190.995 ;
    END
  END W0_data[144]
  PIN W0_data[145]
    DIRECTION INPUT ;
    USE SIGNAL ;
    SHAPE ABUTMENT ;
    PORT
      LAYER metal3 ;
      RECT 0.000 191.205 0.070 191.275 ;
    END
  END W0_data[145]
  PIN W0_data[146]
    DIRECTION INPUT ;
    USE SIGNAL ;
    SHAPE ABUTMENT ;
    PORT
      LAYER metal3 ;
      RECT 0.000 191.485 0.070 191.555 ;
    END
  END W0_data[146]
  PIN W0_data[147]
    DIRECTION INPUT ;
    USE SIGNAL ;
    SHAPE ABUTMENT ;
    PORT
      LAYER metal3 ;
      RECT 0.000 191.765 0.070 191.835 ;
    END
  END W0_data[147]
  PIN W0_data[148]
    DIRECTION INPUT ;
    USE SIGNAL ;
    SHAPE ABUTMENT ;
    PORT
      LAYER metal3 ;
      RECT 0.000 192.045 0.070 192.115 ;
    END
  END W0_data[148]
  PIN W0_data[149]
    DIRECTION INPUT ;
    USE SIGNAL ;
    SHAPE ABUTMENT ;
    PORT
      LAYER metal3 ;
      RECT 0.000 192.325 0.070 192.395 ;
    END
  END W0_data[149]
  PIN W0_data[150]
    DIRECTION INPUT ;
    USE SIGNAL ;
    SHAPE ABUTMENT ;
    PORT
      LAYER metal3 ;
      RECT 0.000 192.605 0.070 192.675 ;
    END
  END W0_data[150]
  PIN W0_data[151]
    DIRECTION INPUT ;
    USE SIGNAL ;
    SHAPE ABUTMENT ;
    PORT
      LAYER metal3 ;
      RECT 0.000 192.885 0.070 192.955 ;
    END
  END W0_data[151]
  PIN W0_data[152]
    DIRECTION INPUT ;
    USE SIGNAL ;
    SHAPE ABUTMENT ;
    PORT
      LAYER metal3 ;
      RECT 0.000 193.165 0.070 193.235 ;
    END
  END W0_data[152]
  PIN W0_data[153]
    DIRECTION INPUT ;
    USE SIGNAL ;
    SHAPE ABUTMENT ;
    PORT
      LAYER metal3 ;
      RECT 0.000 193.445 0.070 193.515 ;
    END
  END W0_data[153]
  PIN W0_data[154]
    DIRECTION INPUT ;
    USE SIGNAL ;
    SHAPE ABUTMENT ;
    PORT
      LAYER metal3 ;
      RECT 0.000 193.725 0.070 193.795 ;
    END
  END W0_data[154]
  PIN W0_data[155]
    DIRECTION INPUT ;
    USE SIGNAL ;
    SHAPE ABUTMENT ;
    PORT
      LAYER metal3 ;
      RECT 0.000 194.005 0.070 194.075 ;
    END
  END W0_data[155]
  PIN W0_data[156]
    DIRECTION INPUT ;
    USE SIGNAL ;
    SHAPE ABUTMENT ;
    PORT
      LAYER metal3 ;
      RECT 0.000 194.285 0.070 194.355 ;
    END
  END W0_data[156]
  PIN W0_data[157]
    DIRECTION INPUT ;
    USE SIGNAL ;
    SHAPE ABUTMENT ;
    PORT
      LAYER metal3 ;
      RECT 0.000 194.565 0.070 194.635 ;
    END
  END W0_data[157]
  PIN W0_data[158]
    DIRECTION INPUT ;
    USE SIGNAL ;
    SHAPE ABUTMENT ;
    PORT
      LAYER metal3 ;
      RECT 0.000 194.845 0.070 194.915 ;
    END
  END W0_data[158]
  PIN W0_data[159]
    DIRECTION INPUT ;
    USE SIGNAL ;
    SHAPE ABUTMENT ;
    PORT
      LAYER metal3 ;
      RECT 0.000 195.125 0.070 195.195 ;
    END
  END W0_data[159]
  PIN W0_data[160]
    DIRECTION INPUT ;
    USE SIGNAL ;
    SHAPE ABUTMENT ;
    PORT
      LAYER metal3 ;
      RECT 0.000 195.405 0.070 195.475 ;
    END
  END W0_data[160]
  PIN W0_data[161]
    DIRECTION INPUT ;
    USE SIGNAL ;
    SHAPE ABUTMENT ;
    PORT
      LAYER metal3 ;
      RECT 0.000 195.685 0.070 195.755 ;
    END
  END W0_data[161]
  PIN W0_data[162]
    DIRECTION INPUT ;
    USE SIGNAL ;
    SHAPE ABUTMENT ;
    PORT
      LAYER metal3 ;
      RECT 0.000 195.965 0.070 196.035 ;
    END
  END W0_data[162]
  PIN W0_data[163]
    DIRECTION INPUT ;
    USE SIGNAL ;
    SHAPE ABUTMENT ;
    PORT
      LAYER metal3 ;
      RECT 0.000 196.245 0.070 196.315 ;
    END
  END W0_data[163]
  PIN W0_data[164]
    DIRECTION INPUT ;
    USE SIGNAL ;
    SHAPE ABUTMENT ;
    PORT
      LAYER metal3 ;
      RECT 0.000 196.525 0.070 196.595 ;
    END
  END W0_data[164]
  PIN W0_data[165]
    DIRECTION INPUT ;
    USE SIGNAL ;
    SHAPE ABUTMENT ;
    PORT
      LAYER metal3 ;
      RECT 0.000 196.805 0.070 196.875 ;
    END
  END W0_data[165]
  PIN W0_data[166]
    DIRECTION INPUT ;
    USE SIGNAL ;
    SHAPE ABUTMENT ;
    PORT
      LAYER metal3 ;
      RECT 0.000 197.085 0.070 197.155 ;
    END
  END W0_data[166]
  PIN W0_data[167]
    DIRECTION INPUT ;
    USE SIGNAL ;
    SHAPE ABUTMENT ;
    PORT
      LAYER metal3 ;
      RECT 0.000 197.365 0.070 197.435 ;
    END
  END W0_data[167]
  PIN W0_data[168]
    DIRECTION INPUT ;
    USE SIGNAL ;
    SHAPE ABUTMENT ;
    PORT
      LAYER metal3 ;
      RECT 0.000 197.645 0.070 197.715 ;
    END
  END W0_data[168]
  PIN W0_data[169]
    DIRECTION INPUT ;
    USE SIGNAL ;
    SHAPE ABUTMENT ;
    PORT
      LAYER metal3 ;
      RECT 0.000 197.925 0.070 197.995 ;
    END
  END W0_data[169]
  PIN W0_data[170]
    DIRECTION INPUT ;
    USE SIGNAL ;
    SHAPE ABUTMENT ;
    PORT
      LAYER metal3 ;
      RECT 0.000 198.205 0.070 198.275 ;
    END
  END W0_data[170]
  PIN W0_data[171]
    DIRECTION INPUT ;
    USE SIGNAL ;
    SHAPE ABUTMENT ;
    PORT
      LAYER metal3 ;
      RECT 0.000 198.485 0.070 198.555 ;
    END
  END W0_data[171]
  PIN W0_data[172]
    DIRECTION INPUT ;
    USE SIGNAL ;
    SHAPE ABUTMENT ;
    PORT
      LAYER metal3 ;
      RECT 0.000 198.765 0.070 198.835 ;
    END
  END W0_data[172]
  PIN W0_data[173]
    DIRECTION INPUT ;
    USE SIGNAL ;
    SHAPE ABUTMENT ;
    PORT
      LAYER metal3 ;
      RECT 0.000 199.045 0.070 199.115 ;
    END
  END W0_data[173]
  PIN W0_data[174]
    DIRECTION INPUT ;
    USE SIGNAL ;
    SHAPE ABUTMENT ;
    PORT
      LAYER metal3 ;
      RECT 0.000 199.325 0.070 199.395 ;
    END
  END W0_data[174]
  PIN W0_data[175]
    DIRECTION INPUT ;
    USE SIGNAL ;
    SHAPE ABUTMENT ;
    PORT
      LAYER metal3 ;
      RECT 0.000 199.605 0.070 199.675 ;
    END
  END W0_data[175]
  PIN W0_data[176]
    DIRECTION INPUT ;
    USE SIGNAL ;
    SHAPE ABUTMENT ;
    PORT
      LAYER metal3 ;
      RECT 0.000 199.885 0.070 199.955 ;
    END
  END W0_data[176]
  PIN W0_data[177]
    DIRECTION INPUT ;
    USE SIGNAL ;
    SHAPE ABUTMENT ;
    PORT
      LAYER metal3 ;
      RECT 0.000 200.165 0.070 200.235 ;
    END
  END W0_data[177]
  PIN W0_data[178]
    DIRECTION INPUT ;
    USE SIGNAL ;
    SHAPE ABUTMENT ;
    PORT
      LAYER metal3 ;
      RECT 0.000 200.445 0.070 200.515 ;
    END
  END W0_data[178]
  PIN W0_data[179]
    DIRECTION INPUT ;
    USE SIGNAL ;
    SHAPE ABUTMENT ;
    PORT
      LAYER metal3 ;
      RECT 0.000 200.725 0.070 200.795 ;
    END
  END W0_data[179]
  PIN W0_data[180]
    DIRECTION INPUT ;
    USE SIGNAL ;
    SHAPE ABUTMENT ;
    PORT
      LAYER metal3 ;
      RECT 0.000 201.005 0.070 201.075 ;
    END
  END W0_data[180]
  PIN W0_data[181]
    DIRECTION INPUT ;
    USE SIGNAL ;
    SHAPE ABUTMENT ;
    PORT
      LAYER metal3 ;
      RECT 0.000 201.285 0.070 201.355 ;
    END
  END W0_data[181]
  PIN W0_data[182]
    DIRECTION INPUT ;
    USE SIGNAL ;
    SHAPE ABUTMENT ;
    PORT
      LAYER metal3 ;
      RECT 0.000 201.565 0.070 201.635 ;
    END
  END W0_data[182]
  PIN W0_data[183]
    DIRECTION INPUT ;
    USE SIGNAL ;
    SHAPE ABUTMENT ;
    PORT
      LAYER metal3 ;
      RECT 0.000 201.845 0.070 201.915 ;
    END
  END W0_data[183]
  PIN W0_data[184]
    DIRECTION INPUT ;
    USE SIGNAL ;
    SHAPE ABUTMENT ;
    PORT
      LAYER metal3 ;
      RECT 0.000 202.125 0.070 202.195 ;
    END
  END W0_data[184]
  PIN W0_data[185]
    DIRECTION INPUT ;
    USE SIGNAL ;
    SHAPE ABUTMENT ;
    PORT
      LAYER metal3 ;
      RECT 0.000 202.405 0.070 202.475 ;
    END
  END W0_data[185]
  PIN W0_data[186]
    DIRECTION INPUT ;
    USE SIGNAL ;
    SHAPE ABUTMENT ;
    PORT
      LAYER metal3 ;
      RECT 0.000 202.685 0.070 202.755 ;
    END
  END W0_data[186]
  PIN W0_data[187]
    DIRECTION INPUT ;
    USE SIGNAL ;
    SHAPE ABUTMENT ;
    PORT
      LAYER metal3 ;
      RECT 0.000 202.965 0.070 203.035 ;
    END
  END W0_data[187]
  PIN W0_data[188]
    DIRECTION INPUT ;
    USE SIGNAL ;
    SHAPE ABUTMENT ;
    PORT
      LAYER metal3 ;
      RECT 0.000 203.245 0.070 203.315 ;
    END
  END W0_data[188]
  PIN W0_data[189]
    DIRECTION INPUT ;
    USE SIGNAL ;
    SHAPE ABUTMENT ;
    PORT
      LAYER metal3 ;
      RECT 0.000 203.525 0.070 203.595 ;
    END
  END W0_data[189]
  PIN W0_data[190]
    DIRECTION INPUT ;
    USE SIGNAL ;
    SHAPE ABUTMENT ;
    PORT
      LAYER metal3 ;
      RECT 0.000 203.805 0.070 203.875 ;
    END
  END W0_data[190]
  PIN W0_data[191]
    DIRECTION INPUT ;
    USE SIGNAL ;
    SHAPE ABUTMENT ;
    PORT
      LAYER metal3 ;
      RECT 0.000 204.085 0.070 204.155 ;
    END
  END W0_data[191]
  PIN W0_data[192]
    DIRECTION INPUT ;
    USE SIGNAL ;
    SHAPE ABUTMENT ;
    PORT
      LAYER metal3 ;
      RECT 0.000 204.365 0.070 204.435 ;
    END
  END W0_data[192]
  PIN W0_data[193]
    DIRECTION INPUT ;
    USE SIGNAL ;
    SHAPE ABUTMENT ;
    PORT
      LAYER metal3 ;
      RECT 0.000 204.645 0.070 204.715 ;
    END
  END W0_data[193]
  PIN W0_data[194]
    DIRECTION INPUT ;
    USE SIGNAL ;
    SHAPE ABUTMENT ;
    PORT
      LAYER metal3 ;
      RECT 0.000 204.925 0.070 204.995 ;
    END
  END W0_data[194]
  PIN W0_data[195]
    DIRECTION INPUT ;
    USE SIGNAL ;
    SHAPE ABUTMENT ;
    PORT
      LAYER metal3 ;
      RECT 0.000 205.205 0.070 205.275 ;
    END
  END W0_data[195]
  PIN W0_data[196]
    DIRECTION INPUT ;
    USE SIGNAL ;
    SHAPE ABUTMENT ;
    PORT
      LAYER metal3 ;
      RECT 0.000 205.485 0.070 205.555 ;
    END
  END W0_data[196]
  PIN W0_data[197]
    DIRECTION INPUT ;
    USE SIGNAL ;
    SHAPE ABUTMENT ;
    PORT
      LAYER metal3 ;
      RECT 0.000 205.765 0.070 205.835 ;
    END
  END W0_data[197]
  PIN W0_data[198]
    DIRECTION INPUT ;
    USE SIGNAL ;
    SHAPE ABUTMENT ;
    PORT
      LAYER metal3 ;
      RECT 0.000 206.045 0.070 206.115 ;
    END
  END W0_data[198]
  PIN W0_data[199]
    DIRECTION INPUT ;
    USE SIGNAL ;
    SHAPE ABUTMENT ;
    PORT
      LAYER metal3 ;
      RECT 0.000 206.325 0.070 206.395 ;
    END
  END W0_data[199]
  PIN W0_data[200]
    DIRECTION INPUT ;
    USE SIGNAL ;
    SHAPE ABUTMENT ;
    PORT
      LAYER metal3 ;
      RECT 0.000 206.605 0.070 206.675 ;
    END
  END W0_data[200]
  PIN W0_data[201]
    DIRECTION INPUT ;
    USE SIGNAL ;
    SHAPE ABUTMENT ;
    PORT
      LAYER metal3 ;
      RECT 0.000 206.885 0.070 206.955 ;
    END
  END W0_data[201]
  PIN W0_data[202]
    DIRECTION INPUT ;
    USE SIGNAL ;
    SHAPE ABUTMENT ;
    PORT
      LAYER metal3 ;
      RECT 0.000 207.165 0.070 207.235 ;
    END
  END W0_data[202]
  PIN W0_data[203]
    DIRECTION INPUT ;
    USE SIGNAL ;
    SHAPE ABUTMENT ;
    PORT
      LAYER metal3 ;
      RECT 0.000 207.445 0.070 207.515 ;
    END
  END W0_data[203]
  PIN W0_data[204]
    DIRECTION INPUT ;
    USE SIGNAL ;
    SHAPE ABUTMENT ;
    PORT
      LAYER metal3 ;
      RECT 0.000 207.725 0.070 207.795 ;
    END
  END W0_data[204]
  PIN W0_data[205]
    DIRECTION INPUT ;
    USE SIGNAL ;
    SHAPE ABUTMENT ;
    PORT
      LAYER metal3 ;
      RECT 0.000 208.005 0.070 208.075 ;
    END
  END W0_data[205]
  PIN W0_data[206]
    DIRECTION INPUT ;
    USE SIGNAL ;
    SHAPE ABUTMENT ;
    PORT
      LAYER metal3 ;
      RECT 0.000 208.285 0.070 208.355 ;
    END
  END W0_data[206]
  PIN W0_data[207]
    DIRECTION INPUT ;
    USE SIGNAL ;
    SHAPE ABUTMENT ;
    PORT
      LAYER metal3 ;
      RECT 0.000 208.565 0.070 208.635 ;
    END
  END W0_data[207]
  PIN W0_data[208]
    DIRECTION INPUT ;
    USE SIGNAL ;
    SHAPE ABUTMENT ;
    PORT
      LAYER metal3 ;
      RECT 0.000 208.845 0.070 208.915 ;
    END
  END W0_data[208]
  PIN W0_data[209]
    DIRECTION INPUT ;
    USE SIGNAL ;
    SHAPE ABUTMENT ;
    PORT
      LAYER metal3 ;
      RECT 0.000 209.125 0.070 209.195 ;
    END
  END W0_data[209]
  PIN W0_data[210]
    DIRECTION INPUT ;
    USE SIGNAL ;
    SHAPE ABUTMENT ;
    PORT
      LAYER metal3 ;
      RECT 0.000 209.405 0.070 209.475 ;
    END
  END W0_data[210]
  PIN W0_data[211]
    DIRECTION INPUT ;
    USE SIGNAL ;
    SHAPE ABUTMENT ;
    PORT
      LAYER metal3 ;
      RECT 0.000 209.685 0.070 209.755 ;
    END
  END W0_data[211]
  PIN W0_data[212]
    DIRECTION INPUT ;
    USE SIGNAL ;
    SHAPE ABUTMENT ;
    PORT
      LAYER metal3 ;
      RECT 0.000 209.965 0.070 210.035 ;
    END
  END W0_data[212]
  PIN W0_data[213]
    DIRECTION INPUT ;
    USE SIGNAL ;
    SHAPE ABUTMENT ;
    PORT
      LAYER metal3 ;
      RECT 0.000 210.245 0.070 210.315 ;
    END
  END W0_data[213]
  PIN W0_data[214]
    DIRECTION INPUT ;
    USE SIGNAL ;
    SHAPE ABUTMENT ;
    PORT
      LAYER metal3 ;
      RECT 0.000 210.525 0.070 210.595 ;
    END
  END W0_data[214]
  PIN W0_data[215]
    DIRECTION INPUT ;
    USE SIGNAL ;
    SHAPE ABUTMENT ;
    PORT
      LAYER metal3 ;
      RECT 0.000 210.805 0.070 210.875 ;
    END
  END W0_data[215]
  PIN W0_data[216]
    DIRECTION INPUT ;
    USE SIGNAL ;
    SHAPE ABUTMENT ;
    PORT
      LAYER metal3 ;
      RECT 0.000 211.085 0.070 211.155 ;
    END
  END W0_data[216]
  PIN W0_data[217]
    DIRECTION INPUT ;
    USE SIGNAL ;
    SHAPE ABUTMENT ;
    PORT
      LAYER metal3 ;
      RECT 0.000 211.365 0.070 211.435 ;
    END
  END W0_data[217]
  PIN W0_data[218]
    DIRECTION INPUT ;
    USE SIGNAL ;
    SHAPE ABUTMENT ;
    PORT
      LAYER metal3 ;
      RECT 0.000 211.645 0.070 211.715 ;
    END
  END W0_data[218]
  PIN W0_data[219]
    DIRECTION INPUT ;
    USE SIGNAL ;
    SHAPE ABUTMENT ;
    PORT
      LAYER metal3 ;
      RECT 0.000 211.925 0.070 211.995 ;
    END
  END W0_data[219]
  PIN W0_data[220]
    DIRECTION INPUT ;
    USE SIGNAL ;
    SHAPE ABUTMENT ;
    PORT
      LAYER metal3 ;
      RECT 0.000 212.205 0.070 212.275 ;
    END
  END W0_data[220]
  PIN W0_data[221]
    DIRECTION INPUT ;
    USE SIGNAL ;
    SHAPE ABUTMENT ;
    PORT
      LAYER metal3 ;
      RECT 0.000 212.485 0.070 212.555 ;
    END
  END W0_data[221]
  PIN W0_data[222]
    DIRECTION INPUT ;
    USE SIGNAL ;
    SHAPE ABUTMENT ;
    PORT
      LAYER metal3 ;
      RECT 0.000 212.765 0.070 212.835 ;
    END
  END W0_data[222]
  PIN W0_data[223]
    DIRECTION INPUT ;
    USE SIGNAL ;
    SHAPE ABUTMENT ;
    PORT
      LAYER metal3 ;
      RECT 0.000 213.045 0.070 213.115 ;
    END
  END W0_data[223]
  PIN W0_data[224]
    DIRECTION INPUT ;
    USE SIGNAL ;
    SHAPE ABUTMENT ;
    PORT
      LAYER metal3 ;
      RECT 0.000 213.325 0.070 213.395 ;
    END
  END W0_data[224]
  PIN W0_data[225]
    DIRECTION INPUT ;
    USE SIGNAL ;
    SHAPE ABUTMENT ;
    PORT
      LAYER metal3 ;
      RECT 0.000 213.605 0.070 213.675 ;
    END
  END W0_data[225]
  PIN W0_data[226]
    DIRECTION INPUT ;
    USE SIGNAL ;
    SHAPE ABUTMENT ;
    PORT
      LAYER metal3 ;
      RECT 0.000 213.885 0.070 213.955 ;
    END
  END W0_data[226]
  PIN W0_data[227]
    DIRECTION INPUT ;
    USE SIGNAL ;
    SHAPE ABUTMENT ;
    PORT
      LAYER metal3 ;
      RECT 0.000 214.165 0.070 214.235 ;
    END
  END W0_data[227]
  PIN W0_data[228]
    DIRECTION INPUT ;
    USE SIGNAL ;
    SHAPE ABUTMENT ;
    PORT
      LAYER metal3 ;
      RECT 0.000 214.445 0.070 214.515 ;
    END
  END W0_data[228]
  PIN W0_data[229]
    DIRECTION INPUT ;
    USE SIGNAL ;
    SHAPE ABUTMENT ;
    PORT
      LAYER metal3 ;
      RECT 0.000 214.725 0.070 214.795 ;
    END
  END W0_data[229]
  PIN W0_data[230]
    DIRECTION INPUT ;
    USE SIGNAL ;
    SHAPE ABUTMENT ;
    PORT
      LAYER metal3 ;
      RECT 0.000 215.005 0.070 215.075 ;
    END
  END W0_data[230]
  PIN W0_data[231]
    DIRECTION INPUT ;
    USE SIGNAL ;
    SHAPE ABUTMENT ;
    PORT
      LAYER metal3 ;
      RECT 0.000 215.285 0.070 215.355 ;
    END
  END W0_data[231]
  PIN W0_data[232]
    DIRECTION INPUT ;
    USE SIGNAL ;
    SHAPE ABUTMENT ;
    PORT
      LAYER metal3 ;
      RECT 0.000 215.565 0.070 215.635 ;
    END
  END W0_data[232]
  PIN W0_data[233]
    DIRECTION INPUT ;
    USE SIGNAL ;
    SHAPE ABUTMENT ;
    PORT
      LAYER metal3 ;
      RECT 0.000 215.845 0.070 215.915 ;
    END
  END W0_data[233]
  PIN W0_data[234]
    DIRECTION INPUT ;
    USE SIGNAL ;
    SHAPE ABUTMENT ;
    PORT
      LAYER metal3 ;
      RECT 0.000 216.125 0.070 216.195 ;
    END
  END W0_data[234]
  PIN W0_data[235]
    DIRECTION INPUT ;
    USE SIGNAL ;
    SHAPE ABUTMENT ;
    PORT
      LAYER metal3 ;
      RECT 0.000 216.405 0.070 216.475 ;
    END
  END W0_data[235]
  PIN W0_data[236]
    DIRECTION INPUT ;
    USE SIGNAL ;
    SHAPE ABUTMENT ;
    PORT
      LAYER metal3 ;
      RECT 0.000 216.685 0.070 216.755 ;
    END
  END W0_data[236]
  PIN W0_data[237]
    DIRECTION INPUT ;
    USE SIGNAL ;
    SHAPE ABUTMENT ;
    PORT
      LAYER metal3 ;
      RECT 0.000 216.965 0.070 217.035 ;
    END
  END W0_data[237]
  PIN W0_data[238]
    DIRECTION INPUT ;
    USE SIGNAL ;
    SHAPE ABUTMENT ;
    PORT
      LAYER metal3 ;
      RECT 0.000 217.245 0.070 217.315 ;
    END
  END W0_data[238]
  PIN W0_data[239]
    DIRECTION INPUT ;
    USE SIGNAL ;
    SHAPE ABUTMENT ;
    PORT
      LAYER metal3 ;
      RECT 0.000 217.525 0.070 217.595 ;
    END
  END W0_data[239]
  PIN W0_data[240]
    DIRECTION INPUT ;
    USE SIGNAL ;
    SHAPE ABUTMENT ;
    PORT
      LAYER metal3 ;
      RECT 0.000 217.805 0.070 217.875 ;
    END
  END W0_data[240]
  PIN W0_data[241]
    DIRECTION INPUT ;
    USE SIGNAL ;
    SHAPE ABUTMENT ;
    PORT
      LAYER metal3 ;
      RECT 0.000 218.085 0.070 218.155 ;
    END
  END W0_data[241]
  PIN W0_data[242]
    DIRECTION INPUT ;
    USE SIGNAL ;
    SHAPE ABUTMENT ;
    PORT
      LAYER metal3 ;
      RECT 0.000 218.365 0.070 218.435 ;
    END
  END W0_data[242]
  PIN W0_data[243]
    DIRECTION INPUT ;
    USE SIGNAL ;
    SHAPE ABUTMENT ;
    PORT
      LAYER metal3 ;
      RECT 0.000 218.645 0.070 218.715 ;
    END
  END W0_data[243]
  PIN W0_data[244]
    DIRECTION INPUT ;
    USE SIGNAL ;
    SHAPE ABUTMENT ;
    PORT
      LAYER metal3 ;
      RECT 0.000 218.925 0.070 218.995 ;
    END
  END W0_data[244]
  PIN W0_data[245]
    DIRECTION INPUT ;
    USE SIGNAL ;
    SHAPE ABUTMENT ;
    PORT
      LAYER metal3 ;
      RECT 0.000 219.205 0.070 219.275 ;
    END
  END W0_data[245]
  PIN W0_data[246]
    DIRECTION INPUT ;
    USE SIGNAL ;
    SHAPE ABUTMENT ;
    PORT
      LAYER metal3 ;
      RECT 0.000 219.485 0.070 219.555 ;
    END
  END W0_data[246]
  PIN W0_data[247]
    DIRECTION INPUT ;
    USE SIGNAL ;
    SHAPE ABUTMENT ;
    PORT
      LAYER metal3 ;
      RECT 0.000 219.765 0.070 219.835 ;
    END
  END W0_data[247]
  PIN W0_data[248]
    DIRECTION INPUT ;
    USE SIGNAL ;
    SHAPE ABUTMENT ;
    PORT
      LAYER metal3 ;
      RECT 0.000 220.045 0.070 220.115 ;
    END
  END W0_data[248]
  PIN W0_data[249]
    DIRECTION INPUT ;
    USE SIGNAL ;
    SHAPE ABUTMENT ;
    PORT
      LAYER metal3 ;
      RECT 0.000 220.325 0.070 220.395 ;
    END
  END W0_data[249]
  PIN W0_data[250]
    DIRECTION INPUT ;
    USE SIGNAL ;
    SHAPE ABUTMENT ;
    PORT
      LAYER metal3 ;
      RECT 0.000 220.605 0.070 220.675 ;
    END
  END W0_data[250]
  PIN W0_data[251]
    DIRECTION INPUT ;
    USE SIGNAL ;
    SHAPE ABUTMENT ;
    PORT
      LAYER metal3 ;
      RECT 0.000 220.885 0.070 220.955 ;
    END
  END W0_data[251]
  PIN W0_data[252]
    DIRECTION INPUT ;
    USE SIGNAL ;
    SHAPE ABUTMENT ;
    PORT
      LAYER metal3 ;
      RECT 0.000 221.165 0.070 221.235 ;
    END
  END W0_data[252]
  PIN W0_data[253]
    DIRECTION INPUT ;
    USE SIGNAL ;
    SHAPE ABUTMENT ;
    PORT
      LAYER metal3 ;
      RECT 0.000 221.445 0.070 221.515 ;
    END
  END W0_data[253]
  PIN W0_data[254]
    DIRECTION INPUT ;
    USE SIGNAL ;
    SHAPE ABUTMENT ;
    PORT
      LAYER metal3 ;
      RECT 0.000 221.725 0.070 221.795 ;
    END
  END W0_data[254]
  PIN W0_data[255]
    DIRECTION INPUT ;
    USE SIGNAL ;
    SHAPE ABUTMENT ;
    PORT
      LAYER metal3 ;
      RECT 0.000 222.005 0.070 222.075 ;
    END
  END W0_data[255]
  PIN W0_data[256]
    DIRECTION INPUT ;
    USE SIGNAL ;
    SHAPE ABUTMENT ;
    PORT
      LAYER metal3 ;
      RECT 0.000 222.285 0.070 222.355 ;
    END
  END W0_data[256]
  PIN W0_data[257]
    DIRECTION INPUT ;
    USE SIGNAL ;
    SHAPE ABUTMENT ;
    PORT
      LAYER metal3 ;
      RECT 0.000 222.565 0.070 222.635 ;
    END
  END W0_data[257]
  PIN W0_data[258]
    DIRECTION INPUT ;
    USE SIGNAL ;
    SHAPE ABUTMENT ;
    PORT
      LAYER metal3 ;
      RECT 0.000 222.845 0.070 222.915 ;
    END
  END W0_data[258]
  PIN W0_data[259]
    DIRECTION INPUT ;
    USE SIGNAL ;
    SHAPE ABUTMENT ;
    PORT
      LAYER metal3 ;
      RECT 0.000 223.125 0.070 223.195 ;
    END
  END W0_data[259]
  PIN W0_data[260]
    DIRECTION INPUT ;
    USE SIGNAL ;
    SHAPE ABUTMENT ;
    PORT
      LAYER metal3 ;
      RECT 0.000 223.405 0.070 223.475 ;
    END
  END W0_data[260]
  PIN W0_data[261]
    DIRECTION INPUT ;
    USE SIGNAL ;
    SHAPE ABUTMENT ;
    PORT
      LAYER metal3 ;
      RECT 0.000 223.685 0.070 223.755 ;
    END
  END W0_data[261]
  PIN W0_data[262]
    DIRECTION INPUT ;
    USE SIGNAL ;
    SHAPE ABUTMENT ;
    PORT
      LAYER metal3 ;
      RECT 0.000 223.965 0.070 224.035 ;
    END
  END W0_data[262]
  PIN W0_data[263]
    DIRECTION INPUT ;
    USE SIGNAL ;
    SHAPE ABUTMENT ;
    PORT
      LAYER metal3 ;
      RECT 0.000 224.245 0.070 224.315 ;
    END
  END W0_data[263]
  PIN W0_data[264]
    DIRECTION INPUT ;
    USE SIGNAL ;
    SHAPE ABUTMENT ;
    PORT
      LAYER metal3 ;
      RECT 0.000 224.525 0.070 224.595 ;
    END
  END W0_data[264]
  PIN W0_data[265]
    DIRECTION INPUT ;
    USE SIGNAL ;
    SHAPE ABUTMENT ;
    PORT
      LAYER metal3 ;
      RECT 0.000 224.805 0.070 224.875 ;
    END
  END W0_data[265]
  PIN W0_data[266]
    DIRECTION INPUT ;
    USE SIGNAL ;
    SHAPE ABUTMENT ;
    PORT
      LAYER metal3 ;
      RECT 0.000 225.085 0.070 225.155 ;
    END
  END W0_data[266]
  PIN W0_data[267]
    DIRECTION INPUT ;
    USE SIGNAL ;
    SHAPE ABUTMENT ;
    PORT
      LAYER metal3 ;
      RECT 0.000 225.365 0.070 225.435 ;
    END
  END W0_data[267]
  PIN W0_data[268]
    DIRECTION INPUT ;
    USE SIGNAL ;
    SHAPE ABUTMENT ;
    PORT
      LAYER metal3 ;
      RECT 0.000 225.645 0.070 225.715 ;
    END
  END W0_data[268]
  PIN W0_data[269]
    DIRECTION INPUT ;
    USE SIGNAL ;
    SHAPE ABUTMENT ;
    PORT
      LAYER metal3 ;
      RECT 0.000 225.925 0.070 225.995 ;
    END
  END W0_data[269]
  PIN W0_data[270]
    DIRECTION INPUT ;
    USE SIGNAL ;
    SHAPE ABUTMENT ;
    PORT
      LAYER metal3 ;
      RECT 0.000 226.205 0.070 226.275 ;
    END
  END W0_data[270]
  PIN W0_data[271]
    DIRECTION INPUT ;
    USE SIGNAL ;
    SHAPE ABUTMENT ;
    PORT
      LAYER metal3 ;
      RECT 0.000 226.485 0.070 226.555 ;
    END
  END W0_data[271]
  PIN W0_data[272]
    DIRECTION INPUT ;
    USE SIGNAL ;
    SHAPE ABUTMENT ;
    PORT
      LAYER metal3 ;
      RECT 0.000 226.765 0.070 226.835 ;
    END
  END W0_data[272]
  PIN W0_data[273]
    DIRECTION INPUT ;
    USE SIGNAL ;
    SHAPE ABUTMENT ;
    PORT
      LAYER metal3 ;
      RECT 0.000 227.045 0.070 227.115 ;
    END
  END W0_data[273]
  PIN W0_data[274]
    DIRECTION INPUT ;
    USE SIGNAL ;
    SHAPE ABUTMENT ;
    PORT
      LAYER metal3 ;
      RECT 0.000 227.325 0.070 227.395 ;
    END
  END W0_data[274]
  PIN W0_data[275]
    DIRECTION INPUT ;
    USE SIGNAL ;
    SHAPE ABUTMENT ;
    PORT
      LAYER metal3 ;
      RECT 0.000 227.605 0.070 227.675 ;
    END
  END W0_data[275]
  PIN W0_data[276]
    DIRECTION INPUT ;
    USE SIGNAL ;
    SHAPE ABUTMENT ;
    PORT
      LAYER metal3 ;
      RECT 0.000 227.885 0.070 227.955 ;
    END
  END W0_data[276]
  PIN W0_data[277]
    DIRECTION INPUT ;
    USE SIGNAL ;
    SHAPE ABUTMENT ;
    PORT
      LAYER metal3 ;
      RECT 0.000 228.165 0.070 228.235 ;
    END
  END W0_data[277]
  PIN W0_data[278]
    DIRECTION INPUT ;
    USE SIGNAL ;
    SHAPE ABUTMENT ;
    PORT
      LAYER metal3 ;
      RECT 0.000 228.445 0.070 228.515 ;
    END
  END W0_data[278]
  PIN W0_data[279]
    DIRECTION INPUT ;
    USE SIGNAL ;
    SHAPE ABUTMENT ;
    PORT
      LAYER metal3 ;
      RECT 0.000 228.725 0.070 228.795 ;
    END
  END W0_data[279]
  PIN W0_data[280]
    DIRECTION INPUT ;
    USE SIGNAL ;
    SHAPE ABUTMENT ;
    PORT
      LAYER metal3 ;
      RECT 0.000 229.005 0.070 229.075 ;
    END
  END W0_data[280]
  PIN W0_data[281]
    DIRECTION INPUT ;
    USE SIGNAL ;
    SHAPE ABUTMENT ;
    PORT
      LAYER metal3 ;
      RECT 0.000 229.285 0.070 229.355 ;
    END
  END W0_data[281]
  PIN W0_data[282]
    DIRECTION INPUT ;
    USE SIGNAL ;
    SHAPE ABUTMENT ;
    PORT
      LAYER metal3 ;
      RECT 0.000 229.565 0.070 229.635 ;
    END
  END W0_data[282]
  PIN W0_data[283]
    DIRECTION INPUT ;
    USE SIGNAL ;
    SHAPE ABUTMENT ;
    PORT
      LAYER metal3 ;
      RECT 0.000 229.845 0.070 229.915 ;
    END
  END W0_data[283]
  PIN W0_data[284]
    DIRECTION INPUT ;
    USE SIGNAL ;
    SHAPE ABUTMENT ;
    PORT
      LAYER metal3 ;
      RECT 0.000 230.125 0.070 230.195 ;
    END
  END W0_data[284]
  PIN W0_data[285]
    DIRECTION INPUT ;
    USE SIGNAL ;
    SHAPE ABUTMENT ;
    PORT
      LAYER metal3 ;
      RECT 0.000 230.405 0.070 230.475 ;
    END
  END W0_data[285]
  PIN W0_data[286]
    DIRECTION INPUT ;
    USE SIGNAL ;
    SHAPE ABUTMENT ;
    PORT
      LAYER metal3 ;
      RECT 0.000 230.685 0.070 230.755 ;
    END
  END W0_data[286]
  PIN W0_data[287]
    DIRECTION INPUT ;
    USE SIGNAL ;
    SHAPE ABUTMENT ;
    PORT
      LAYER metal3 ;
      RECT 0.000 230.965 0.070 231.035 ;
    END
  END W0_data[287]
  PIN W0_data[288]
    DIRECTION INPUT ;
    USE SIGNAL ;
    SHAPE ABUTMENT ;
    PORT
      LAYER metal3 ;
      RECT 0.000 231.245 0.070 231.315 ;
    END
  END W0_data[288]
  PIN W0_data[289]
    DIRECTION INPUT ;
    USE SIGNAL ;
    SHAPE ABUTMENT ;
    PORT
      LAYER metal3 ;
      RECT 0.000 231.525 0.070 231.595 ;
    END
  END W0_data[289]
  PIN W0_data[290]
    DIRECTION INPUT ;
    USE SIGNAL ;
    SHAPE ABUTMENT ;
    PORT
      LAYER metal3 ;
      RECT 0.000 231.805 0.070 231.875 ;
    END
  END W0_data[290]
  PIN W0_data[291]
    DIRECTION INPUT ;
    USE SIGNAL ;
    SHAPE ABUTMENT ;
    PORT
      LAYER metal3 ;
      RECT 0.000 232.085 0.070 232.155 ;
    END
  END W0_data[291]
  PIN W0_data[292]
    DIRECTION INPUT ;
    USE SIGNAL ;
    SHAPE ABUTMENT ;
    PORT
      LAYER metal3 ;
      RECT 0.000 232.365 0.070 232.435 ;
    END
  END W0_data[292]
  PIN W0_data[293]
    DIRECTION INPUT ;
    USE SIGNAL ;
    SHAPE ABUTMENT ;
    PORT
      LAYER metal3 ;
      RECT 0.000 232.645 0.070 232.715 ;
    END
  END W0_data[293]
  PIN W0_data[294]
    DIRECTION INPUT ;
    USE SIGNAL ;
    SHAPE ABUTMENT ;
    PORT
      LAYER metal3 ;
      RECT 0.000 232.925 0.070 232.995 ;
    END
  END W0_data[294]
  PIN W0_data[295]
    DIRECTION INPUT ;
    USE SIGNAL ;
    SHAPE ABUTMENT ;
    PORT
      LAYER metal3 ;
      RECT 0.000 233.205 0.070 233.275 ;
    END
  END W0_data[295]
  PIN W0_data[296]
    DIRECTION INPUT ;
    USE SIGNAL ;
    SHAPE ABUTMENT ;
    PORT
      LAYER metal3 ;
      RECT 0.000 233.485 0.070 233.555 ;
    END
  END W0_data[296]
  PIN W0_data[297]
    DIRECTION INPUT ;
    USE SIGNAL ;
    SHAPE ABUTMENT ;
    PORT
      LAYER metal3 ;
      RECT 0.000 233.765 0.070 233.835 ;
    END
  END W0_data[297]
  PIN W0_data[298]
    DIRECTION INPUT ;
    USE SIGNAL ;
    SHAPE ABUTMENT ;
    PORT
      LAYER metal3 ;
      RECT 0.000 234.045 0.070 234.115 ;
    END
  END W0_data[298]
  PIN W0_data[299]
    DIRECTION INPUT ;
    USE SIGNAL ;
    SHAPE ABUTMENT ;
    PORT
      LAYER metal3 ;
      RECT 0.000 234.325 0.070 234.395 ;
    END
  END W0_data[299]
  PIN W0_data[300]
    DIRECTION INPUT ;
    USE SIGNAL ;
    SHAPE ABUTMENT ;
    PORT
      LAYER metal3 ;
      RECT 0.000 234.605 0.070 234.675 ;
    END
  END W0_data[300]
  PIN W0_data[301]
    DIRECTION INPUT ;
    USE SIGNAL ;
    SHAPE ABUTMENT ;
    PORT
      LAYER metal3 ;
      RECT 0.000 234.885 0.070 234.955 ;
    END
  END W0_data[301]
  PIN W0_data[302]
    DIRECTION INPUT ;
    USE SIGNAL ;
    SHAPE ABUTMENT ;
    PORT
      LAYER metal3 ;
      RECT 0.000 235.165 0.070 235.235 ;
    END
  END W0_data[302]
  PIN W0_data[303]
    DIRECTION INPUT ;
    USE SIGNAL ;
    SHAPE ABUTMENT ;
    PORT
      LAYER metal3 ;
      RECT 0.000 235.445 0.070 235.515 ;
    END
  END W0_data[303]
  PIN W0_data[304]
    DIRECTION INPUT ;
    USE SIGNAL ;
    SHAPE ABUTMENT ;
    PORT
      LAYER metal3 ;
      RECT 0.000 235.725 0.070 235.795 ;
    END
  END W0_data[304]
  PIN W0_data[305]
    DIRECTION INPUT ;
    USE SIGNAL ;
    SHAPE ABUTMENT ;
    PORT
      LAYER metal3 ;
      RECT 0.000 236.005 0.070 236.075 ;
    END
  END W0_data[305]
  PIN W0_data[306]
    DIRECTION INPUT ;
    USE SIGNAL ;
    SHAPE ABUTMENT ;
    PORT
      LAYER metal3 ;
      RECT 0.000 236.285 0.070 236.355 ;
    END
  END W0_data[306]
  PIN W0_data[307]
    DIRECTION INPUT ;
    USE SIGNAL ;
    SHAPE ABUTMENT ;
    PORT
      LAYER metal3 ;
      RECT 0.000 236.565 0.070 236.635 ;
    END
  END W0_data[307]
  PIN W0_data[308]
    DIRECTION INPUT ;
    USE SIGNAL ;
    SHAPE ABUTMENT ;
    PORT
      LAYER metal3 ;
      RECT 0.000 236.845 0.070 236.915 ;
    END
  END W0_data[308]
  PIN W0_data[309]
    DIRECTION INPUT ;
    USE SIGNAL ;
    SHAPE ABUTMENT ;
    PORT
      LAYER metal3 ;
      RECT 0.000 237.125 0.070 237.195 ;
    END
  END W0_data[309]
  PIN W0_data[310]
    DIRECTION INPUT ;
    USE SIGNAL ;
    SHAPE ABUTMENT ;
    PORT
      LAYER metal3 ;
      RECT 0.000 237.405 0.070 237.475 ;
    END
  END W0_data[310]
  PIN W0_data[311]
    DIRECTION INPUT ;
    USE SIGNAL ;
    SHAPE ABUTMENT ;
    PORT
      LAYER metal3 ;
      RECT 0.000 237.685 0.070 237.755 ;
    END
  END W0_data[311]
  PIN W0_data[312]
    DIRECTION INPUT ;
    USE SIGNAL ;
    SHAPE ABUTMENT ;
    PORT
      LAYER metal3 ;
      RECT 0.000 237.965 0.070 238.035 ;
    END
  END W0_data[312]
  PIN W0_data[313]
    DIRECTION INPUT ;
    USE SIGNAL ;
    SHAPE ABUTMENT ;
    PORT
      LAYER metal3 ;
      RECT 0.000 238.245 0.070 238.315 ;
    END
  END W0_data[313]
  PIN W0_data[314]
    DIRECTION INPUT ;
    USE SIGNAL ;
    SHAPE ABUTMENT ;
    PORT
      LAYER metal3 ;
      RECT 0.000 238.525 0.070 238.595 ;
    END
  END W0_data[314]
  PIN W0_data[315]
    DIRECTION INPUT ;
    USE SIGNAL ;
    SHAPE ABUTMENT ;
    PORT
      LAYER metal3 ;
      RECT 0.000 238.805 0.070 238.875 ;
    END
  END W0_data[315]
  PIN W0_data[316]
    DIRECTION INPUT ;
    USE SIGNAL ;
    SHAPE ABUTMENT ;
    PORT
      LAYER metal3 ;
      RECT 0.000 239.085 0.070 239.155 ;
    END
  END W0_data[316]
  PIN W0_data[317]
    DIRECTION INPUT ;
    USE SIGNAL ;
    SHAPE ABUTMENT ;
    PORT
      LAYER metal3 ;
      RECT 0.000 239.365 0.070 239.435 ;
    END
  END W0_data[317]
  PIN W0_data[318]
    DIRECTION INPUT ;
    USE SIGNAL ;
    SHAPE ABUTMENT ;
    PORT
      LAYER metal3 ;
      RECT 0.000 239.645 0.070 239.715 ;
    END
  END W0_data[318]
  PIN W0_data[319]
    DIRECTION INPUT ;
    USE SIGNAL ;
    SHAPE ABUTMENT ;
    PORT
      LAYER metal3 ;
      RECT 0.000 239.925 0.070 239.995 ;
    END
  END W0_data[319]
  PIN W0_data[320]
    DIRECTION INPUT ;
    USE SIGNAL ;
    SHAPE ABUTMENT ;
    PORT
      LAYER metal3 ;
      RECT 0.000 240.205 0.070 240.275 ;
    END
  END W0_data[320]
  PIN W0_data[321]
    DIRECTION INPUT ;
    USE SIGNAL ;
    SHAPE ABUTMENT ;
    PORT
      LAYER metal3 ;
      RECT 0.000 240.485 0.070 240.555 ;
    END
  END W0_data[321]
  PIN W0_data[322]
    DIRECTION INPUT ;
    USE SIGNAL ;
    SHAPE ABUTMENT ;
    PORT
      LAYER metal3 ;
      RECT 0.000 240.765 0.070 240.835 ;
    END
  END W0_data[322]
  PIN W0_data[323]
    DIRECTION INPUT ;
    USE SIGNAL ;
    SHAPE ABUTMENT ;
    PORT
      LAYER metal3 ;
      RECT 0.000 241.045 0.070 241.115 ;
    END
  END W0_data[323]
  PIN W0_data[324]
    DIRECTION INPUT ;
    USE SIGNAL ;
    SHAPE ABUTMENT ;
    PORT
      LAYER metal3 ;
      RECT 0.000 241.325 0.070 241.395 ;
    END
  END W0_data[324]
  PIN W0_data[325]
    DIRECTION INPUT ;
    USE SIGNAL ;
    SHAPE ABUTMENT ;
    PORT
      LAYER metal3 ;
      RECT 0.000 241.605 0.070 241.675 ;
    END
  END W0_data[325]
  PIN W0_data[326]
    DIRECTION INPUT ;
    USE SIGNAL ;
    SHAPE ABUTMENT ;
    PORT
      LAYER metal3 ;
      RECT 0.000 241.885 0.070 241.955 ;
    END
  END W0_data[326]
  PIN W0_data[327]
    DIRECTION INPUT ;
    USE SIGNAL ;
    SHAPE ABUTMENT ;
    PORT
      LAYER metal3 ;
      RECT 0.000 242.165 0.070 242.235 ;
    END
  END W0_data[327]
  PIN W0_data[328]
    DIRECTION INPUT ;
    USE SIGNAL ;
    SHAPE ABUTMENT ;
    PORT
      LAYER metal3 ;
      RECT 0.000 242.445 0.070 242.515 ;
    END
  END W0_data[328]
  PIN W0_data[329]
    DIRECTION INPUT ;
    USE SIGNAL ;
    SHAPE ABUTMENT ;
    PORT
      LAYER metal3 ;
      RECT 0.000 242.725 0.070 242.795 ;
    END
  END W0_data[329]
  PIN W0_data[330]
    DIRECTION INPUT ;
    USE SIGNAL ;
    SHAPE ABUTMENT ;
    PORT
      LAYER metal3 ;
      RECT 0.000 243.005 0.070 243.075 ;
    END
  END W0_data[330]
  PIN W0_data[331]
    DIRECTION INPUT ;
    USE SIGNAL ;
    SHAPE ABUTMENT ;
    PORT
      LAYER metal3 ;
      RECT 0.000 243.285 0.070 243.355 ;
    END
  END W0_data[331]
  PIN W0_data[332]
    DIRECTION INPUT ;
    USE SIGNAL ;
    SHAPE ABUTMENT ;
    PORT
      LAYER metal3 ;
      RECT 0.000 243.565 0.070 243.635 ;
    END
  END W0_data[332]
  PIN W0_data[333]
    DIRECTION INPUT ;
    USE SIGNAL ;
    SHAPE ABUTMENT ;
    PORT
      LAYER metal3 ;
      RECT 0.000 243.845 0.070 243.915 ;
    END
  END W0_data[333]
  PIN W0_data[334]
    DIRECTION INPUT ;
    USE SIGNAL ;
    SHAPE ABUTMENT ;
    PORT
      LAYER metal3 ;
      RECT 0.000 244.125 0.070 244.195 ;
    END
  END W0_data[334]
  PIN W0_data[335]
    DIRECTION INPUT ;
    USE SIGNAL ;
    SHAPE ABUTMENT ;
    PORT
      LAYER metal3 ;
      RECT 0.000 244.405 0.070 244.475 ;
    END
  END W0_data[335]
  PIN W0_data[336]
    DIRECTION INPUT ;
    USE SIGNAL ;
    SHAPE ABUTMENT ;
    PORT
      LAYER metal3 ;
      RECT 0.000 244.685 0.070 244.755 ;
    END
  END W0_data[336]
  PIN W0_data[337]
    DIRECTION INPUT ;
    USE SIGNAL ;
    SHAPE ABUTMENT ;
    PORT
      LAYER metal3 ;
      RECT 0.000 244.965 0.070 245.035 ;
    END
  END W0_data[337]
  PIN W0_data[338]
    DIRECTION INPUT ;
    USE SIGNAL ;
    SHAPE ABUTMENT ;
    PORT
      LAYER metal3 ;
      RECT 0.000 245.245 0.070 245.315 ;
    END
  END W0_data[338]
  PIN W0_data[339]
    DIRECTION INPUT ;
    USE SIGNAL ;
    SHAPE ABUTMENT ;
    PORT
      LAYER metal3 ;
      RECT 0.000 245.525 0.070 245.595 ;
    END
  END W0_data[339]
  PIN W0_data[340]
    DIRECTION INPUT ;
    USE SIGNAL ;
    SHAPE ABUTMENT ;
    PORT
      LAYER metal3 ;
      RECT 0.000 245.805 0.070 245.875 ;
    END
  END W0_data[340]
  PIN W0_data[341]
    DIRECTION INPUT ;
    USE SIGNAL ;
    SHAPE ABUTMENT ;
    PORT
      LAYER metal3 ;
      RECT 0.000 246.085 0.070 246.155 ;
    END
  END W0_data[341]
  PIN W0_data[342]
    DIRECTION INPUT ;
    USE SIGNAL ;
    SHAPE ABUTMENT ;
    PORT
      LAYER metal3 ;
      RECT 0.000 246.365 0.070 246.435 ;
    END
  END W0_data[342]
  PIN W0_data[343]
    DIRECTION INPUT ;
    USE SIGNAL ;
    SHAPE ABUTMENT ;
    PORT
      LAYER metal3 ;
      RECT 0.000 246.645 0.070 246.715 ;
    END
  END W0_data[343]
  PIN W0_data[344]
    DIRECTION INPUT ;
    USE SIGNAL ;
    SHAPE ABUTMENT ;
    PORT
      LAYER metal3 ;
      RECT 0.000 246.925 0.070 246.995 ;
    END
  END W0_data[344]
  PIN W0_data[345]
    DIRECTION INPUT ;
    USE SIGNAL ;
    SHAPE ABUTMENT ;
    PORT
      LAYER metal3 ;
      RECT 0.000 247.205 0.070 247.275 ;
    END
  END W0_data[345]
  PIN W0_data[346]
    DIRECTION INPUT ;
    USE SIGNAL ;
    SHAPE ABUTMENT ;
    PORT
      LAYER metal3 ;
      RECT 0.000 247.485 0.070 247.555 ;
    END
  END W0_data[346]
  PIN W0_data[347]
    DIRECTION INPUT ;
    USE SIGNAL ;
    SHAPE ABUTMENT ;
    PORT
      LAYER metal3 ;
      RECT 0.000 247.765 0.070 247.835 ;
    END
  END W0_data[347]
  PIN W0_data[348]
    DIRECTION INPUT ;
    USE SIGNAL ;
    SHAPE ABUTMENT ;
    PORT
      LAYER metal3 ;
      RECT 0.000 248.045 0.070 248.115 ;
    END
  END W0_data[348]
  PIN W0_data[349]
    DIRECTION INPUT ;
    USE SIGNAL ;
    SHAPE ABUTMENT ;
    PORT
      LAYER metal3 ;
      RECT 0.000 248.325 0.070 248.395 ;
    END
  END W0_data[349]
  PIN W0_data[350]
    DIRECTION INPUT ;
    USE SIGNAL ;
    SHAPE ABUTMENT ;
    PORT
      LAYER metal3 ;
      RECT 0.000 248.605 0.070 248.675 ;
    END
  END W0_data[350]
  PIN W0_data[351]
    DIRECTION INPUT ;
    USE SIGNAL ;
    SHAPE ABUTMENT ;
    PORT
      LAYER metal3 ;
      RECT 0.000 248.885 0.070 248.955 ;
    END
  END W0_data[351]
  PIN W0_data[352]
    DIRECTION INPUT ;
    USE SIGNAL ;
    SHAPE ABUTMENT ;
    PORT
      LAYER metal3 ;
      RECT 0.000 249.165 0.070 249.235 ;
    END
  END W0_data[352]
  PIN W0_data[353]
    DIRECTION INPUT ;
    USE SIGNAL ;
    SHAPE ABUTMENT ;
    PORT
      LAYER metal3 ;
      RECT 0.000 249.445 0.070 249.515 ;
    END
  END W0_data[353]
  PIN W0_data[354]
    DIRECTION INPUT ;
    USE SIGNAL ;
    SHAPE ABUTMENT ;
    PORT
      LAYER metal3 ;
      RECT 0.000 249.725 0.070 249.795 ;
    END
  END W0_data[354]
  PIN W0_data[355]
    DIRECTION INPUT ;
    USE SIGNAL ;
    SHAPE ABUTMENT ;
    PORT
      LAYER metal3 ;
      RECT 0.000 250.005 0.070 250.075 ;
    END
  END W0_data[355]
  PIN W0_data[356]
    DIRECTION INPUT ;
    USE SIGNAL ;
    SHAPE ABUTMENT ;
    PORT
      LAYER metal3 ;
      RECT 0.000 250.285 0.070 250.355 ;
    END
  END W0_data[356]
  PIN W0_data[357]
    DIRECTION INPUT ;
    USE SIGNAL ;
    SHAPE ABUTMENT ;
    PORT
      LAYER metal3 ;
      RECT 0.000 250.565 0.070 250.635 ;
    END
  END W0_data[357]
  PIN W0_data[358]
    DIRECTION INPUT ;
    USE SIGNAL ;
    SHAPE ABUTMENT ;
    PORT
      LAYER metal3 ;
      RECT 0.000 250.845 0.070 250.915 ;
    END
  END W0_data[358]
  PIN W0_data[359]
    DIRECTION INPUT ;
    USE SIGNAL ;
    SHAPE ABUTMENT ;
    PORT
      LAYER metal3 ;
      RECT 0.000 251.125 0.070 251.195 ;
    END
  END W0_data[359]
  PIN W0_data[360]
    DIRECTION INPUT ;
    USE SIGNAL ;
    SHAPE ABUTMENT ;
    PORT
      LAYER metal3 ;
      RECT 0.000 251.405 0.070 251.475 ;
    END
  END W0_data[360]
  PIN W0_data[361]
    DIRECTION INPUT ;
    USE SIGNAL ;
    SHAPE ABUTMENT ;
    PORT
      LAYER metal3 ;
      RECT 0.000 251.685 0.070 251.755 ;
    END
  END W0_data[361]
  PIN W0_data[362]
    DIRECTION INPUT ;
    USE SIGNAL ;
    SHAPE ABUTMENT ;
    PORT
      LAYER metal3 ;
      RECT 0.000 251.965 0.070 252.035 ;
    END
  END W0_data[362]
  PIN W0_data[363]
    DIRECTION INPUT ;
    USE SIGNAL ;
    SHAPE ABUTMENT ;
    PORT
      LAYER metal3 ;
      RECT 0.000 252.245 0.070 252.315 ;
    END
  END W0_data[363]
  PIN W0_data[364]
    DIRECTION INPUT ;
    USE SIGNAL ;
    SHAPE ABUTMENT ;
    PORT
      LAYER metal3 ;
      RECT 0.000 252.525 0.070 252.595 ;
    END
  END W0_data[364]
  PIN W0_data[365]
    DIRECTION INPUT ;
    USE SIGNAL ;
    SHAPE ABUTMENT ;
    PORT
      LAYER metal3 ;
      RECT 0.000 252.805 0.070 252.875 ;
    END
  END W0_data[365]
  PIN W0_data[366]
    DIRECTION INPUT ;
    USE SIGNAL ;
    SHAPE ABUTMENT ;
    PORT
      LAYER metal3 ;
      RECT 0.000 253.085 0.070 253.155 ;
    END
  END W0_data[366]
  PIN W0_data[367]
    DIRECTION INPUT ;
    USE SIGNAL ;
    SHAPE ABUTMENT ;
    PORT
      LAYER metal3 ;
      RECT 0.000 253.365 0.070 253.435 ;
    END
  END W0_data[367]
  PIN W0_data[368]
    DIRECTION INPUT ;
    USE SIGNAL ;
    SHAPE ABUTMENT ;
    PORT
      LAYER metal3 ;
      RECT 0.000 253.645 0.070 253.715 ;
    END
  END W0_data[368]
  PIN W0_data[369]
    DIRECTION INPUT ;
    USE SIGNAL ;
    SHAPE ABUTMENT ;
    PORT
      LAYER metal3 ;
      RECT 0.000 253.925 0.070 253.995 ;
    END
  END W0_data[369]
  PIN W0_data[370]
    DIRECTION INPUT ;
    USE SIGNAL ;
    SHAPE ABUTMENT ;
    PORT
      LAYER metal3 ;
      RECT 0.000 254.205 0.070 254.275 ;
    END
  END W0_data[370]
  PIN W0_data[371]
    DIRECTION INPUT ;
    USE SIGNAL ;
    SHAPE ABUTMENT ;
    PORT
      LAYER metal3 ;
      RECT 0.000 254.485 0.070 254.555 ;
    END
  END W0_data[371]
  PIN W0_data[372]
    DIRECTION INPUT ;
    USE SIGNAL ;
    SHAPE ABUTMENT ;
    PORT
      LAYER metal3 ;
      RECT 0.000 254.765 0.070 254.835 ;
    END
  END W0_data[372]
  PIN W0_data[373]
    DIRECTION INPUT ;
    USE SIGNAL ;
    SHAPE ABUTMENT ;
    PORT
      LAYER metal3 ;
      RECT 0.000 255.045 0.070 255.115 ;
    END
  END W0_data[373]
  PIN W0_data[374]
    DIRECTION INPUT ;
    USE SIGNAL ;
    SHAPE ABUTMENT ;
    PORT
      LAYER metal3 ;
      RECT 0.000 255.325 0.070 255.395 ;
    END
  END W0_data[374]
  PIN W0_data[375]
    DIRECTION INPUT ;
    USE SIGNAL ;
    SHAPE ABUTMENT ;
    PORT
      LAYER metal3 ;
      RECT 0.000 255.605 0.070 255.675 ;
    END
  END W0_data[375]
  PIN W0_data[376]
    DIRECTION INPUT ;
    USE SIGNAL ;
    SHAPE ABUTMENT ;
    PORT
      LAYER metal3 ;
      RECT 0.000 255.885 0.070 255.955 ;
    END
  END W0_data[376]
  PIN W0_data[377]
    DIRECTION INPUT ;
    USE SIGNAL ;
    SHAPE ABUTMENT ;
    PORT
      LAYER metal3 ;
      RECT 0.000 256.165 0.070 256.235 ;
    END
  END W0_data[377]
  PIN W0_data[378]
    DIRECTION INPUT ;
    USE SIGNAL ;
    SHAPE ABUTMENT ;
    PORT
      LAYER metal3 ;
      RECT 0.000 256.445 0.070 256.515 ;
    END
  END W0_data[378]
  PIN W0_data[379]
    DIRECTION INPUT ;
    USE SIGNAL ;
    SHAPE ABUTMENT ;
    PORT
      LAYER metal3 ;
      RECT 0.000 256.725 0.070 256.795 ;
    END
  END W0_data[379]
  PIN W0_data[380]
    DIRECTION INPUT ;
    USE SIGNAL ;
    SHAPE ABUTMENT ;
    PORT
      LAYER metal3 ;
      RECT 0.000 257.005 0.070 257.075 ;
    END
  END W0_data[380]
  PIN W0_data[381]
    DIRECTION INPUT ;
    USE SIGNAL ;
    SHAPE ABUTMENT ;
    PORT
      LAYER metal3 ;
      RECT 0.000 257.285 0.070 257.355 ;
    END
  END W0_data[381]
  PIN W0_data[382]
    DIRECTION INPUT ;
    USE SIGNAL ;
    SHAPE ABUTMENT ;
    PORT
      LAYER metal3 ;
      RECT 0.000 257.565 0.070 257.635 ;
    END
  END W0_data[382]
  PIN W0_data[383]
    DIRECTION INPUT ;
    USE SIGNAL ;
    SHAPE ABUTMENT ;
    PORT
      LAYER metal3 ;
      RECT 0.000 257.845 0.070 257.915 ;
    END
  END W0_data[383]
  PIN W0_data[384]
    DIRECTION INPUT ;
    USE SIGNAL ;
    SHAPE ABUTMENT ;
    PORT
      LAYER metal3 ;
      RECT 0.000 258.125 0.070 258.195 ;
    END
  END W0_data[384]
  PIN W0_data[385]
    DIRECTION INPUT ;
    USE SIGNAL ;
    SHAPE ABUTMENT ;
    PORT
      LAYER metal3 ;
      RECT 0.000 258.405 0.070 258.475 ;
    END
  END W0_data[385]
  PIN W0_data[386]
    DIRECTION INPUT ;
    USE SIGNAL ;
    SHAPE ABUTMENT ;
    PORT
      LAYER metal3 ;
      RECT 0.000 258.685 0.070 258.755 ;
    END
  END W0_data[386]
  PIN W0_data[387]
    DIRECTION INPUT ;
    USE SIGNAL ;
    SHAPE ABUTMENT ;
    PORT
      LAYER metal3 ;
      RECT 0.000 258.965 0.070 259.035 ;
    END
  END W0_data[387]
  PIN W0_data[388]
    DIRECTION INPUT ;
    USE SIGNAL ;
    SHAPE ABUTMENT ;
    PORT
      LAYER metal3 ;
      RECT 0.000 259.245 0.070 259.315 ;
    END
  END W0_data[388]
  PIN W0_data[389]
    DIRECTION INPUT ;
    USE SIGNAL ;
    SHAPE ABUTMENT ;
    PORT
      LAYER metal3 ;
      RECT 0.000 259.525 0.070 259.595 ;
    END
  END W0_data[389]
  PIN W0_data[390]
    DIRECTION INPUT ;
    USE SIGNAL ;
    SHAPE ABUTMENT ;
    PORT
      LAYER metal3 ;
      RECT 0.000 259.805 0.070 259.875 ;
    END
  END W0_data[390]
  PIN W0_data[391]
    DIRECTION INPUT ;
    USE SIGNAL ;
    SHAPE ABUTMENT ;
    PORT
      LAYER metal3 ;
      RECT 0.000 260.085 0.070 260.155 ;
    END
  END W0_data[391]
  PIN W0_data[392]
    DIRECTION INPUT ;
    USE SIGNAL ;
    SHAPE ABUTMENT ;
    PORT
      LAYER metal3 ;
      RECT 0.000 260.365 0.070 260.435 ;
    END
  END W0_data[392]
  PIN W0_data[393]
    DIRECTION INPUT ;
    USE SIGNAL ;
    SHAPE ABUTMENT ;
    PORT
      LAYER metal3 ;
      RECT 0.000 260.645 0.070 260.715 ;
    END
  END W0_data[393]
  PIN W0_data[394]
    DIRECTION INPUT ;
    USE SIGNAL ;
    SHAPE ABUTMENT ;
    PORT
      LAYER metal3 ;
      RECT 0.000 260.925 0.070 260.995 ;
    END
  END W0_data[394]
  PIN W0_data[395]
    DIRECTION INPUT ;
    USE SIGNAL ;
    SHAPE ABUTMENT ;
    PORT
      LAYER metal3 ;
      RECT 0.000 261.205 0.070 261.275 ;
    END
  END W0_data[395]
  PIN W0_data[396]
    DIRECTION INPUT ;
    USE SIGNAL ;
    SHAPE ABUTMENT ;
    PORT
      LAYER metal3 ;
      RECT 0.000 261.485 0.070 261.555 ;
    END
  END W0_data[396]
  PIN W0_data[397]
    DIRECTION INPUT ;
    USE SIGNAL ;
    SHAPE ABUTMENT ;
    PORT
      LAYER metal3 ;
      RECT 0.000 261.765 0.070 261.835 ;
    END
  END W0_data[397]
  PIN W0_data[398]
    DIRECTION INPUT ;
    USE SIGNAL ;
    SHAPE ABUTMENT ;
    PORT
      LAYER metal3 ;
      RECT 0.000 262.045 0.070 262.115 ;
    END
  END W0_data[398]
  PIN W0_data[399]
    DIRECTION INPUT ;
    USE SIGNAL ;
    SHAPE ABUTMENT ;
    PORT
      LAYER metal3 ;
      RECT 0.000 262.325 0.070 262.395 ;
    END
  END W0_data[399]
  PIN W0_data[400]
    DIRECTION INPUT ;
    USE SIGNAL ;
    SHAPE ABUTMENT ;
    PORT
      LAYER metal3 ;
      RECT 0.000 262.605 0.070 262.675 ;
    END
  END W0_data[400]
  PIN W0_data[401]
    DIRECTION INPUT ;
    USE SIGNAL ;
    SHAPE ABUTMENT ;
    PORT
      LAYER metal3 ;
      RECT 0.000 262.885 0.070 262.955 ;
    END
  END W0_data[401]
  PIN W0_data[402]
    DIRECTION INPUT ;
    USE SIGNAL ;
    SHAPE ABUTMENT ;
    PORT
      LAYER metal3 ;
      RECT 0.000 263.165 0.070 263.235 ;
    END
  END W0_data[402]
  PIN W0_data[403]
    DIRECTION INPUT ;
    USE SIGNAL ;
    SHAPE ABUTMENT ;
    PORT
      LAYER metal3 ;
      RECT 0.000 263.445 0.070 263.515 ;
    END
  END W0_data[403]
  PIN W0_data[404]
    DIRECTION INPUT ;
    USE SIGNAL ;
    SHAPE ABUTMENT ;
    PORT
      LAYER metal3 ;
      RECT 0.000 263.725 0.070 263.795 ;
    END
  END W0_data[404]
  PIN W0_data[405]
    DIRECTION INPUT ;
    USE SIGNAL ;
    SHAPE ABUTMENT ;
    PORT
      LAYER metal3 ;
      RECT 0.000 264.005 0.070 264.075 ;
    END
  END W0_data[405]
  PIN W0_data[406]
    DIRECTION INPUT ;
    USE SIGNAL ;
    SHAPE ABUTMENT ;
    PORT
      LAYER metal3 ;
      RECT 0.000 264.285 0.070 264.355 ;
    END
  END W0_data[406]
  PIN W0_data[407]
    DIRECTION INPUT ;
    USE SIGNAL ;
    SHAPE ABUTMENT ;
    PORT
      LAYER metal3 ;
      RECT 0.000 264.565 0.070 264.635 ;
    END
  END W0_data[407]
  PIN W0_data[408]
    DIRECTION INPUT ;
    USE SIGNAL ;
    SHAPE ABUTMENT ;
    PORT
      LAYER metal3 ;
      RECT 0.000 264.845 0.070 264.915 ;
    END
  END W0_data[408]
  PIN W0_data[409]
    DIRECTION INPUT ;
    USE SIGNAL ;
    SHAPE ABUTMENT ;
    PORT
      LAYER metal3 ;
      RECT 0.000 265.125 0.070 265.195 ;
    END
  END W0_data[409]
  PIN W0_data[410]
    DIRECTION INPUT ;
    USE SIGNAL ;
    SHAPE ABUTMENT ;
    PORT
      LAYER metal3 ;
      RECT 0.000 265.405 0.070 265.475 ;
    END
  END W0_data[410]
  PIN W0_data[411]
    DIRECTION INPUT ;
    USE SIGNAL ;
    SHAPE ABUTMENT ;
    PORT
      LAYER metal3 ;
      RECT 0.000 265.685 0.070 265.755 ;
    END
  END W0_data[411]
  PIN W0_data[412]
    DIRECTION INPUT ;
    USE SIGNAL ;
    SHAPE ABUTMENT ;
    PORT
      LAYER metal3 ;
      RECT 0.000 265.965 0.070 266.035 ;
    END
  END W0_data[412]
  PIN W0_data[413]
    DIRECTION INPUT ;
    USE SIGNAL ;
    SHAPE ABUTMENT ;
    PORT
      LAYER metal3 ;
      RECT 0.000 266.245 0.070 266.315 ;
    END
  END W0_data[413]
  PIN W0_data[414]
    DIRECTION INPUT ;
    USE SIGNAL ;
    SHAPE ABUTMENT ;
    PORT
      LAYER metal3 ;
      RECT 0.000 266.525 0.070 266.595 ;
    END
  END W0_data[414]
  PIN W0_data[415]
    DIRECTION INPUT ;
    USE SIGNAL ;
    SHAPE ABUTMENT ;
    PORT
      LAYER metal3 ;
      RECT 0.000 266.805 0.070 266.875 ;
    END
  END W0_data[415]
  PIN W0_data[416]
    DIRECTION INPUT ;
    USE SIGNAL ;
    SHAPE ABUTMENT ;
    PORT
      LAYER metal3 ;
      RECT 0.000 267.085 0.070 267.155 ;
    END
  END W0_data[416]
  PIN W0_data[417]
    DIRECTION INPUT ;
    USE SIGNAL ;
    SHAPE ABUTMENT ;
    PORT
      LAYER metal3 ;
      RECT 0.000 267.365 0.070 267.435 ;
    END
  END W0_data[417]
  PIN W0_data[418]
    DIRECTION INPUT ;
    USE SIGNAL ;
    SHAPE ABUTMENT ;
    PORT
      LAYER metal3 ;
      RECT 0.000 267.645 0.070 267.715 ;
    END
  END W0_data[418]
  PIN W0_data[419]
    DIRECTION INPUT ;
    USE SIGNAL ;
    SHAPE ABUTMENT ;
    PORT
      LAYER metal3 ;
      RECT 0.000 267.925 0.070 267.995 ;
    END
  END W0_data[419]
  PIN W0_data[420]
    DIRECTION INPUT ;
    USE SIGNAL ;
    SHAPE ABUTMENT ;
    PORT
      LAYER metal3 ;
      RECT 0.000 268.205 0.070 268.275 ;
    END
  END W0_data[420]
  PIN W0_data[421]
    DIRECTION INPUT ;
    USE SIGNAL ;
    SHAPE ABUTMENT ;
    PORT
      LAYER metal3 ;
      RECT 0.000 268.485 0.070 268.555 ;
    END
  END W0_data[421]
  PIN W0_data[422]
    DIRECTION INPUT ;
    USE SIGNAL ;
    SHAPE ABUTMENT ;
    PORT
      LAYER metal3 ;
      RECT 0.000 268.765 0.070 268.835 ;
    END
  END W0_data[422]
  PIN W0_data[423]
    DIRECTION INPUT ;
    USE SIGNAL ;
    SHAPE ABUTMENT ;
    PORT
      LAYER metal3 ;
      RECT 0.000 269.045 0.070 269.115 ;
    END
  END W0_data[423]
  PIN W0_data[424]
    DIRECTION INPUT ;
    USE SIGNAL ;
    SHAPE ABUTMENT ;
    PORT
      LAYER metal3 ;
      RECT 0.000 269.325 0.070 269.395 ;
    END
  END W0_data[424]
  PIN W0_data[425]
    DIRECTION INPUT ;
    USE SIGNAL ;
    SHAPE ABUTMENT ;
    PORT
      LAYER metal3 ;
      RECT 0.000 269.605 0.070 269.675 ;
    END
  END W0_data[425]
  PIN W0_data[426]
    DIRECTION INPUT ;
    USE SIGNAL ;
    SHAPE ABUTMENT ;
    PORT
      LAYER metal3 ;
      RECT 0.000 269.885 0.070 269.955 ;
    END
  END W0_data[426]
  PIN W0_data[427]
    DIRECTION INPUT ;
    USE SIGNAL ;
    SHAPE ABUTMENT ;
    PORT
      LAYER metal3 ;
      RECT 0.000 270.165 0.070 270.235 ;
    END
  END W0_data[427]
  PIN W0_data[428]
    DIRECTION INPUT ;
    USE SIGNAL ;
    SHAPE ABUTMENT ;
    PORT
      LAYER metal3 ;
      RECT 0.000 270.445 0.070 270.515 ;
    END
  END W0_data[428]
  PIN W0_data[429]
    DIRECTION INPUT ;
    USE SIGNAL ;
    SHAPE ABUTMENT ;
    PORT
      LAYER metal3 ;
      RECT 0.000 270.725 0.070 270.795 ;
    END
  END W0_data[429]
  PIN W0_data[430]
    DIRECTION INPUT ;
    USE SIGNAL ;
    SHAPE ABUTMENT ;
    PORT
      LAYER metal3 ;
      RECT 0.000 271.005 0.070 271.075 ;
    END
  END W0_data[430]
  PIN W0_data[431]
    DIRECTION INPUT ;
    USE SIGNAL ;
    SHAPE ABUTMENT ;
    PORT
      LAYER metal3 ;
      RECT 0.000 271.285 0.070 271.355 ;
    END
  END W0_data[431]
  PIN W0_data[432]
    DIRECTION INPUT ;
    USE SIGNAL ;
    SHAPE ABUTMENT ;
    PORT
      LAYER metal3 ;
      RECT 0.000 271.565 0.070 271.635 ;
    END
  END W0_data[432]
  PIN W0_data[433]
    DIRECTION INPUT ;
    USE SIGNAL ;
    SHAPE ABUTMENT ;
    PORT
      LAYER metal3 ;
      RECT 0.000 271.845 0.070 271.915 ;
    END
  END W0_data[433]
  PIN W0_data[434]
    DIRECTION INPUT ;
    USE SIGNAL ;
    SHAPE ABUTMENT ;
    PORT
      LAYER metal3 ;
      RECT 0.000 272.125 0.070 272.195 ;
    END
  END W0_data[434]
  PIN W0_data[435]
    DIRECTION INPUT ;
    USE SIGNAL ;
    SHAPE ABUTMENT ;
    PORT
      LAYER metal3 ;
      RECT 0.000 272.405 0.070 272.475 ;
    END
  END W0_data[435]
  PIN W0_data[436]
    DIRECTION INPUT ;
    USE SIGNAL ;
    SHAPE ABUTMENT ;
    PORT
      LAYER metal3 ;
      RECT 0.000 272.685 0.070 272.755 ;
    END
  END W0_data[436]
  PIN W0_data[437]
    DIRECTION INPUT ;
    USE SIGNAL ;
    SHAPE ABUTMENT ;
    PORT
      LAYER metal3 ;
      RECT 0.000 272.965 0.070 273.035 ;
    END
  END W0_data[437]
  PIN W0_data[438]
    DIRECTION INPUT ;
    USE SIGNAL ;
    SHAPE ABUTMENT ;
    PORT
      LAYER metal3 ;
      RECT 0.000 273.245 0.070 273.315 ;
    END
  END W0_data[438]
  PIN W0_data[439]
    DIRECTION INPUT ;
    USE SIGNAL ;
    SHAPE ABUTMENT ;
    PORT
      LAYER metal3 ;
      RECT 0.000 273.525 0.070 273.595 ;
    END
  END W0_data[439]
  PIN W0_data[440]
    DIRECTION INPUT ;
    USE SIGNAL ;
    SHAPE ABUTMENT ;
    PORT
      LAYER metal3 ;
      RECT 0.000 273.805 0.070 273.875 ;
    END
  END W0_data[440]
  PIN W0_data[441]
    DIRECTION INPUT ;
    USE SIGNAL ;
    SHAPE ABUTMENT ;
    PORT
      LAYER metal3 ;
      RECT 0.000 274.085 0.070 274.155 ;
    END
  END W0_data[441]
  PIN W0_data[442]
    DIRECTION INPUT ;
    USE SIGNAL ;
    SHAPE ABUTMENT ;
    PORT
      LAYER metal3 ;
      RECT 0.000 274.365 0.070 274.435 ;
    END
  END W0_data[442]
  PIN W0_data[443]
    DIRECTION INPUT ;
    USE SIGNAL ;
    SHAPE ABUTMENT ;
    PORT
      LAYER metal3 ;
      RECT 0.000 274.645 0.070 274.715 ;
    END
  END W0_data[443]
  PIN W0_data[444]
    DIRECTION INPUT ;
    USE SIGNAL ;
    SHAPE ABUTMENT ;
    PORT
      LAYER metal3 ;
      RECT 0.000 274.925 0.070 274.995 ;
    END
  END W0_data[444]
  PIN W0_data[445]
    DIRECTION INPUT ;
    USE SIGNAL ;
    SHAPE ABUTMENT ;
    PORT
      LAYER metal3 ;
      RECT 0.000 275.205 0.070 275.275 ;
    END
  END W0_data[445]
  PIN W0_data[446]
    DIRECTION INPUT ;
    USE SIGNAL ;
    SHAPE ABUTMENT ;
    PORT
      LAYER metal3 ;
      RECT 0.000 275.485 0.070 275.555 ;
    END
  END W0_data[446]
  PIN W0_data[447]
    DIRECTION INPUT ;
    USE SIGNAL ;
    SHAPE ABUTMENT ;
    PORT
      LAYER metal3 ;
      RECT 0.000 275.765 0.070 275.835 ;
    END
  END W0_data[447]
  PIN W0_data[448]
    DIRECTION INPUT ;
    USE SIGNAL ;
    SHAPE ABUTMENT ;
    PORT
      LAYER metal3 ;
      RECT 0.000 276.045 0.070 276.115 ;
    END
  END W0_data[448]
  PIN W0_data[449]
    DIRECTION INPUT ;
    USE SIGNAL ;
    SHAPE ABUTMENT ;
    PORT
      LAYER metal3 ;
      RECT 0.000 276.325 0.070 276.395 ;
    END
  END W0_data[449]
  PIN W0_data[450]
    DIRECTION INPUT ;
    USE SIGNAL ;
    SHAPE ABUTMENT ;
    PORT
      LAYER metal3 ;
      RECT 0.000 276.605 0.070 276.675 ;
    END
  END W0_data[450]
  PIN W0_data[451]
    DIRECTION INPUT ;
    USE SIGNAL ;
    SHAPE ABUTMENT ;
    PORT
      LAYER metal3 ;
      RECT 0.000 276.885 0.070 276.955 ;
    END
  END W0_data[451]
  PIN W0_data[452]
    DIRECTION INPUT ;
    USE SIGNAL ;
    SHAPE ABUTMENT ;
    PORT
      LAYER metal3 ;
      RECT 0.000 277.165 0.070 277.235 ;
    END
  END W0_data[452]
  PIN W0_data[453]
    DIRECTION INPUT ;
    USE SIGNAL ;
    SHAPE ABUTMENT ;
    PORT
      LAYER metal3 ;
      RECT 0.000 277.445 0.070 277.515 ;
    END
  END W0_data[453]
  PIN W0_data[454]
    DIRECTION INPUT ;
    USE SIGNAL ;
    SHAPE ABUTMENT ;
    PORT
      LAYER metal3 ;
      RECT 0.000 277.725 0.070 277.795 ;
    END
  END W0_data[454]
  PIN W0_data[455]
    DIRECTION INPUT ;
    USE SIGNAL ;
    SHAPE ABUTMENT ;
    PORT
      LAYER metal3 ;
      RECT 0.000 278.005 0.070 278.075 ;
    END
  END W0_data[455]
  PIN W0_data[456]
    DIRECTION INPUT ;
    USE SIGNAL ;
    SHAPE ABUTMENT ;
    PORT
      LAYER metal3 ;
      RECT 0.000 278.285 0.070 278.355 ;
    END
  END W0_data[456]
  PIN W0_data[457]
    DIRECTION INPUT ;
    USE SIGNAL ;
    SHAPE ABUTMENT ;
    PORT
      LAYER metal3 ;
      RECT 0.000 278.565 0.070 278.635 ;
    END
  END W0_data[457]
  PIN W0_data[458]
    DIRECTION INPUT ;
    USE SIGNAL ;
    SHAPE ABUTMENT ;
    PORT
      LAYER metal3 ;
      RECT 0.000 278.845 0.070 278.915 ;
    END
  END W0_data[458]
  PIN W0_data[459]
    DIRECTION INPUT ;
    USE SIGNAL ;
    SHAPE ABUTMENT ;
    PORT
      LAYER metal3 ;
      RECT 0.000 279.125 0.070 279.195 ;
    END
  END W0_data[459]
  PIN W0_data[460]
    DIRECTION INPUT ;
    USE SIGNAL ;
    SHAPE ABUTMENT ;
    PORT
      LAYER metal3 ;
      RECT 0.000 279.405 0.070 279.475 ;
    END
  END W0_data[460]
  PIN W0_data[461]
    DIRECTION INPUT ;
    USE SIGNAL ;
    SHAPE ABUTMENT ;
    PORT
      LAYER metal3 ;
      RECT 0.000 279.685 0.070 279.755 ;
    END
  END W0_data[461]
  PIN W0_data[462]
    DIRECTION INPUT ;
    USE SIGNAL ;
    SHAPE ABUTMENT ;
    PORT
      LAYER metal3 ;
      RECT 0.000 279.965 0.070 280.035 ;
    END
  END W0_data[462]
  PIN W0_data[463]
    DIRECTION INPUT ;
    USE SIGNAL ;
    SHAPE ABUTMENT ;
    PORT
      LAYER metal3 ;
      RECT 0.000 280.245 0.070 280.315 ;
    END
  END W0_data[463]
  PIN W0_data[464]
    DIRECTION INPUT ;
    USE SIGNAL ;
    SHAPE ABUTMENT ;
    PORT
      LAYER metal3 ;
      RECT 0.000 280.525 0.070 280.595 ;
    END
  END W0_data[464]
  PIN W0_data[465]
    DIRECTION INPUT ;
    USE SIGNAL ;
    SHAPE ABUTMENT ;
    PORT
      LAYER metal3 ;
      RECT 0.000 280.805 0.070 280.875 ;
    END
  END W0_data[465]
  PIN W0_data[466]
    DIRECTION INPUT ;
    USE SIGNAL ;
    SHAPE ABUTMENT ;
    PORT
      LAYER metal3 ;
      RECT 0.000 281.085 0.070 281.155 ;
    END
  END W0_data[466]
  PIN W0_data[467]
    DIRECTION INPUT ;
    USE SIGNAL ;
    SHAPE ABUTMENT ;
    PORT
      LAYER metal3 ;
      RECT 0.000 281.365 0.070 281.435 ;
    END
  END W0_data[467]
  PIN W0_data[468]
    DIRECTION INPUT ;
    USE SIGNAL ;
    SHAPE ABUTMENT ;
    PORT
      LAYER metal3 ;
      RECT 0.000 281.645 0.070 281.715 ;
    END
  END W0_data[468]
  PIN W0_data[469]
    DIRECTION INPUT ;
    USE SIGNAL ;
    SHAPE ABUTMENT ;
    PORT
      LAYER metal3 ;
      RECT 0.000 281.925 0.070 281.995 ;
    END
  END W0_data[469]
  PIN W0_data[470]
    DIRECTION INPUT ;
    USE SIGNAL ;
    SHAPE ABUTMENT ;
    PORT
      LAYER metal3 ;
      RECT 0.000 282.205 0.070 282.275 ;
    END
  END W0_data[470]
  PIN W0_data[471]
    DIRECTION INPUT ;
    USE SIGNAL ;
    SHAPE ABUTMENT ;
    PORT
      LAYER metal3 ;
      RECT 0.000 282.485 0.070 282.555 ;
    END
  END W0_data[471]
  PIN W0_data[472]
    DIRECTION INPUT ;
    USE SIGNAL ;
    SHAPE ABUTMENT ;
    PORT
      LAYER metal3 ;
      RECT 0.000 282.765 0.070 282.835 ;
    END
  END W0_data[472]
  PIN W0_data[473]
    DIRECTION INPUT ;
    USE SIGNAL ;
    SHAPE ABUTMENT ;
    PORT
      LAYER metal3 ;
      RECT 0.000 283.045 0.070 283.115 ;
    END
  END W0_data[473]
  PIN W0_data[474]
    DIRECTION INPUT ;
    USE SIGNAL ;
    SHAPE ABUTMENT ;
    PORT
      LAYER metal3 ;
      RECT 0.000 283.325 0.070 283.395 ;
    END
  END W0_data[474]
  PIN W0_data[475]
    DIRECTION INPUT ;
    USE SIGNAL ;
    SHAPE ABUTMENT ;
    PORT
      LAYER metal3 ;
      RECT 0.000 283.605 0.070 283.675 ;
    END
  END W0_data[475]
  PIN W0_data[476]
    DIRECTION INPUT ;
    USE SIGNAL ;
    SHAPE ABUTMENT ;
    PORT
      LAYER metal3 ;
      RECT 0.000 283.885 0.070 283.955 ;
    END
  END W0_data[476]
  PIN W0_data[477]
    DIRECTION INPUT ;
    USE SIGNAL ;
    SHAPE ABUTMENT ;
    PORT
      LAYER metal3 ;
      RECT 0.000 284.165 0.070 284.235 ;
    END
  END W0_data[477]
  PIN W0_data[478]
    DIRECTION INPUT ;
    USE SIGNAL ;
    SHAPE ABUTMENT ;
    PORT
      LAYER metal3 ;
      RECT 0.000 284.445 0.070 284.515 ;
    END
  END W0_data[478]
  PIN W0_data[479]
    DIRECTION INPUT ;
    USE SIGNAL ;
    SHAPE ABUTMENT ;
    PORT
      LAYER metal3 ;
      RECT 0.000 284.725 0.070 284.795 ;
    END
  END W0_data[479]
  PIN W0_data[480]
    DIRECTION INPUT ;
    USE SIGNAL ;
    SHAPE ABUTMENT ;
    PORT
      LAYER metal3 ;
      RECT 0.000 285.005 0.070 285.075 ;
    END
  END W0_data[480]
  PIN W0_data[481]
    DIRECTION INPUT ;
    USE SIGNAL ;
    SHAPE ABUTMENT ;
    PORT
      LAYER metal3 ;
      RECT 0.000 285.285 0.070 285.355 ;
    END
  END W0_data[481]
  PIN W0_data[482]
    DIRECTION INPUT ;
    USE SIGNAL ;
    SHAPE ABUTMENT ;
    PORT
      LAYER metal3 ;
      RECT 0.000 285.565 0.070 285.635 ;
    END
  END W0_data[482]
  PIN W0_data[483]
    DIRECTION INPUT ;
    USE SIGNAL ;
    SHAPE ABUTMENT ;
    PORT
      LAYER metal3 ;
      RECT 0.000 285.845 0.070 285.915 ;
    END
  END W0_data[483]
  PIN W0_data[484]
    DIRECTION INPUT ;
    USE SIGNAL ;
    SHAPE ABUTMENT ;
    PORT
      LAYER metal3 ;
      RECT 0.000 286.125 0.070 286.195 ;
    END
  END W0_data[484]
  PIN W0_data[485]
    DIRECTION INPUT ;
    USE SIGNAL ;
    SHAPE ABUTMENT ;
    PORT
      LAYER metal3 ;
      RECT 0.000 286.405 0.070 286.475 ;
    END
  END W0_data[485]
  PIN W0_data[486]
    DIRECTION INPUT ;
    USE SIGNAL ;
    SHAPE ABUTMENT ;
    PORT
      LAYER metal3 ;
      RECT 0.000 286.685 0.070 286.755 ;
    END
  END W0_data[486]
  PIN W0_data[487]
    DIRECTION INPUT ;
    USE SIGNAL ;
    SHAPE ABUTMENT ;
    PORT
      LAYER metal3 ;
      RECT 0.000 286.965 0.070 287.035 ;
    END
  END W0_data[487]
  PIN W0_data[488]
    DIRECTION INPUT ;
    USE SIGNAL ;
    SHAPE ABUTMENT ;
    PORT
      LAYER metal3 ;
      RECT 0.000 287.245 0.070 287.315 ;
    END
  END W0_data[488]
  PIN W0_data[489]
    DIRECTION INPUT ;
    USE SIGNAL ;
    SHAPE ABUTMENT ;
    PORT
      LAYER metal3 ;
      RECT 0.000 287.525 0.070 287.595 ;
    END
  END W0_data[489]
  PIN W0_data[490]
    DIRECTION INPUT ;
    USE SIGNAL ;
    SHAPE ABUTMENT ;
    PORT
      LAYER metal3 ;
      RECT 0.000 287.805 0.070 287.875 ;
    END
  END W0_data[490]
  PIN W0_data[491]
    DIRECTION INPUT ;
    USE SIGNAL ;
    SHAPE ABUTMENT ;
    PORT
      LAYER metal3 ;
      RECT 0.000 288.085 0.070 288.155 ;
    END
  END W0_data[491]
  PIN W0_data[492]
    DIRECTION INPUT ;
    USE SIGNAL ;
    SHAPE ABUTMENT ;
    PORT
      LAYER metal3 ;
      RECT 0.000 288.365 0.070 288.435 ;
    END
  END W0_data[492]
  PIN W0_data[493]
    DIRECTION INPUT ;
    USE SIGNAL ;
    SHAPE ABUTMENT ;
    PORT
      LAYER metal3 ;
      RECT 0.000 288.645 0.070 288.715 ;
    END
  END W0_data[493]
  PIN W0_data[494]
    DIRECTION INPUT ;
    USE SIGNAL ;
    SHAPE ABUTMENT ;
    PORT
      LAYER metal3 ;
      RECT 0.000 288.925 0.070 288.995 ;
    END
  END W0_data[494]
  PIN W0_data[495]
    DIRECTION INPUT ;
    USE SIGNAL ;
    SHAPE ABUTMENT ;
    PORT
      LAYER metal3 ;
      RECT 0.000 289.205 0.070 289.275 ;
    END
  END W0_data[495]
  PIN W0_data[496]
    DIRECTION INPUT ;
    USE SIGNAL ;
    SHAPE ABUTMENT ;
    PORT
      LAYER metal3 ;
      RECT 0.000 289.485 0.070 289.555 ;
    END
  END W0_data[496]
  PIN W0_data[497]
    DIRECTION INPUT ;
    USE SIGNAL ;
    SHAPE ABUTMENT ;
    PORT
      LAYER metal3 ;
      RECT 0.000 289.765 0.070 289.835 ;
    END
  END W0_data[497]
  PIN W0_data[498]
    DIRECTION INPUT ;
    USE SIGNAL ;
    SHAPE ABUTMENT ;
    PORT
      LAYER metal3 ;
      RECT 0.000 290.045 0.070 290.115 ;
    END
  END W0_data[498]
  PIN W0_data[499]
    DIRECTION INPUT ;
    USE SIGNAL ;
    SHAPE ABUTMENT ;
    PORT
      LAYER metal3 ;
      RECT 0.000 290.325 0.070 290.395 ;
    END
  END W0_data[499]
  PIN W0_data[500]
    DIRECTION INPUT ;
    USE SIGNAL ;
    SHAPE ABUTMENT ;
    PORT
      LAYER metal3 ;
      RECT 0.000 290.605 0.070 290.675 ;
    END
  END W0_data[500]
  PIN W0_data[501]
    DIRECTION INPUT ;
    USE SIGNAL ;
    SHAPE ABUTMENT ;
    PORT
      LAYER metal3 ;
      RECT 0.000 290.885 0.070 290.955 ;
    END
  END W0_data[501]
  PIN W0_data[502]
    DIRECTION INPUT ;
    USE SIGNAL ;
    SHAPE ABUTMENT ;
    PORT
      LAYER metal3 ;
      RECT 0.000 291.165 0.070 291.235 ;
    END
  END W0_data[502]
  PIN W0_data[503]
    DIRECTION INPUT ;
    USE SIGNAL ;
    SHAPE ABUTMENT ;
    PORT
      LAYER metal3 ;
      RECT 0.000 291.445 0.070 291.515 ;
    END
  END W0_data[503]
  PIN W0_data[504]
    DIRECTION INPUT ;
    USE SIGNAL ;
    SHAPE ABUTMENT ;
    PORT
      LAYER metal3 ;
      RECT 0.000 291.725 0.070 291.795 ;
    END
  END W0_data[504]
  PIN W0_data[505]
    DIRECTION INPUT ;
    USE SIGNAL ;
    SHAPE ABUTMENT ;
    PORT
      LAYER metal3 ;
      RECT 0.000 292.005 0.070 292.075 ;
    END
  END W0_data[505]
  PIN W0_data[506]
    DIRECTION INPUT ;
    USE SIGNAL ;
    SHAPE ABUTMENT ;
    PORT
      LAYER metal3 ;
      RECT 0.000 292.285 0.070 292.355 ;
    END
  END W0_data[506]
  PIN W0_data[507]
    DIRECTION INPUT ;
    USE SIGNAL ;
    SHAPE ABUTMENT ;
    PORT
      LAYER metal3 ;
      RECT 0.000 292.565 0.070 292.635 ;
    END
  END W0_data[507]
  PIN W0_data[508]
    DIRECTION INPUT ;
    USE SIGNAL ;
    SHAPE ABUTMENT ;
    PORT
      LAYER metal3 ;
      RECT 0.000 292.845 0.070 292.915 ;
    END
  END W0_data[508]
  PIN W0_data[509]
    DIRECTION INPUT ;
    USE SIGNAL ;
    SHAPE ABUTMENT ;
    PORT
      LAYER metal3 ;
      RECT 0.000 293.125 0.070 293.195 ;
    END
  END W0_data[509]
  PIN W0_data[510]
    DIRECTION INPUT ;
    USE SIGNAL ;
    SHAPE ABUTMENT ;
    PORT
      LAYER metal3 ;
      RECT 0.000 293.405 0.070 293.475 ;
    END
  END W0_data[510]
  PIN W0_data[511]
    DIRECTION INPUT ;
    USE SIGNAL ;
    SHAPE ABUTMENT ;
    PORT
      LAYER metal3 ;
      RECT 0.000 293.685 0.070 293.755 ;
    END
  END W0_data[511]
  PIN W0_en
    DIRECTION INPUT ;
    USE SIGNAL ;
    SHAPE ABUTMENT ;
    PORT
      LAYER metal3 ;
      RECT 0.000 293.965 0.070 294.035 ;
    END
  END W0_en
  PIN W0_mask[0]
    DIRECTION INPUT ;
    USE SIGNAL ;
    SHAPE ABUTMENT ;
    PORT
      LAYER metal3 ;
      RECT 0.000 294.245 0.070 294.315 ;
    END
  END W0_mask[0]
  PIN W0_mask[1]
    DIRECTION INPUT ;
    USE SIGNAL ;
    SHAPE ABUTMENT ;
    PORT
      LAYER metal3 ;
      RECT 0.000 294.525 0.070 294.595 ;
    END
  END W0_mask[1]
  PIN W0_mask[2]
    DIRECTION INPUT ;
    USE SIGNAL ;
    SHAPE ABUTMENT ;
    PORT
      LAYER metal3 ;
      RECT 0.000 294.805 0.070 294.875 ;
    END
  END W0_mask[2]
  PIN W0_mask[3]
    DIRECTION INPUT ;
    USE SIGNAL ;
    SHAPE ABUTMENT ;
    PORT
      LAYER metal3 ;
      RECT 0.000 295.085 0.070 295.155 ;
    END
  END W0_mask[3]
  PIN W0_mask[4]
    DIRECTION INPUT ;
    USE SIGNAL ;
    SHAPE ABUTMENT ;
    PORT
      LAYER metal3 ;
      RECT 0.000 295.365 0.070 295.435 ;
    END
  END W0_mask[4]
  PIN W0_mask[5]
    DIRECTION INPUT ;
    USE SIGNAL ;
    SHAPE ABUTMENT ;
    PORT
      LAYER metal3 ;
      RECT 0.000 295.645 0.070 295.715 ;
    END
  END W0_mask[5]
  PIN W0_mask[6]
    DIRECTION INPUT ;
    USE SIGNAL ;
    SHAPE ABUTMENT ;
    PORT
      LAYER metal3 ;
      RECT 0.000 295.925 0.070 295.995 ;
    END
  END W0_mask[6]
  PIN W0_mask[7]
    DIRECTION INPUT ;
    USE SIGNAL ;
    SHAPE ABUTMENT ;
    PORT
      LAYER metal3 ;
      RECT 0.000 296.205 0.070 296.275 ;
    END
  END W0_mask[7]
  PIN W0_mask[8]
    DIRECTION INPUT ;
    USE SIGNAL ;
    SHAPE ABUTMENT ;
    PORT
      LAYER metal3 ;
      RECT 0.000 296.485 0.070 296.555 ;
    END
  END W0_mask[8]
  PIN W0_mask[9]
    DIRECTION INPUT ;
    USE SIGNAL ;
    SHAPE ABUTMENT ;
    PORT
      LAYER metal3 ;
      RECT 0.000 296.765 0.070 296.835 ;
    END
  END W0_mask[9]
  PIN W0_mask[10]
    DIRECTION INPUT ;
    USE SIGNAL ;
    SHAPE ABUTMENT ;
    PORT
      LAYER metal3 ;
      RECT 0.000 297.045 0.070 297.115 ;
    END
  END W0_mask[10]
  PIN W0_mask[11]
    DIRECTION INPUT ;
    USE SIGNAL ;
    SHAPE ABUTMENT ;
    PORT
      LAYER metal3 ;
      RECT 0.000 297.325 0.070 297.395 ;
    END
  END W0_mask[11]
  PIN W0_mask[12]
    DIRECTION INPUT ;
    USE SIGNAL ;
    SHAPE ABUTMENT ;
    PORT
      LAYER metal3 ;
      RECT 0.000 297.605 0.070 297.675 ;
    END
  END W0_mask[12]
  PIN W0_mask[13]
    DIRECTION INPUT ;
    USE SIGNAL ;
    SHAPE ABUTMENT ;
    PORT
      LAYER metal3 ;
      RECT 0.000 297.885 0.070 297.955 ;
    END
  END W0_mask[13]
  PIN W0_mask[14]
    DIRECTION INPUT ;
    USE SIGNAL ;
    SHAPE ABUTMENT ;
    PORT
      LAYER metal3 ;
      RECT 0.000 298.165 0.070 298.235 ;
    END
  END W0_mask[14]
  PIN W0_mask[15]
    DIRECTION INPUT ;
    USE SIGNAL ;
    SHAPE ABUTMENT ;
    PORT
      LAYER metal3 ;
      RECT 0.000 298.445 0.070 298.515 ;
    END
  END W0_mask[15]
  PIN W0_mask[16]
    DIRECTION INPUT ;
    USE SIGNAL ;
    SHAPE ABUTMENT ;
    PORT
      LAYER metal3 ;
      RECT 0.000 298.725 0.070 298.795 ;
    END
  END W0_mask[16]
  PIN W0_mask[17]
    DIRECTION INPUT ;
    USE SIGNAL ;
    SHAPE ABUTMENT ;
    PORT
      LAYER metal3 ;
      RECT 0.000 299.005 0.070 299.075 ;
    END
  END W0_mask[17]
  PIN W0_mask[18]
    DIRECTION INPUT ;
    USE SIGNAL ;
    SHAPE ABUTMENT ;
    PORT
      LAYER metal3 ;
      RECT 0.000 299.285 0.070 299.355 ;
    END
  END W0_mask[18]
  PIN W0_mask[19]
    DIRECTION INPUT ;
    USE SIGNAL ;
    SHAPE ABUTMENT ;
    PORT
      LAYER metal3 ;
      RECT 0.000 299.565 0.070 299.635 ;
    END
  END W0_mask[19]
  PIN W0_mask[20]
    DIRECTION INPUT ;
    USE SIGNAL ;
    SHAPE ABUTMENT ;
    PORT
      LAYER metal3 ;
      RECT 0.000 299.845 0.070 299.915 ;
    END
  END W0_mask[20]
  PIN W0_mask[21]
    DIRECTION INPUT ;
    USE SIGNAL ;
    SHAPE ABUTMENT ;
    PORT
      LAYER metal3 ;
      RECT 0.000 300.125 0.070 300.195 ;
    END
  END W0_mask[21]
  PIN W0_mask[22]
    DIRECTION INPUT ;
    USE SIGNAL ;
    SHAPE ABUTMENT ;
    PORT
      LAYER metal3 ;
      RECT 0.000 300.405 0.070 300.475 ;
    END
  END W0_mask[22]
  PIN W0_mask[23]
    DIRECTION INPUT ;
    USE SIGNAL ;
    SHAPE ABUTMENT ;
    PORT
      LAYER metal3 ;
      RECT 0.000 300.685 0.070 300.755 ;
    END
  END W0_mask[23]
  PIN W0_mask[24]
    DIRECTION INPUT ;
    USE SIGNAL ;
    SHAPE ABUTMENT ;
    PORT
      LAYER metal3 ;
      RECT 0.000 300.965 0.070 301.035 ;
    END
  END W0_mask[24]
  PIN W0_mask[25]
    DIRECTION INPUT ;
    USE SIGNAL ;
    SHAPE ABUTMENT ;
    PORT
      LAYER metal3 ;
      RECT 0.000 301.245 0.070 301.315 ;
    END
  END W0_mask[25]
  PIN W0_mask[26]
    DIRECTION INPUT ;
    USE SIGNAL ;
    SHAPE ABUTMENT ;
    PORT
      LAYER metal3 ;
      RECT 0.000 301.525 0.070 301.595 ;
    END
  END W0_mask[26]
  PIN W0_mask[27]
    DIRECTION INPUT ;
    USE SIGNAL ;
    SHAPE ABUTMENT ;
    PORT
      LAYER metal3 ;
      RECT 0.000 301.805 0.070 301.875 ;
    END
  END W0_mask[27]
  PIN W0_mask[28]
    DIRECTION INPUT ;
    USE SIGNAL ;
    SHAPE ABUTMENT ;
    PORT
      LAYER metal3 ;
      RECT 0.000 302.085 0.070 302.155 ;
    END
  END W0_mask[28]
  PIN W0_mask[29]
    DIRECTION INPUT ;
    USE SIGNAL ;
    SHAPE ABUTMENT ;
    PORT
      LAYER metal3 ;
      RECT 0.000 302.365 0.070 302.435 ;
    END
  END W0_mask[29]
  PIN W0_mask[30]
    DIRECTION INPUT ;
    USE SIGNAL ;
    SHAPE ABUTMENT ;
    PORT
      LAYER metal3 ;
      RECT 0.000 302.645 0.070 302.715 ;
    END
  END W0_mask[30]
  PIN W0_mask[31]
    DIRECTION INPUT ;
    USE SIGNAL ;
    SHAPE ABUTMENT ;
    PORT
      LAYER metal3 ;
      RECT 0.000 302.925 0.070 302.995 ;
    END
  END W0_mask[31]
  PIN W0_mask[32]
    DIRECTION INPUT ;
    USE SIGNAL ;
    SHAPE ABUTMENT ;
    PORT
      LAYER metal3 ;
      RECT 0.000 303.205 0.070 303.275 ;
    END
  END W0_mask[32]
  PIN W0_mask[33]
    DIRECTION INPUT ;
    USE SIGNAL ;
    SHAPE ABUTMENT ;
    PORT
      LAYER metal3 ;
      RECT 0.000 303.485 0.070 303.555 ;
    END
  END W0_mask[33]
  PIN W0_mask[34]
    DIRECTION INPUT ;
    USE SIGNAL ;
    SHAPE ABUTMENT ;
    PORT
      LAYER metal3 ;
      RECT 0.000 303.765 0.070 303.835 ;
    END
  END W0_mask[34]
  PIN W0_mask[35]
    DIRECTION INPUT ;
    USE SIGNAL ;
    SHAPE ABUTMENT ;
    PORT
      LAYER metal3 ;
      RECT 0.000 304.045 0.070 304.115 ;
    END
  END W0_mask[35]
  PIN W0_mask[36]
    DIRECTION INPUT ;
    USE SIGNAL ;
    SHAPE ABUTMENT ;
    PORT
      LAYER metal3 ;
      RECT 0.000 304.325 0.070 304.395 ;
    END
  END W0_mask[36]
  PIN W0_mask[37]
    DIRECTION INPUT ;
    USE SIGNAL ;
    SHAPE ABUTMENT ;
    PORT
      LAYER metal3 ;
      RECT 0.000 304.605 0.070 304.675 ;
    END
  END W0_mask[37]
  PIN W0_mask[38]
    DIRECTION INPUT ;
    USE SIGNAL ;
    SHAPE ABUTMENT ;
    PORT
      LAYER metal3 ;
      RECT 0.000 304.885 0.070 304.955 ;
    END
  END W0_mask[38]
  PIN W0_mask[39]
    DIRECTION INPUT ;
    USE SIGNAL ;
    SHAPE ABUTMENT ;
    PORT
      LAYER metal3 ;
      RECT 0.000 305.165 0.070 305.235 ;
    END
  END W0_mask[39]
  PIN W0_mask[40]
    DIRECTION INPUT ;
    USE SIGNAL ;
    SHAPE ABUTMENT ;
    PORT
      LAYER metal3 ;
      RECT 0.000 305.445 0.070 305.515 ;
    END
  END W0_mask[40]
  PIN W0_mask[41]
    DIRECTION INPUT ;
    USE SIGNAL ;
    SHAPE ABUTMENT ;
    PORT
      LAYER metal3 ;
      RECT 0.000 305.725 0.070 305.795 ;
    END
  END W0_mask[41]
  PIN W0_mask[42]
    DIRECTION INPUT ;
    USE SIGNAL ;
    SHAPE ABUTMENT ;
    PORT
      LAYER metal3 ;
      RECT 0.000 306.005 0.070 306.075 ;
    END
  END W0_mask[42]
  PIN W0_mask[43]
    DIRECTION INPUT ;
    USE SIGNAL ;
    SHAPE ABUTMENT ;
    PORT
      LAYER metal3 ;
      RECT 0.000 306.285 0.070 306.355 ;
    END
  END W0_mask[43]
  PIN W0_mask[44]
    DIRECTION INPUT ;
    USE SIGNAL ;
    SHAPE ABUTMENT ;
    PORT
      LAYER metal3 ;
      RECT 0.000 306.565 0.070 306.635 ;
    END
  END W0_mask[44]
  PIN W0_mask[45]
    DIRECTION INPUT ;
    USE SIGNAL ;
    SHAPE ABUTMENT ;
    PORT
      LAYER metal3 ;
      RECT 0.000 306.845 0.070 306.915 ;
    END
  END W0_mask[45]
  PIN W0_mask[46]
    DIRECTION INPUT ;
    USE SIGNAL ;
    SHAPE ABUTMENT ;
    PORT
      LAYER metal3 ;
      RECT 0.000 307.125 0.070 307.195 ;
    END
  END W0_mask[46]
  PIN W0_mask[47]
    DIRECTION INPUT ;
    USE SIGNAL ;
    SHAPE ABUTMENT ;
    PORT
      LAYER metal3 ;
      RECT 0.000 307.405 0.070 307.475 ;
    END
  END W0_mask[47]
  PIN W0_mask[48]
    DIRECTION INPUT ;
    USE SIGNAL ;
    SHAPE ABUTMENT ;
    PORT
      LAYER metal3 ;
      RECT 0.000 307.685 0.070 307.755 ;
    END
  END W0_mask[48]
  PIN W0_mask[49]
    DIRECTION INPUT ;
    USE SIGNAL ;
    SHAPE ABUTMENT ;
    PORT
      LAYER metal3 ;
      RECT 0.000 307.965 0.070 308.035 ;
    END
  END W0_mask[49]
  PIN W0_mask[50]
    DIRECTION INPUT ;
    USE SIGNAL ;
    SHAPE ABUTMENT ;
    PORT
      LAYER metal3 ;
      RECT 0.000 308.245 0.070 308.315 ;
    END
  END W0_mask[50]
  PIN W0_mask[51]
    DIRECTION INPUT ;
    USE SIGNAL ;
    SHAPE ABUTMENT ;
    PORT
      LAYER metal3 ;
      RECT 0.000 308.525 0.070 308.595 ;
    END
  END W0_mask[51]
  PIN W0_mask[52]
    DIRECTION INPUT ;
    USE SIGNAL ;
    SHAPE ABUTMENT ;
    PORT
      LAYER metal3 ;
      RECT 0.000 308.805 0.070 308.875 ;
    END
  END W0_mask[52]
  PIN W0_mask[53]
    DIRECTION INPUT ;
    USE SIGNAL ;
    SHAPE ABUTMENT ;
    PORT
      LAYER metal3 ;
      RECT 0.000 309.085 0.070 309.155 ;
    END
  END W0_mask[53]
  PIN W0_mask[54]
    DIRECTION INPUT ;
    USE SIGNAL ;
    SHAPE ABUTMENT ;
    PORT
      LAYER metal3 ;
      RECT 0.000 309.365 0.070 309.435 ;
    END
  END W0_mask[54]
  PIN W0_mask[55]
    DIRECTION INPUT ;
    USE SIGNAL ;
    SHAPE ABUTMENT ;
    PORT
      LAYER metal3 ;
      RECT 0.000 309.645 0.070 309.715 ;
    END
  END W0_mask[55]
  PIN W0_mask[56]
    DIRECTION INPUT ;
    USE SIGNAL ;
    SHAPE ABUTMENT ;
    PORT
      LAYER metal3 ;
      RECT 0.000 309.925 0.070 309.995 ;
    END
  END W0_mask[56]
  PIN W0_mask[57]
    DIRECTION INPUT ;
    USE SIGNAL ;
    SHAPE ABUTMENT ;
    PORT
      LAYER metal3 ;
      RECT 0.000 310.205 0.070 310.275 ;
    END
  END W0_mask[57]
  PIN W0_mask[58]
    DIRECTION INPUT ;
    USE SIGNAL ;
    SHAPE ABUTMENT ;
    PORT
      LAYER metal3 ;
      RECT 0.000 310.485 0.070 310.555 ;
    END
  END W0_mask[58]
  PIN W0_mask[59]
    DIRECTION INPUT ;
    USE SIGNAL ;
    SHAPE ABUTMENT ;
    PORT
      LAYER metal3 ;
      RECT 0.000 310.765 0.070 310.835 ;
    END
  END W0_mask[59]
  PIN W0_mask[60]
    DIRECTION INPUT ;
    USE SIGNAL ;
    SHAPE ABUTMENT ;
    PORT
      LAYER metal3 ;
      RECT 0.000 311.045 0.070 311.115 ;
    END
  END W0_mask[60]
  PIN W0_mask[61]
    DIRECTION INPUT ;
    USE SIGNAL ;
    SHAPE ABUTMENT ;
    PORT
      LAYER metal3 ;
      RECT 0.000 311.325 0.070 311.395 ;
    END
  END W0_mask[61]
  PIN W0_mask[62]
    DIRECTION INPUT ;
    USE SIGNAL ;
    SHAPE ABUTMENT ;
    PORT
      LAYER metal3 ;
      RECT 0.000 311.605 0.070 311.675 ;
    END
  END W0_mask[62]
  PIN W0_mask[63]
    DIRECTION INPUT ;
    USE SIGNAL ;
    SHAPE ABUTMENT ;
    PORT
      LAYER metal3 ;
      RECT 0.000 311.885 0.070 311.955 ;
    END
  END W0_mask[63]
  PIN VSS
    DIRECTION INOUT ;
    USE GROUND ;
    PORT
      LAYER metal4 ;
      RECT 0.280 0.560 431.400 1.040 ;
      RECT 0.280 6.160 431.400 6.640 ;
      RECT 0.280 11.760 431.400 12.240 ;
      RECT 0.280 17.360 431.400 17.840 ;
      RECT 0.280 22.960 431.400 23.440 ;
      RECT 0.280 28.560 431.400 29.040 ;
      RECT 0.280 34.160 431.400 34.640 ;
      RECT 0.280 39.760 431.400 40.240 ;
      RECT 0.280 45.360 431.400 45.840 ;
      RECT 0.280 50.960 431.400 51.440 ;
      RECT 0.280 56.560 431.400 57.040 ;
      RECT 0.280 62.160 431.400 62.640 ;
      RECT 0.280 67.760 431.400 68.240 ;
      RECT 0.280 73.360 431.400 73.840 ;
      RECT 0.280 78.960 431.400 79.440 ;
      RECT 0.280 84.560 431.400 85.040 ;
      RECT 0.280 90.160 431.400 90.640 ;
      RECT 0.280 95.760 431.400 96.240 ;
      RECT 0.280 101.360 431.400 101.840 ;
      RECT 0.280 106.960 431.400 107.440 ;
      RECT 0.280 112.560 431.400 113.040 ;
      RECT 0.280 118.160 431.400 118.640 ;
      RECT 0.280 123.760 431.400 124.240 ;
      RECT 0.280 129.360 431.400 129.840 ;
      RECT 0.280 134.960 431.400 135.440 ;
      RECT 0.280 140.560 431.400 141.040 ;
      RECT 0.280 146.160 431.400 146.640 ;
      RECT 0.280 151.760 431.400 152.240 ;
      RECT 0.280 157.360 431.400 157.840 ;
      RECT 0.280 162.960 431.400 163.440 ;
      RECT 0.280 168.560 431.400 169.040 ;
      RECT 0.280 174.160 431.400 174.640 ;
      RECT 0.280 179.760 431.400 180.240 ;
      RECT 0.280 185.360 431.400 185.840 ;
      RECT 0.280 190.960 431.400 191.440 ;
      RECT 0.280 196.560 431.400 197.040 ;
      RECT 0.280 202.160 431.400 202.640 ;
      RECT 0.280 207.760 431.400 208.240 ;
      RECT 0.280 213.360 431.400 213.840 ;
      RECT 0.280 218.960 431.400 219.440 ;
      RECT 0.280 224.560 431.400 225.040 ;
      RECT 0.280 230.160 431.400 230.640 ;
      RECT 0.280 235.760 431.400 236.240 ;
      RECT 0.280 241.360 431.400 241.840 ;
      RECT 0.280 246.960 431.400 247.440 ;
      RECT 0.280 252.560 431.400 253.040 ;
      RECT 0.280 258.160 431.400 258.640 ;
      RECT 0.280 263.760 431.400 264.240 ;
      RECT 0.280 269.360 431.400 269.840 ;
      RECT 0.280 274.960 431.400 275.440 ;
      RECT 0.280 280.560 431.400 281.040 ;
      RECT 0.280 286.160 431.400 286.640 ;
      RECT 0.280 291.760 431.400 292.240 ;
      RECT 0.280 297.360 431.400 297.840 ;
      RECT 0.280 302.960 431.400 303.440 ;
      RECT 0.280 308.560 431.400 309.040 ;
      RECT 0.280 314.160 431.400 314.640 ;
      RECT 0.280 319.760 431.400 320.240 ;
    END
  END VSS
  PIN VDD
    DIRECTION INOUT ;
    USE POWER ;
    PORT
      LAYER metal4 ;
      RECT 0.280 2.800 431.400 3.280 ;
      RECT 0.280 8.400 431.400 8.880 ;
      RECT 0.280 14.000 431.400 14.480 ;
      RECT 0.280 19.600 431.400 20.080 ;
      RECT 0.280 25.200 431.400 25.680 ;
      RECT 0.280 30.800 431.400 31.280 ;
      RECT 0.280 36.400 431.400 36.880 ;
      RECT 0.280 42.000 431.400 42.480 ;
      RECT 0.280 47.600 431.400 48.080 ;
      RECT 0.280 53.200 431.400 53.680 ;
      RECT 0.280 58.800 431.400 59.280 ;
      RECT 0.280 64.400 431.400 64.880 ;
      RECT 0.280 70.000 431.400 70.480 ;
      RECT 0.280 75.600 431.400 76.080 ;
      RECT 0.280 81.200 431.400 81.680 ;
      RECT 0.280 86.800 431.400 87.280 ;
      RECT 0.280 92.400 431.400 92.880 ;
      RECT 0.280 98.000 431.400 98.480 ;
      RECT 0.280 103.600 431.400 104.080 ;
      RECT 0.280 109.200 431.400 109.680 ;
      RECT 0.280 114.800 431.400 115.280 ;
      RECT 0.280 120.400 431.400 120.880 ;
      RECT 0.280 126.000 431.400 126.480 ;
      RECT 0.280 131.600 431.400 132.080 ;
      RECT 0.280 137.200 431.400 137.680 ;
      RECT 0.280 142.800 431.400 143.280 ;
      RECT 0.280 148.400 431.400 148.880 ;
      RECT 0.280 154.000 431.400 154.480 ;
      RECT 0.280 159.600 431.400 160.080 ;
      RECT 0.280 165.200 431.400 165.680 ;
      RECT 0.280 170.800 431.400 171.280 ;
      RECT 0.280 176.400 431.400 176.880 ;
      RECT 0.280 182.000 431.400 182.480 ;
      RECT 0.280 187.600 431.400 188.080 ;
      RECT 0.280 193.200 431.400 193.680 ;
      RECT 0.280 198.800 431.400 199.280 ;
      RECT 0.280 204.400 431.400 204.880 ;
      RECT 0.280 210.000 431.400 210.480 ;
      RECT 0.280 215.600 431.400 216.080 ;
      RECT 0.280 221.200 431.400 221.680 ;
      RECT 0.280 226.800 431.400 227.280 ;
      RECT 0.280 232.400 431.400 232.880 ;
      RECT 0.280 238.000 431.400 238.480 ;
      RECT 0.280 243.600 431.400 244.080 ;
      RECT 0.280 249.200 431.400 249.680 ;
      RECT 0.280 254.800 431.400 255.280 ;
      RECT 0.280 260.400 431.400 260.880 ;
      RECT 0.280 266.000 431.400 266.480 ;
      RECT 0.280 271.600 431.400 272.080 ;
      RECT 0.280 277.200 431.400 277.680 ;
      RECT 0.280 282.800 431.400 283.280 ;
      RECT 0.280 288.400 431.400 288.880 ;
      RECT 0.280 294.000 431.400 294.480 ;
      RECT 0.280 299.600 431.400 300.080 ;
      RECT 0.280 305.200 431.400 305.680 ;
      RECT 0.280 310.800 431.400 311.280 ;
      RECT 0.280 316.400 431.400 316.880 ;
    END
  END VDD
  OBS
    LAYER metal1 ; RECT 0 0 431.680 322.000 ;
    LAYER metal2 ; RECT 0 0 431.680 322.000 ;
    LAYER metal3 ; RECT 0.140 0 431.680 322.000 ;
  END
END mem_0_ext_top

END LIBRARY
